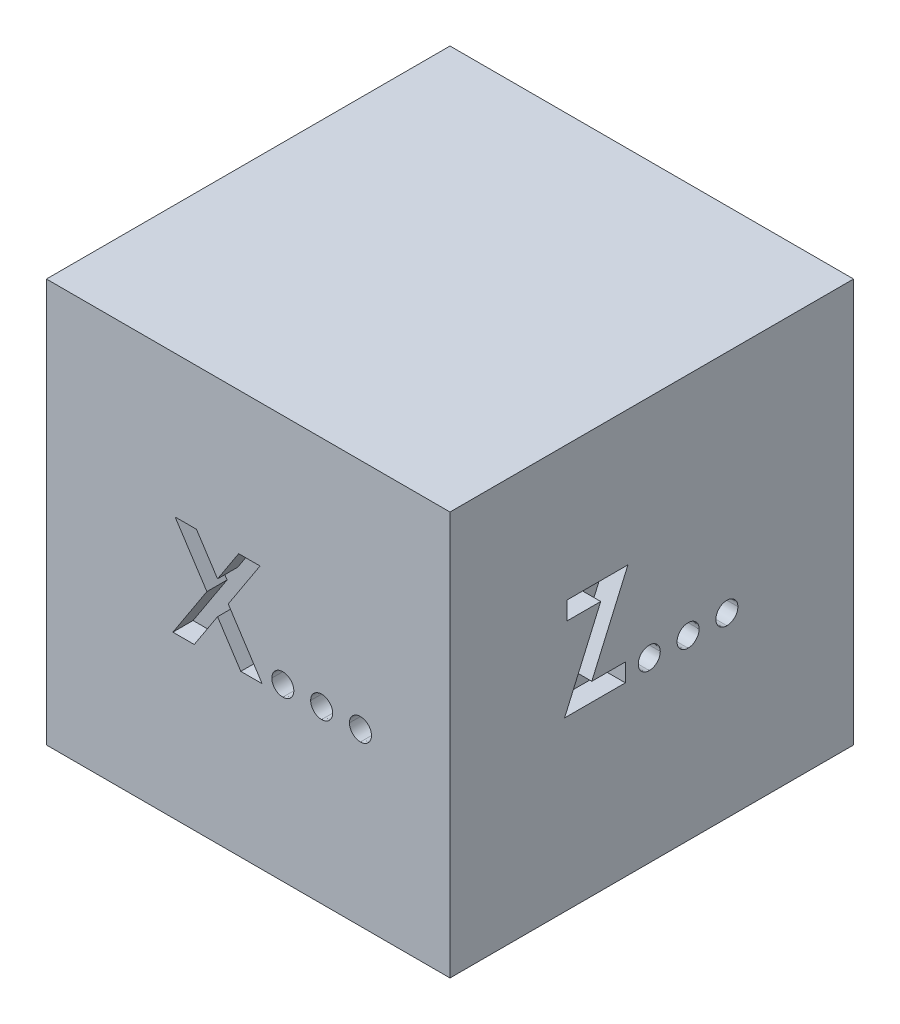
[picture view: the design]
ISO-10303-21;
HEADER;
FILE_DESCRIPTION(('STEP AP214'),'2;1');
FILE_NAME('part.step','',(''),(''),'','','');
FILE_SCHEMA(('AUTOMOTIVE_DESIGN { 1 0 10303 214 1 1 1 1 }'));
ENDSEC;
DATA;
#1=APPLICATION_CONTEXT('core data for automotive mechanical design processes');
#2=APPLICATION_PROTOCOL_DEFINITION('international standard','automotive_design',2000,#1);
#3=PRODUCT_CONTEXT('',#1,'mechanical');
#4=PRODUCT('Part','Part','',(#3));
#5=PRODUCT_RELATED_PRODUCT_CATEGORY('part','',(#4));
#6=PRODUCT_DEFINITION_FORMATION('','',#4);
#7=PRODUCT_DEFINITION_CONTEXT('part definition',#1,'design');
#8=PRODUCT_DEFINITION('design','',#6,#7);
#9=PRODUCT_DEFINITION_SHAPE('','',#8);
#10=(LENGTH_UNIT() NAMED_UNIT(*) SI_UNIT(.MILLI.,.METRE.));
#11=(NAMED_UNIT(*) PLANE_ANGLE_UNIT() SI_UNIT($,.RADIAN.));
#12=(NAMED_UNIT(*) SI_UNIT($,.STERADIAN.) SOLID_ANGLE_UNIT());
#13=UNCERTAINTY_MEASURE_WITH_UNIT(LENGTH_MEASURE(1.E-05),#10,'distance_accuracy_value','');
#14=(GEOMETRIC_REPRESENTATION_CONTEXT(3) GLOBAL_UNCERTAINTY_ASSIGNED_CONTEXT((#13)) GLOBAL_UNIT_ASSIGNED_CONTEXT((#10,
#11,#12)) REPRESENTATION_CONTEXT('',''));
#15=CARTESIAN_POINT('',(0.,0.,0.));
#16=DIRECTION('',(0.,0.,1.));
#17=DIRECTION('',(1.,0.,0.));
#18=AXIS2_PLACEMENT_3D('',#15,#16,#17);
#19=CARTESIAN_POINT('',(0.,0.,1.));
#20=DIRECTION('',(1.,0.,0.));
#21=DIRECTION('',(0.,0.,-1.));
#22=AXIS2_PLACEMENT_3D('',#19,#20,#21);
#23=PLANE('',#22);
#24=CARTESIAN_POINT('',(0.,0.525952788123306,0.604405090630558));
#25=CARTESIAN_POINT('',(0.,0.527363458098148,0.604480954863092));
#26=CARTESIAN_POINT('',(0.,0.530117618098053,0.604629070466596));
#27=CARTESIAN_POINT('',(0.,0.534060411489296,0.605827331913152));
#28=CARTESIAN_POINT('',(0.,0.537643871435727,0.607782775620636));
#29=CARTESIAN_POINT('',(0.,0.540815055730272,0.610426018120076));
#30=CARTESIAN_POINT('',(0.,0.543471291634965,0.613606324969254));
#31=CARTESIAN_POINT('',(0.,0.545404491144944,0.617198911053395));
#32=CARTESIAN_POINT('',(0.,0.546550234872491,0.621130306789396));
#33=CARTESIAN_POINT('',(0.,0.546706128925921,0.623845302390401));
#34=CARTESIAN_POINT('',(0.,0.54678612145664,0.625238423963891));
#35=B_SPLINE_CURVE_WITH_KNOTS('',3,(#24,#25,#26,#27,#28,#29,#30,#31,#32,#33,#34),.UNSPECIFIED.,
.F.,.F.,(4,1,1,1,1,1,1,1,4),(0.,0.129096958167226,0.252045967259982,0.373904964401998,
0.501037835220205,0.628170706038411,0.751376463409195,0.872426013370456,1.),.UNSPECIFIED.);
#36=CARTESIAN_POINT('',(0.,0.525952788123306,0.604405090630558));
#37=VERTEX_POINT('',#36);
#38=CARTESIAN_POINT('',(0.,0.54678612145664,0.625238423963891));
#39=VERTEX_POINT('',#38);
#40=EDGE_CURVE('E55',#37,#39,#35,.T.);
#41=ORIENTED_EDGE('',*,*,#40,.T.);
#42=CARTESIAN_POINT('',(0.,0.54678612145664,0.625238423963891));
#43=CARTESIAN_POINT('',(0.,0.54670339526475,0.626630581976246));
#44=CARTESIAN_POINT('',(0.,0.546541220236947,0.629359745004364));
#45=CARTESIAN_POINT('',(0.,0.545428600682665,0.633305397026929));
#46=CARTESIAN_POINT('',(0.,0.543452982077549,0.636876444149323));
#47=CARTESIAN_POINT('',(0.,0.540819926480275,0.640057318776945));
#48=CARTESIAN_POINT('',(0.,0.537627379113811,0.642679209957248));
#49=CARTESIAN_POINT('',(0.,0.534084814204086,0.644725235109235));
#50=CARTESIAN_POINT('',(0.,0.530106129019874,0.645828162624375));
#51=CARTESIAN_POINT('',(0.,0.527361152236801,0.645989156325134));
#52=CARTESIAN_POINT('',(0.,0.525952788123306,0.646071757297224));
#53=B_SPLINE_CURVE_WITH_KNOTS('',3,(#42,#43,#44,#45,#46,#47,#48,#49,#50,#51,#52),.UNSPECIFIED.,
.F.,.F.,(4,1,1,1,1,1,1,1,4),(0.,0.127518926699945,0.249985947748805,0.371792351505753,
0.498870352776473,0.625948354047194,0.748491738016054,0.870958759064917,1.),.UNSPECIFIED.);
#54=CARTESIAN_POINT('',(0.,0.525952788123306,0.646071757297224));
#55=VERTEX_POINT('',#54);
#56=EDGE_CURVE('E487',#39,#55,#53,.T.);
#57=ORIENTED_EDGE('',*,*,#56,.T.);
#58=CARTESIAN_POINT('',(0.,0.525952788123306,0.646071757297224));
#59=CARTESIAN_POINT('',(0.,0.524578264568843,0.645986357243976));
#60=CARTESIAN_POINT('',(0.,0.521867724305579,0.645817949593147));
#61=CARTESIAN_POINT('',(0.,0.517919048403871,0.644727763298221));
#62=CARTESIAN_POINT('',(0.,0.514374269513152,0.642663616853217));
#63=CARTESIAN_POINT('',(0.,0.511138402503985,0.640075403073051));
#64=CARTESIAN_POINT('',(0.,0.508499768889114,0.636875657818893));
#65=CARTESIAN_POINT('',(0.,0.506540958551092,0.633296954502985));
#66=CARTESIAN_POINT('',(0.,0.505348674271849,0.629369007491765));
#67=CARTESIAN_POINT('',(0.,0.505196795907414,0.626632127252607));
#68=CARTESIAN_POINT('',(0.,0.505119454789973,0.625238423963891));
#69=B_SPLINE_CURVE_WITH_KNOTS('',3,(#58,#59,#60,#61,#62,#63,#64,#65,#66,#67,#68),.UNSPECIFIED.,
.F.,.F.,(4,1,1,1,1,1,1,1,4),(0.,0.126177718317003,0.248820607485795,0.371539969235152,
0.499983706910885,0.627244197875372,0.749225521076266,0.87229795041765,1.),.UNSPECIFIED.);
#70=CARTESIAN_POINT('',(0.,0.505119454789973,0.625238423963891));
#71=VERTEX_POINT('',#70);
#72=EDGE_CURVE('E2022',#55,#71,#69,.T.);
#73=ORIENTED_EDGE('',*,*,#72,.T.);
#74=CARTESIAN_POINT('',(0.,0.505119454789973,0.625238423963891));
#75=CARTESIAN_POINT('',(0.,0.505193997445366,0.623843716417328));
#76=CARTESIAN_POINT('',(0.,0.505339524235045,0.621120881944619));
#77=CARTESIAN_POINT('',(0.,0.506565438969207,0.617207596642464));
#78=CARTESIAN_POINT('',(0.,0.508481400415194,0.61360709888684));
#79=CARTESIAN_POINT('',(0.,0.511143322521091,0.610407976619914));
#80=CARTESIAN_POINT('',(0.,0.514357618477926,0.607798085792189));
#81=CARTESIAN_POINT('',(0.,0.517943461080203,0.605824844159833));
#82=CARTESIAN_POINT('',(0.,0.521856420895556,0.604639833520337));
#83=CARTESIAN_POINT('',(0.,0.524576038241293,0.604483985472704));
#84=CARTESIAN_POINT('',(0.,0.525952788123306,0.604405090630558));
#85=B_SPLINE_CURVE_WITH_KNOTS('',3,(#74,#75,#76,#77,#78,#79,#80,#81,#82,#83,#84),.UNSPECIFIED.,
.F.,.F.,(4,1,1,1,1,1,1,1,4),(0.,0.127756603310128,0.249414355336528,0.372796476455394,
0.500111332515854,0.628609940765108,0.750643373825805,0.873768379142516,1.),.UNSPECIFIED.);
#86=EDGE_CURVE('E500',#71,#37,#85,.T.);
#87=ORIENTED_EDGE('',*,*,#86,.T.);
#88=EDGE_LOOP('',(#41,#57,#73,#87));
#89=FACE_BOUND('',#88,.T.);
#90=DIRECTION('',(0.,-0.521331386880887,-0.853354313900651));
#91=VECTOR('',#90,1.);
#92=CARTESIAN_POINT('',(0.,0.381052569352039,0.524927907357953));
#93=LINE('',#92,#91);
#94=CARTESIAN_POINT('',(0.,0.381052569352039,0.524927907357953));
#95=VERTEX_POINT('',#94);
#96=CARTESIAN_POINT('',(0.,0.300924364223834,0.393768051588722));
#97=VERTEX_POINT('',#96);
#98=EDGE_CURVE('E584',#95,#97,#93,.T.);
#99=ORIENTED_EDGE('',*,*,#98,.T.);
#100=DIRECTION('',(0.,1.,0.));
#101=VECTOR('',#100,1.);
#102=CARTESIAN_POINT('',(0.,0.300924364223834,0.393768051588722));
#103=LINE('',#102,#101);
#104=CARTESIAN_POINT('',(0.,0.326615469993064,0.393768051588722));
#105=VERTEX_POINT('',#104);
#106=EDGE_CURVE('E608',#97,#105,#103,.T.);
#107=ORIENTED_EDGE('',*,*,#106,.T.);
#108=DIRECTION('',(0.,0.521787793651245,0.853075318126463));
#109=VECTOR('',#108,1.);
#110=CARTESIAN_POINT('',(0.,0.326615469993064,0.393768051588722));
#111=LINE('',#110,#109);
#112=CARTESIAN_POINT('',(0.,0.392320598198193,0.501189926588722));
#113=VERTEX_POINT('',#112);
#114=EDGE_CURVE('E611',#105,#113,#111,.T.);
#115=ORIENTED_EDGE('',*,*,#114,.T.);
#116=DIRECTION('',(0.,0.521208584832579,-0.853429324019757));
#117=VECTOR('',#116,1.);
#118=CARTESIAN_POINT('',(0.,0.392320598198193,0.501189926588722));
#119=LINE('',#118,#117);
#120=CARTESIAN_POINT('',(0.,0.45792556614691,0.393768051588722));
#121=VERTEX_POINT('',#120);
#122=EDGE_CURVE('E614',#113,#121,#119,.T.);
#123=ORIENTED_EDGE('',*,*,#122,.T.);
#124=DIRECTION('',(0.,1.,0.));
#125=VECTOR('',#124,1.);
#126=CARTESIAN_POINT('',(0.,0.45792556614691,0.393768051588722));
#127=LINE('',#126,#125);
#128=CARTESIAN_POINT('',(0.,0.483616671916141,0.393768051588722));
#129=VERTEX_POINT('',#128);
#130=EDGE_CURVE('E617',#121,#129,#127,.T.);
#131=ORIENTED_EDGE('',*,*,#130,.T.);
#132=DIRECTION('',(0.,-0.521331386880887,0.853354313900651));
#133=VECTOR('',#132,1.);
#134=CARTESIAN_POINT('',(0.,0.483616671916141,0.393768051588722));
#135=LINE('',#134,#133);
#136=CARTESIAN_POINT('',(0.,0.403488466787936,0.524927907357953));
#137=VERTEX_POINT('',#136);
#138=EDGE_CURVE('E620',#129,#137,#135,.T.);
#139=ORIENTED_EDGE('',*,*,#138,.T.);
#140=DIRECTION('',(0.,0.,1.));
#141=VECTOR('',#140,1.);
#142=CARTESIAN_POINT('',(0.,0.403488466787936,0.524927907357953));
#143=LINE('',#142,#141);
#144=CARTESIAN_POINT('',(0.,0.403488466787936,0.643768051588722));
#145=VERTEX_POINT('',#144);
#146=EDGE_CURVE('E623',#137,#145,#143,.T.);
#147=ORIENTED_EDGE('',*,*,#146,.T.);
#148=DIRECTION('',(0.,-1.,0.));
#149=VECTOR('',#148,1.);
#150=CARTESIAN_POINT('',(0.,0.403488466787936,0.643768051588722));
#151=LINE('',#150,#149);
#152=CARTESIAN_POINT('',(0.,0.381052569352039,0.643768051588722));
#153=VERTEX_POINT('',#152);
#154=EDGE_CURVE('E626',#145,#153,#151,.T.);
#155=ORIENTED_EDGE('',*,*,#154,.T.);
#156=DIRECTION('',(0.,0.,-1.));
#157=VECTOR('',#156,1.);
#158=CARTESIAN_POINT('',(0.,0.381052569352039,0.643768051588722));
#159=LINE('',#158,#157);
#160=EDGE_CURVE('E589',#153,#95,#159,.T.);
#161=ORIENTED_EDGE('',*,*,#160,.T.);
#162=EDGE_LOOP('',(#99,#107,#115,#123,#131,#139,#147,#155,#161));
#163=FACE_BOUND('',#162,.T.);
#164=DIRECTION('',(0.,-1.,0.));
#165=VECTOR('',#164,1.);
#166=CARTESIAN_POINT('',(0.,0.,0.));
#167=LINE('',#166,#165);
#168=CARTESIAN_POINT('',(0.,1.,0.));
#169=VERTEX_POINT('',#168);
#170=CARTESIAN_POINT('',(0.,0.,0.));
#171=VERTEX_POINT('',#170);
#172=EDGE_CURVE('E1040',#169,#171,#167,.T.);
#173=ORIENTED_EDGE('',*,*,#172,.T.);
#174=DIRECTION('',(0.,0.,-1.));
#175=VECTOR('',#174,1.);
#176=CARTESIAN_POINT('',(0.,0.,1.));
#177=LINE('',#176,#175);
#178=CARTESIAN_POINT('',(0.,0.,1.));
#179=VERTEX_POINT('',#178);
#180=EDGE_CURVE('E11',#179,#171,#177,.T.);
#181=ORIENTED_EDGE('',*,*,#180,.F.);
#182=DIRECTION('',(0.,-1.,0.));
#183=VECTOR('',#182,1.);
#184=CARTESIAN_POINT('',(0.,0.,1.));
#185=LINE('',#184,#183);
#186=CARTESIAN_POINT('',(0.,1.,1.));
#187=VERTEX_POINT('',#186);
#188=EDGE_CURVE('E1041',#187,#179,#185,.T.);
#189=ORIENTED_EDGE('',*,*,#188,.F.);
#190=DIRECTION('',(0.,0.,-1.));
#191=VECTOR('',#190,1.);
#192=CARTESIAN_POINT('',(0.,1.,1.));
#193=LINE('',#192,#191);
#194=EDGE_CURVE('E1051',#187,#169,#193,.T.);
#195=ORIENTED_EDGE('',*,*,#194,.T.);
#196=EDGE_LOOP('',(#173,#181,#189,#195));
#197=FACE_BOUND('',#196,.T.);
#198=CARTESIAN_POINT('',(0.,0.462146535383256,0.605767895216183));
#199=CARTESIAN_POINT('',(0.,0.463557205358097,0.605843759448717));
#200=CARTESIAN_POINT('',(0.,0.466311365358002,0.605991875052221));
#201=CARTESIAN_POINT('',(0.,0.470254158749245,0.607190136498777));
#202=CARTESIAN_POINT('',(0.,0.473837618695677,0.609145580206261));
#203=CARTESIAN_POINT('',(0.,0.477008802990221,0.611788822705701));
#204=CARTESIAN_POINT('',(0.,0.479665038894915,0.614969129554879));
#205=CARTESIAN_POINT('',(0.,0.481598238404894,0.618561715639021));
#206=CARTESIAN_POINT('',(0.,0.48274398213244,0.622493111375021));
#207=CARTESIAN_POINT('',(0.,0.482899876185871,0.625208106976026));
#208=CARTESIAN_POINT('',(0.,0.482979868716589,0.626601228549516));
#209=B_SPLINE_CURVE_WITH_KNOTS('',3,(#198,#199,#200,#201,#202,#203,#204,#205,#206,#207,#208),
.UNSPECIFIED.,.F.,.F.,(4,1,1,1,1,1,1,1,4),(0.,0.129096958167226,0.25204596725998,
0.373904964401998,0.501037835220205,0.628170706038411,0.751376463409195,0.872426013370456,1.),.UNSPECIFIED.);
#210=CARTESIAN_POINT('',(0.,0.462146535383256,0.605767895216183));
#211=VERTEX_POINT('',#210);
#212=CARTESIAN_POINT('',(0.,0.482979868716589,0.626601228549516));
#213=VERTEX_POINT('',#212);
#214=EDGE_CURVE('E538',#211,#213,#209,.T.);
#215=ORIENTED_EDGE('',*,*,#214,.T.);
#216=CARTESIAN_POINT('',(0.,0.482979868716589,0.626601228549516));
#217=CARTESIAN_POINT('',(0.,0.4828971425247,0.627993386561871));
#218=CARTESIAN_POINT('',(0.,0.482734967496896,0.630722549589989));
#219=CARTESIAN_POINT('',(0.,0.481622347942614,0.634668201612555));
#220=CARTESIAN_POINT('',(0.,0.479646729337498,0.638239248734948));
#221=CARTESIAN_POINT('',(0.,0.477013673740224,0.64142012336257));
#222=CARTESIAN_POINT('',(0.,0.47382112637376,0.644042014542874));
#223=CARTESIAN_POINT('',(0.,0.470278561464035,0.64608803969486));
#224=CARTESIAN_POINT('',(0.,0.466299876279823,0.647190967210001));
#225=CARTESIAN_POINT('',(0.,0.46355489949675,0.647351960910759));
#226=CARTESIAN_POINT('',(0.,0.462146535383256,0.64743456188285));
#227=B_SPLINE_CURVE_WITH_KNOTS('',3,(#216,#217,#218,#219,#220,#221,#222,#223,#224,#225,#226),
.UNSPECIFIED.,.F.,.F.,(4,1,1,1,1,1,1,1,4),(0.,0.127518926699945,0.249985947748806,
0.371792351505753,0.498870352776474,0.625948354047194,0.748491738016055,0.870958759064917,1.),.UNSPECIFIED.);
#228=CARTESIAN_POINT('',(0.,0.462146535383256,0.64743456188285));
#229=VERTEX_POINT('',#228);
#230=EDGE_CURVE('E546',#213,#229,#227,.T.);
#231=ORIENTED_EDGE('',*,*,#230,.T.);
#232=CARTESIAN_POINT('',(0.,0.462146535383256,0.64743456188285));
#233=CARTESIAN_POINT('',(0.,0.460772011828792,0.647349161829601));
#234=CARTESIAN_POINT('',(0.,0.458061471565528,0.647180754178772));
#235=CARTESIAN_POINT('',(0.,0.45411279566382,0.646090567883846));
#236=CARTESIAN_POINT('',(0.,0.450568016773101,0.644026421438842));
#237=CARTESIAN_POINT('',(0.,0.447332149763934,0.641438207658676));
#238=CARTESIAN_POINT('',(0.,0.444693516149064,0.638238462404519));
#239=CARTESIAN_POINT('',(0.,0.442734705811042,0.63465975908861));
#240=CARTESIAN_POINT('',(0.,0.441542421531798,0.63073181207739));
#241=CARTESIAN_POINT('',(0.,0.441390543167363,0.627994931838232));
#242=CARTESIAN_POINT('',(0.,0.441313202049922,0.626601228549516));
#243=B_SPLINE_CURVE_WITH_KNOTS('',3,(#232,#233,#234,#235,#236,#237,#238,#239,#240,#241,#242),
.UNSPECIFIED.,.F.,.F.,(4,1,1,1,1,1,1,1,4),(0.,0.126177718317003,0.248820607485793,
0.371539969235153,0.499983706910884,0.627244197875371,0.749225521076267,0.87229795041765,1.),.UNSPECIFIED.);
#244=CARTESIAN_POINT('',(0.,0.441313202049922,0.626601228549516));
#245=VERTEX_POINT('',#244);
#246=EDGE_CURVE('E555',#229,#245,#243,.T.);
#247=ORIENTED_EDGE('',*,*,#246,.T.);
#248=CARTESIAN_POINT('',(0.,0.441313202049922,0.626601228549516));
#249=CARTESIAN_POINT('',(0.,0.441387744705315,0.625206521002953));
#250=CARTESIAN_POINT('',(0.,0.441533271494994,0.622483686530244));
#251=CARTESIAN_POINT('',(0.,0.442759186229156,0.618570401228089));
#252=CARTESIAN_POINT('',(0.,0.444675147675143,0.614969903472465));
#253=CARTESIAN_POINT('',(0.,0.44733706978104,0.611770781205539));
#254=CARTESIAN_POINT('',(0.,0.450551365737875,0.609160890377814));
#255=CARTESIAN_POINT('',(0.,0.454137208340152,0.607187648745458));
#256=CARTESIAN_POINT('',(0.,0.458050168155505,0.606002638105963));
#257=CARTESIAN_POINT('',(0.,0.460769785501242,0.605846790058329));
#258=CARTESIAN_POINT('',(0.,0.462146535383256,0.605767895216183));
#259=B_SPLINE_CURVE_WITH_KNOTS('',3,(#248,#249,#250,#251,#252,#253,#254,#255,#256,#257,#258),
.UNSPECIFIED.,.F.,.F.,(4,1,1,1,1,1,1,1,4),(0.,0.127756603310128,0.249414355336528,
0.372796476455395,0.500111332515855,0.628609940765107,0.750643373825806,0.873768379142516,1.),.UNSPECIFIED.);
#260=EDGE_CURVE('E563',#245,#211,#259,.T.);
#261=ORIENTED_EDGE('',*,*,#260,.T.);
#262=EDGE_LOOP('',(#215,#231,#247,#261));
#263=FACE_BOUND('',#262,.T.);
#264=CARTESIAN_POINT('',(0.,0.589940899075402,0.604056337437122));
#265=CARTESIAN_POINT('',(0.,0.591351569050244,0.604132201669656));
#266=CARTESIAN_POINT('',(0.,0.594105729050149,0.60428031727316));
#267=CARTESIAN_POINT('',(0.,0.598048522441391,0.605478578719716));
#268=CARTESIAN_POINT('',(0.,0.601631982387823,0.6074340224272));
#269=CARTESIAN_POINT('',(0.,0.604803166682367,0.610077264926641));
#270=CARTESIAN_POINT('',(0.,0.607459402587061,0.613257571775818));
#271=CARTESIAN_POINT('',(0.,0.60939260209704,0.61685015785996));
#272=CARTESIAN_POINT('',(0.,0.610538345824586,0.62078155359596));
#273=CARTESIAN_POINT('',(0.,0.610694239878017,0.623496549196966));
#274=CARTESIAN_POINT('',(0.,0.610774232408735,0.624889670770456));
#275=B_SPLINE_CURVE_WITH_KNOTS('',3,(#264,#265,#266,#267,#268,#269,#270,#271,#272,#273,#274),
.UNSPECIFIED.,.F.,.F.,(4,1,1,1,1,1,1,1,4),(0.,0.129096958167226,0.252045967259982,
0.373904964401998,0.501037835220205,0.628170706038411,0.751376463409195,0.872426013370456,1.),.UNSPECIFIED.);
#276=CARTESIAN_POINT('',(0.,0.589940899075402,0.604056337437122));
#277=VERTEX_POINT('',#276);
#278=CARTESIAN_POINT('',(0.,0.610774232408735,0.624889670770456));
#279=VERTEX_POINT('',#278);
#280=EDGE_CURVE('E47',#277,#279,#275,.T.);
#281=ORIENTED_EDGE('',*,*,#280,.T.);
#282=CARTESIAN_POINT('',(0.,0.610774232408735,0.624889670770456));
#283=CARTESIAN_POINT('',(0.,0.610691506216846,0.626281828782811));
#284=CARTESIAN_POINT('',(0.,0.610529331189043,0.629010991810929));
#285=CARTESIAN_POINT('',(0.,0.60941671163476,0.632956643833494));
#286=CARTESIAN_POINT('',(0.,0.607441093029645,0.636527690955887));
#287=CARTESIAN_POINT('',(0.,0.60480803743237,0.63970856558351));
#288=CARTESIAN_POINT('',(0.,0.601615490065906,0.642330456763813));
#289=CARTESIAN_POINT('',(0.,0.598072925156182,0.644376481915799));
#290=CARTESIAN_POINT('',(0.,0.594094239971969,0.64547940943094));
#291=CARTESIAN_POINT('',(0.,0.591349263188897,0.645640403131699));
#292=CARTESIAN_POINT('',(0.,0.589940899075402,0.645723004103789));
#293=B_SPLINE_CURVE_WITH_KNOTS('',3,(#282,#283,#284,#285,#286,#287,#288,#289,#290,#291,#292),
.UNSPECIFIED.,.F.,.F.,(4,1,1,1,1,1,1,1,4),(0.,0.127518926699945,0.249985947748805,
0.371792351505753,0.498870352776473,0.625948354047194,0.748491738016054,0.870958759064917,1.),.UNSPECIFIED.);
#294=CARTESIAN_POINT('',(0.,0.589940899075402,0.645723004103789));
#295=VERTEX_POINT('',#294);
#296=EDGE_CURVE('E484',#279,#295,#293,.T.);
#297=ORIENTED_EDGE('',*,*,#296,.T.);
#298=CARTESIAN_POINT('',(0.,0.589940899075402,0.645723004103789));
#299=CARTESIAN_POINT('',(0.,0.588566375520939,0.64563760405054));
#300=CARTESIAN_POINT('',(0.,0.585855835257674,0.645469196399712));
#301=CARTESIAN_POINT('',(0.,0.581907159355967,0.644379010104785));
#302=CARTESIAN_POINT('',(0.,0.578362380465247,0.642314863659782));
#303=CARTESIAN_POINT('',(0.,0.57512651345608,0.639726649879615));
#304=CARTESIAN_POINT('',(0.,0.57248787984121,0.636526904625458));
#305=CARTESIAN_POINT('',(0.,0.570529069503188,0.63294820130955));
#306=CARTESIAN_POINT('',(0.,0.569336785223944,0.62902025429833));
#307=CARTESIAN_POINT('',(0.,0.569184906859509,0.626283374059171));
#308=CARTESIAN_POINT('',(0.,0.569107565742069,0.624889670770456));
#309=B_SPLINE_CURVE_WITH_KNOTS('',3,(#298,#299,#300,#301,#302,#303,#304,#305,#306,#307,#308),
.UNSPECIFIED.,.F.,.F.,(4,1,1,1,1,1,1,1,4),(0.,0.126177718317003,0.248820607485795,
0.371539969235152,0.499983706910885,0.627244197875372,0.749225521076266,0.87229795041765,1.),.UNSPECIFIED.);
#310=CARTESIAN_POINT('',(0.,0.569107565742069,0.624889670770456));
#311=VERTEX_POINT('',#310);
#312=EDGE_CURVE('E1966',#295,#311,#309,.T.);
#313=ORIENTED_EDGE('',*,*,#312,.T.);
#314=CARTESIAN_POINT('',(0.,0.569107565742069,0.624889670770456));
#315=CARTESIAN_POINT('',(0.,0.569182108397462,0.623494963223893));
#316=CARTESIAN_POINT('',(0.,0.56932763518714,0.620772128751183));
#317=CARTESIAN_POINT('',(0.,0.570553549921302,0.616858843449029));
#318=CARTESIAN_POINT('',(0.,0.572469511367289,0.613258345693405));
#319=CARTESIAN_POINT('',(0.,0.575131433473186,0.610059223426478));
#320=CARTESIAN_POINT('',(0.,0.578345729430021,0.607449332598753));
#321=CARTESIAN_POINT('',(0.,0.581931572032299,0.605476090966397));
#322=CARTESIAN_POINT('',(0.,0.585844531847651,0.604291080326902));
#323=CARTESIAN_POINT('',(0.,0.588564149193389,0.604135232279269));
#324=CARTESIAN_POINT('',(0.,0.589940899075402,0.604056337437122));
#325=B_SPLINE_CURVE_WITH_KNOTS('',3,(#314,#315,#316,#317,#318,#319,#320,#321,#322,#323,#324),
.UNSPECIFIED.,.F.,.F.,(4,1,1,1,1,1,1,1,4),(0.,0.127756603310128,0.249414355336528,
0.372796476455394,0.500111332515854,0.628609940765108,0.750643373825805,0.873768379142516,1.),.UNSPECIFIED.);
#326=EDGE_CURVE('E480',#311,#277,#325,.T.);
#327=ORIENTED_EDGE('',*,*,#326,.T.);
#328=EDGE_LOOP('',(#281,#297,#313,#327));
#329=FACE_BOUND('',#328,.T.);
#330=ADVANCED_FACE('F33',(#89,#163,#197,#263,#329),#23,.F.);
#331=CARTESIAN_POINT('',(0.,0.,1.));
#332=DIRECTION('',(0.,0.,-1.));
#333=DIRECTION('',(-1.,0.,0.));
#334=AXIS2_PLACEMENT_3D('',#331,#332,#333);
#335=PLANE('',#334);
#336=CARTESIAN_POINT('',(0.654692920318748,0.422946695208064,1.));
#337=CARTESIAN_POINT('',(0.654781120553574,0.424778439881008,1.));
#338=CARTESIAN_POINT('',(0.654953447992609,0.428357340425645,1.));
#339=CARTESIAN_POINT('',(0.656550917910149,0.433473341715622,1.));
#340=CARTESIAN_POINT('',(0.659020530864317,0.438195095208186,1.));
#341=CARTESIAN_POINT('',(0.662552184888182,0.442290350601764,1.));
#342=CARTESIAN_POINT('',(0.666711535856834,0.445731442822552,1.));
#343=CARTESIAN_POINT('',(0.671396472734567,0.448323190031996,1.));
#344=CARTESIAN_POINT('',(0.676557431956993,0.449797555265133,1.));
#345=CARTESIAN_POINT('',(0.680124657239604,0.449991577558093,1.));
#346=CARTESIAN_POINT('',(0.681936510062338,0.450090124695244,1.));
#347=B_SPLINE_CURVE_WITH_KNOTS('',3,(#336,#337,#338,#339,#340,#341,#342,#343,#344,#345,#346),
.UNSPECIFIED.,.F.,.F.,(4,1,1,1,1,1,1,1,4),(0.,0.128226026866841,0.250530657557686,
0.372638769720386,0.499833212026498,0.627178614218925,0.749841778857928,0.872940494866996,1.),.UNSPECIFIED.);
#348=CARTESIAN_POINT('',(0.654692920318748,0.422946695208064,1.));
#349=VERTEX_POINT('',#348);
#350=CARTESIAN_POINT('',(0.681936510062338,0.450090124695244,1.));
#351=VERTEX_POINT('',#350);
#352=EDGE_CURVE('E697',#349,#351,#347,.T.);
#353=ORIENTED_EDGE('',*,*,#352,.T.);
#354=CARTESIAN_POINT('',(0.681936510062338,0.450090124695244,1.));
#355=CARTESIAN_POINT('',(0.683747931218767,0.449990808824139,1.));
#356=CARTESIAN_POINT('',(0.687314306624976,0.449795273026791,1.));
#357=CARTESIAN_POINT('',(0.692467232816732,0.448336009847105,1.));
#358=CARTESIAN_POINT('',(0.697117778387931,0.445714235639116,1.));
#359=CARTESIAN_POINT('',(0.70127598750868,0.442294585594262,1.));
#360=CARTESIAN_POINT('',(0.704792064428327,0.438180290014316,1.));
#361=CARTESIAN_POINT('',(0.707333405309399,0.433488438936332,1.));
#362=CARTESIAN_POINT('',(0.708915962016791,0.428355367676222,1.));
#363=CARTESIAN_POINT('',(0.709090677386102,0.424777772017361,1.));
#364=CARTESIAN_POINT('',(0.709180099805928,0.422946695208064,1.));
#365=B_SPLINE_CURVE_WITH_KNOTS('',3,(#354,#355,#356,#357,#358,#359,#360,#361,#362,#363,#364),
.UNSPECIFIED.,.F.,.F.,(4,1,1,1,1,1,1,1,4),(0.,0.127119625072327,0.250276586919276,
0.371969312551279,0.499374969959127,0.626629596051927,0.749350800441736,0.871713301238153,1.),.UNSPECIFIED.);
#366=CARTESIAN_POINT('',(0.709180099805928,0.422946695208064,1.));
#367=VERTEX_POINT('',#366);
#368=EDGE_CURVE('E705',#351,#367,#365,.T.);
#369=ORIENTED_EDGE('',*,*,#368,.T.);
#370=CARTESIAN_POINT('',(0.709180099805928,0.422946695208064,1.));
#371=CARTESIAN_POINT('',(0.70909126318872,0.421115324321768,1.));
#372=CARTESIAN_POINT('',(0.708917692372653,0.417537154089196,1.));
#373=CARTESIAN_POINT('',(0.707322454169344,0.412394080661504,1.));
#374=CARTESIAN_POINT('',(0.704795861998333,0.4076636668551,1.));
#375=CARTESIAN_POINT('',(0.701275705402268,0.403505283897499,1.));
#376=CARTESIAN_POINT('',(0.697134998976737,0.400021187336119,1.));
#377=CARTESIAN_POINT('',(0.692456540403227,0.397423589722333,1.));
#378=CARTESIAN_POINT('',(0.687324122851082,0.39588154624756,1.));
#379=CARTESIAN_POINT('',(0.68374965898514,0.395696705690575,1.));
#380=CARTESIAN_POINT('',(0.681936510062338,0.395602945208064,1.));
#381=B_SPLINE_CURVE_WITH_KNOTS('',3,(#370,#371,#372,#373,#374,#375,#376,#377,#378,#379,#380),
.UNSPECIFIED.,.F.,.F.,(4,1,1,1,1,1,1,1,4),(0.,0.127902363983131,0.249898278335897,
0.373279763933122,0.501048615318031,0.628817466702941,0.750145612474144,0.873261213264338,1.),.UNSPECIFIED.);
#382=CARTESIAN_POINT('',(0.681936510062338,0.395602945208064,1.));
#383=VERTEX_POINT('',#382);
#384=EDGE_CURVE('E714',#367,#383,#381,.T.);
#385=ORIENTED_EDGE('',*,*,#384,.T.);
#386=CARTESIAN_POINT('',(0.681936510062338,0.395602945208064,1.));
#387=CARTESIAN_POINT('',(0.680122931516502,0.395695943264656,1.));
#388=CARTESIAN_POINT('',(0.676547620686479,0.395879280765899,1.));
#389=CARTESIAN_POINT('',(0.671407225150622,0.397436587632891,1.));
#390=CARTESIAN_POINT('',(0.666694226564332,0.400003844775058,1.));
#391=CARTESIAN_POINT('',(0.662552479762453,0.403509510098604,1.));
#392=CARTESIAN_POINT('',(0.659016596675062,0.407648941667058,1.));
#393=CARTESIAN_POINT('',(0.656561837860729,0.412409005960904,1.));
#394=CARTESIAN_POINT('',(0.654951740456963,0.417535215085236,1.));
#395=CARTESIAN_POINT('',(0.654780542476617,0.421114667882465,1.));
#396=CARTESIAN_POINT('',(0.654692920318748,0.422946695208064,1.));
#397=B_SPLINE_CURVE_WITH_KNOTS('',3,(#386,#387,#388,#389,#390,#391,#392,#393,#394,#395,#396),
.UNSPECIFIED.,.F.,.F.,(4,1,1,1,1,1,1,1,4),(0.,0.126678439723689,0.249735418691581,
0.372030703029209,0.499738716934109,0.627446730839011,0.750220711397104,0.872158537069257,1.),.UNSPECIFIED.);
#398=EDGE_CURVE('E722',#383,#349,#397,.T.);
#399=ORIENTED_EDGE('',*,*,#398,.T.);
#400=EDGE_LOOP('',(#353,#369,#385,#399));
#401=FACE_BOUND('',#400,.T.);
#402=DIRECTION('',(-0.54561077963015,0.838038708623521,0.));
#403=VECTOR('',#402,1.);
#404=CARTESIAN_POINT('',(0.39758154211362,0.527964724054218,1.));
#405=LINE('',#404,#403);
#406=CARTESIAN_POINT('',(0.39758154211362,0.527964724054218,1.));
#407=VERTEX_POINT('',#406);
#408=CARTESIAN_POINT('',(0.318905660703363,0.648808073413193,1.));
#409=VERTEX_POINT('',#408);
#410=EDGE_CURVE('E1310',#407,#409,#405,.T.);
#411=ORIENTED_EDGE('',*,*,#410,.T.);
#412=DIRECTION('',(1.,0.,0.));
#413=VECTOR('',#412,1.);
#414=CARTESIAN_POINT('',(0.318905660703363,0.648808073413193,1.));
#415=LINE('',#414,#413);
#416=CARTESIAN_POINT('',(0.371790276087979,0.648808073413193,1.));
#417=VERTEX_POINT('',#416);
#418=EDGE_CURVE('E1340',#409,#417,#415,.T.);
#419=ORIENTED_EDGE('',*,*,#418,.T.);
#420=DIRECTION('',(0.545374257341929,-0.838192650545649,0.));
#421=VECTOR('',#420,1.);
#422=CARTESIAN_POINT('',(0.371790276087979,0.648808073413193,1.));
#423=LINE('',#422,#421);
#424=CARTESIAN_POINT('',(0.424023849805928,0.568529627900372,1.));
#425=VERTEX_POINT('',#424);
#426=EDGE_CURVE('E1343',#417,#425,#423,.T.);
#427=ORIENTED_EDGE('',*,*,#426,.T.);
#428=DIRECTION('',(0.546108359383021,0.837714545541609,0.));
#429=VECTOR('',#428,1.);
#430=CARTESIAN_POINT('',(0.424023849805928,0.568529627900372,1.));
#431=LINE('',#430,#429);
#432=CARTESIAN_POINT('',(0.476357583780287,0.648808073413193,1.));
#433=VERTEX_POINT('',#432);
#434=EDGE_CURVE('E1346',#425,#433,#431,.T.);
#435=ORIENTED_EDGE('',*,*,#434,.T.);
#436=DIRECTION('',(1.,0.,0.));
#437=VECTOR('',#436,1.);
#438=CARTESIAN_POINT('',(0.476357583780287,0.648808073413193,1.));
#439=LINE('',#438,#437);
#440=CARTESIAN_POINT('',(0.529292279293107,0.648808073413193,1.));
#441=VERTEX_POINT('',#440);
#442=EDGE_CURVE('E1349',#433,#441,#439,.T.);
#443=ORIENTED_EDGE('',*,*,#442,.T.);
#444=DIRECTION('',(-0.546183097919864,-0.837665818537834,0.));
#445=VECTOR('',#444,1.);
#446=CARTESIAN_POINT('',(0.529292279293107,0.648808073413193,1.));
#447=LINE('',#446,#445);
#448=CARTESIAN_POINT('',(0.450466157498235,0.527914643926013,1.));
#449=VERTEX_POINT('',#448);
#450=EDGE_CURVE('E1352',#441,#449,#447,.T.);
#451=ORIENTED_EDGE('',*,*,#450,.T.);
#452=DIRECTION('',(0.545513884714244,-0.838101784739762,0.));
#453=VECTOR('',#452,1.);
#454=CARTESIAN_POINT('',(0.450466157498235,0.527914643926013,1.));
#455=LINE('',#454,#453);
#456=CARTESIAN_POINT('',(0.53450061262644,0.398808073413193,1.));
#457=VERTEX_POINT('',#456);
#458=EDGE_CURVE('E1355',#449,#457,#455,.T.);
#459=ORIENTED_EDGE('',*,*,#458,.T.);
#460=DIRECTION('',(-1.,0.,0.));
#461=VECTOR('',#460,1.);
#462=CARTESIAN_POINT('',(0.53450061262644,0.398808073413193,1.));
#463=LINE('',#462,#461);
#464=CARTESIAN_POINT('',(0.481615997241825,0.398808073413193,1.));
#465=VERTEX_POINT('',#464);
#466=EDGE_CURVE('E1358',#457,#465,#463,.T.);
#467=ORIENTED_EDGE('',*,*,#466,.T.);
#468=DIRECTION('',(-0.545254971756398,0.838270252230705,0.));
#469=VECTOR('',#468,1.);
#470=CARTESIAN_POINT('',(0.481615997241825,0.398808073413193,1.));
#471=LINE('',#470,#469);
#472=CARTESIAN_POINT('',(0.424023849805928,0.487349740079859,1.));
#473=VERTEX_POINT('',#472);
#474=EDGE_CURVE('E1361',#465,#473,#471,.T.);
#475=ORIENTED_EDGE('',*,*,#474,.T.);
#476=DIRECTION('',(-0.54625332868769,-0.837620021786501,0.));
#477=VECTOR('',#476,1.);
#478=CARTESIAN_POINT('',(0.424023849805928,0.487349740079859,1.));
#479=LINE('',#478,#477);
#480=CARTESIAN_POINT('',(0.366281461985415,0.398808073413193,1.));
#481=VERTEX_POINT('',#480);
#482=EDGE_CURVE('E1364',#473,#481,#479,.T.);
#483=ORIENTED_EDGE('',*,*,#482,.T.);
#484=DIRECTION('',(-1.,0.,0.));
#485=VECTOR('',#484,1.);
#486=CARTESIAN_POINT('',(0.366281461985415,0.398808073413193,1.));
#487=LINE('',#486,#485);
#488=CARTESIAN_POINT('',(0.313346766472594,0.398808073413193,1.));
#489=VERTEX_POINT('',#488);
#490=EDGE_CURVE('E1367',#481,#489,#487,.T.);
#491=ORIENTED_EDGE('',*,*,#490,.T.);
#492=DIRECTION('',(0.546277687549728,0.837604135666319,0.));
#493=VECTOR('',#492,1.);
#494=CARTESIAN_POINT('',(0.313346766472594,0.398808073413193,1.));
#495=LINE('',#494,#493);
#496=EDGE_CURVE('E1315',#489,#407,#495,.T.);
#497=ORIENTED_EDGE('',*,*,#496,.T.);
#498=EDGE_LOOP('',(#411,#419,#427,#435,#443,#451,#459,#467,#475,#483,#491,#497));
#499=FACE_BOUND('',#498,.T.);
#500=ORIENTED_EDGE('',*,*,#188,.T.);
#501=DIRECTION('',(1.,0.,0.));
#502=VECTOR('',#501,1.);
#503=CARTESIAN_POINT('',(0.,0.,1.));
#504=LINE('',#503,#502);
#505=CARTESIAN_POINT('',(1.,0.,1.));
#506=VERTEX_POINT('',#505);
#507=EDGE_CURVE('E1044',#179,#506,#504,.T.);
#508=ORIENTED_EDGE('',*,*,#507,.T.);
#509=DIRECTION('',(0.,1.,0.));
#510=VECTOR('',#509,1.);
#511=CARTESIAN_POINT('',(1.,0.,1.));
#512=LINE('',#511,#510);
#513=CARTESIAN_POINT('',(1.,1.,1.));
#514=VERTEX_POINT('',#513);
#515=EDGE_CURVE('E1047',#506,#514,#512,.T.);
#516=ORIENTED_EDGE('',*,*,#515,.T.);
#517=DIRECTION('',(-1.,0.,0.));
#518=VECTOR('',#517,1.);
#519=CARTESIAN_POINT('',(0.,1.,1.));
#520=LINE('',#519,#518);
#521=EDGE_CURVE('E1049',#514,#187,#520,.T.);
#522=ORIENTED_EDGE('',*,*,#521,.T.);
#523=EDGE_LOOP('',(#500,#508,#516,#522));
#524=FACE_BOUND('',#523,.T.);
#525=CARTESIAN_POINT('',(0.558539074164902,0.422946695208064,1.));
#526=CARTESIAN_POINT('',(0.558627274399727,0.424778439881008,1.));
#527=CARTESIAN_POINT('',(0.558799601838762,0.428357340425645,1.));
#528=CARTESIAN_POINT('',(0.560397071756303,0.433473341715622,1.));
#529=CARTESIAN_POINT('',(0.56286668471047,0.438195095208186,1.));
#530=CARTESIAN_POINT('',(0.566398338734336,0.442290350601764,1.));
#531=CARTESIAN_POINT('',(0.570557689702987,0.445731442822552,1.));
#532=CARTESIAN_POINT('',(0.575242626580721,0.448323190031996,1.));
#533=CARTESIAN_POINT('',(0.580403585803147,0.449797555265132,1.));
#534=CARTESIAN_POINT('',(0.583970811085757,0.449991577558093,1.));
#535=CARTESIAN_POINT('',(0.585782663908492,0.450090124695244,1.));
#536=B_SPLINE_CURVE_WITH_KNOTS('',3,(#525,#526,#527,#528,#529,#530,#531,#532,#533,#534,#535),
.UNSPECIFIED.,.F.,.F.,(4,1,1,1,1,1,1,1,4),(0.,0.128226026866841,0.250530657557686,
0.372638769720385,0.499833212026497,0.627178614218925,0.749841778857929,0.872940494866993,1.),.UNSPECIFIED.);
#537=CARTESIAN_POINT('',(0.558539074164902,0.422946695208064,1.));
#538=VERTEX_POINT('',#537);
#539=CARTESIAN_POINT('',(0.585782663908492,0.450090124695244,1.));
#540=VERTEX_POINT('',#539);
#541=EDGE_CURVE('E743',#538,#540,#536,.T.);
#542=ORIENTED_EDGE('',*,*,#541,.T.);
#543=CARTESIAN_POINT('',(0.585782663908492,0.450090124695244,1.));
#544=CARTESIAN_POINT('',(0.587594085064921,0.449990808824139,1.));
#545=CARTESIAN_POINT('',(0.59116046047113,0.449795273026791,1.));
#546=CARTESIAN_POINT('',(0.596313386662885,0.448336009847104,1.));
#547=CARTESIAN_POINT('',(0.600963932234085,0.445714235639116,1.));
#548=CARTESIAN_POINT('',(0.605122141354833,0.442294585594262,1.));
#549=CARTESIAN_POINT('',(0.608638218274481,0.438180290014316,1.));
#550=CARTESIAN_POINT('',(0.611179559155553,0.433488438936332,1.));
#551=CARTESIAN_POINT('',(0.612762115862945,0.428355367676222,1.));
#552=CARTESIAN_POINT('',(0.612936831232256,0.424777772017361,1.));
#553=CARTESIAN_POINT('',(0.613026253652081,0.422946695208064,1.));
#554=B_SPLINE_CURVE_WITH_KNOTS('',3,(#543,#544,#545,#546,#547,#548,#549,#550,#551,#552,#553),
.UNSPECIFIED.,.F.,.F.,(4,1,1,1,1,1,1,1,4),(0.,0.127119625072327,0.250276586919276,
0.371969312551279,0.499374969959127,0.626629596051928,0.749350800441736,0.871713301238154,1.),.UNSPECIFIED.);
#555=CARTESIAN_POINT('',(0.613026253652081,0.422946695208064,1.));
#556=VERTEX_POINT('',#555);
#557=EDGE_CURVE('E1275',#540,#556,#554,.T.);
#558=ORIENTED_EDGE('',*,*,#557,.T.);
#559=CARTESIAN_POINT('',(0.613026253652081,0.422946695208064,1.));
#560=CARTESIAN_POINT('',(0.612937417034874,0.421115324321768,1.));
#561=CARTESIAN_POINT('',(0.612763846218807,0.417537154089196,1.));
#562=CARTESIAN_POINT('',(0.611168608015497,0.412394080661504,1.));
#563=CARTESIAN_POINT('',(0.608642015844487,0.4076636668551,1.));
#564=CARTESIAN_POINT('',(0.605121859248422,0.403505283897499,1.));
#565=CARTESIAN_POINT('',(0.600981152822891,0.400021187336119,1.));
#566=CARTESIAN_POINT('',(0.59630269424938,0.397423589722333,1.));
#567=CARTESIAN_POINT('',(0.591170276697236,0.39588154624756,1.));
#568=CARTESIAN_POINT('',(0.587595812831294,0.395696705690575,1.));
#569=CARTESIAN_POINT('',(0.585782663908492,0.395602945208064,1.));
#570=B_SPLINE_CURVE_WITH_KNOTS('',3,(#559,#560,#561,#562,#563,#564,#565,#566,#567,#568,#569),
.UNSPECIFIED.,.F.,.F.,(4,1,1,1,1,1,1,1,4),(0.,0.12790236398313,0.249898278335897,
0.373279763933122,0.501048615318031,0.628817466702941,0.750145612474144,0.873261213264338,1.),.UNSPECIFIED.);
#571=CARTESIAN_POINT('',(0.585782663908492,0.395602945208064,1.));
#572=VERTEX_POINT('',#571);
#573=EDGE_CURVE('E1283',#556,#572,#570,.T.);
#574=ORIENTED_EDGE('',*,*,#573,.T.);
#575=CARTESIAN_POINT('',(0.585782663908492,0.395602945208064,1.));
#576=CARTESIAN_POINT('',(0.583969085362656,0.395695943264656,1.));
#577=CARTESIAN_POINT('',(0.580393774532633,0.395879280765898,1.));
#578=CARTESIAN_POINT('',(0.575253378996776,0.397436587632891,1.));
#579=CARTESIAN_POINT('',(0.570540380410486,0.400003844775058,1.));
#580=CARTESIAN_POINT('',(0.566398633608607,0.403509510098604,1.));
#581=CARTESIAN_POINT('',(0.562862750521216,0.407648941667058,1.));
#582=CARTESIAN_POINT('',(0.560407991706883,0.412409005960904,1.));
#583=CARTESIAN_POINT('',(0.558797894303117,0.417535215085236,1.));
#584=CARTESIAN_POINT('',(0.558626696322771,0.421114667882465,1.));
#585=CARTESIAN_POINT('',(0.558539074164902,0.422946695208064,1.));
#586=B_SPLINE_CURVE_WITH_KNOTS('',3,(#575,#576,#577,#578,#579,#580,#581,#582,#583,#584,#585),
.UNSPECIFIED.,.F.,.F.,(4,1,1,1,1,1,1,1,4),(0.,0.126678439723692,0.249735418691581,
0.372030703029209,0.49973871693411,0.627446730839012,0.750220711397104,0.872158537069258,1.),.UNSPECIFIED.);
#587=EDGE_CURVE('E751',#572,#538,#586,.T.);
#588=ORIENTED_EDGE('',*,*,#587,.T.);
#589=EDGE_LOOP('',(#542,#558,#574,#588));
#590=FACE_BOUND('',#589,.T.);
#591=CARTESIAN_POINT('',(0.750846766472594,0.422946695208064,1.));
#592=CARTESIAN_POINT('',(0.75093496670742,0.424778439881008,1.));
#593=CARTESIAN_POINT('',(0.751107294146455,0.428357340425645,1.));
#594=CARTESIAN_POINT('',(0.752704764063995,0.433473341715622,1.));
#595=CARTESIAN_POINT('',(0.755174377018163,0.438195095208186,1.));
#596=CARTESIAN_POINT('',(0.758706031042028,0.442290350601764,1.));
#597=CARTESIAN_POINT('',(0.76286538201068,0.445731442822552,1.));
#598=CARTESIAN_POINT('',(0.767550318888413,0.448323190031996,1.));
#599=CARTESIAN_POINT('',(0.772711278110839,0.449797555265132,1.));
#600=CARTESIAN_POINT('',(0.77627850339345,0.449991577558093,1.));
#601=CARTESIAN_POINT('',(0.778090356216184,0.450090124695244,1.));
#602=B_SPLINE_CURVE_WITH_KNOTS('',3,(#591,#592,#593,#594,#595,#596,#597,#598,#599,#600,#601),
.UNSPECIFIED.,.F.,.F.,(4,1,1,1,1,1,1,1,4),(0.,0.128226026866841,0.250530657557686,
0.372638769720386,0.499833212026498,0.627178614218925,0.749841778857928,0.872940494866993,1.),.UNSPECIFIED.);
#603=CARTESIAN_POINT('',(0.750846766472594,0.422946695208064,1.));
#604=VERTEX_POINT('',#603);
#605=CARTESIAN_POINT('',(0.778090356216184,0.450090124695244,1.));
#606=VERTEX_POINT('',#605);
#607=EDGE_CURVE('E650',#604,#606,#602,.T.);
#608=ORIENTED_EDGE('',*,*,#607,.T.);
#609=CARTESIAN_POINT('',(0.778090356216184,0.450090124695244,1.));
#610=CARTESIAN_POINT('',(0.779901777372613,0.449990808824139,1.));
#611=CARTESIAN_POINT('',(0.783468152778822,0.449795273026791,1.));
#612=CARTESIAN_POINT('',(0.788621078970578,0.448336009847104,1.));
#613=CARTESIAN_POINT('',(0.793271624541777,0.445714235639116,1.));
#614=CARTESIAN_POINT('',(0.797429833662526,0.442294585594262,1.));
#615=CARTESIAN_POINT('',(0.800945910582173,0.438180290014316,1.));
#616=CARTESIAN_POINT('',(0.803487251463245,0.433488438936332,1.));
#617=CARTESIAN_POINT('',(0.805069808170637,0.428355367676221,1.));
#618=CARTESIAN_POINT('',(0.805244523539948,0.424777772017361,1.));
#619=CARTESIAN_POINT('',(0.805333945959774,0.422946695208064,1.));
#620=B_SPLINE_CURVE_WITH_KNOTS('',3,(#609,#610,#611,#612,#613,#614,#615,#616,#617,#618,#619),
.UNSPECIFIED.,.F.,.F.,(4,1,1,1,1,1,1,1,4),(0.,0.12711962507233,0.250276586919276,
0.371969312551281,0.499374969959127,0.626629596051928,0.749350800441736,0.871713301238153,1.),.UNSPECIFIED.);
#621=CARTESIAN_POINT('',(0.805333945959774,0.422946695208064,1.));
#622=VERTEX_POINT('',#621);
#623=EDGE_CURVE('E1198',#606,#622,#620,.T.);
#624=ORIENTED_EDGE('',*,*,#623,.T.);
#625=CARTESIAN_POINT('',(0.805333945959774,0.422946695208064,1.));
#626=CARTESIAN_POINT('',(0.805245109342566,0.421115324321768,1.));
#627=CARTESIAN_POINT('',(0.805071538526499,0.417537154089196,1.));
#628=CARTESIAN_POINT('',(0.80347630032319,0.412394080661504,1.));
#629=CARTESIAN_POINT('',(0.800949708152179,0.4076636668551,1.));
#630=CARTESIAN_POINT('',(0.797429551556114,0.403505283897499,1.));
#631=CARTESIAN_POINT('',(0.793288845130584,0.400021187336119,1.));
#632=CARTESIAN_POINT('',(0.788610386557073,0.397423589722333,1.));
#633=CARTESIAN_POINT('',(0.783477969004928,0.39588154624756,1.));
#634=CARTESIAN_POINT('',(0.779903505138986,0.395696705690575,1.));
#635=CARTESIAN_POINT('',(0.778090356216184,0.395602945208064,1.));
#636=B_SPLINE_CURVE_WITH_KNOTS('',3,(#625,#626,#627,#628,#629,#630,#631,#632,#633,#634,#635),
.UNSPECIFIED.,.F.,.F.,(4,1,1,1,1,1,1,1,4),(0.,0.127902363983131,0.249898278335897,
0.373279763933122,0.501048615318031,0.628817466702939,0.750145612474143,0.873261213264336,1.),.UNSPECIFIED.);
#637=CARTESIAN_POINT('',(0.778090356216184,0.395602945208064,1.));
#638=VERTEX_POINT('',#637);
#639=EDGE_CURVE('E1206',#622,#638,#636,.T.);
#640=ORIENTED_EDGE('',*,*,#639,.T.);
#641=CARTESIAN_POINT('',(0.778090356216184,0.395602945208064,1.));
#642=CARTESIAN_POINT('',(0.776276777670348,0.395695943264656,1.));
#643=CARTESIAN_POINT('',(0.772701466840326,0.395879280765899,1.));
#644=CARTESIAN_POINT('',(0.767561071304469,0.397436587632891,1.));
#645=CARTESIAN_POINT('',(0.762848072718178,0.400003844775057,1.));
#646=CARTESIAN_POINT('',(0.7587063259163,0.403509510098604,1.));
#647=CARTESIAN_POINT('',(0.755170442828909,0.407648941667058,1.));
#648=CARTESIAN_POINT('',(0.752715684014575,0.412409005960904,1.));
#649=CARTESIAN_POINT('',(0.75110558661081,0.417535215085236,1.));
#650=CARTESIAN_POINT('',(0.750934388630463,0.421114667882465,1.));
#651=CARTESIAN_POINT('',(0.750846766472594,0.422946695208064,1.));
#652=B_SPLINE_CURVE_WITH_KNOTS('',3,(#641,#642,#643,#644,#645,#646,#647,#648,#649,#650,#651),
.UNSPECIFIED.,.F.,.F.,(4,1,1,1,1,1,1,1,4),(0.,0.126678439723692,0.249735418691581,
0.372030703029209,0.499738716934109,0.62744673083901,0.750220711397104,0.872158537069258,1.),.UNSPECIFIED.);
#653=EDGE_CURVE('E658',#638,#604,#652,.T.);
#654=ORIENTED_EDGE('',*,*,#653,.T.);
#655=EDGE_LOOP('',(#608,#624,#640,#654));
#656=FACE_BOUND('',#655,.T.);
#657=ADVANCED_FACE('F1085',(#401,#499,#524,#590,#656),#335,.F.);
#658=CARTESIAN_POINT('',(1.,0.,1.));
#659=DIRECTION('',(-1.,0.,0.));
#660=DIRECTION('',(0.,0.,1.));
#661=AXIS2_PLACEMENT_3D('',#658,#659,#660);
#662=PLANE('',#661);
#663=CARTESIAN_POINT('',(1.,0.440272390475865,0.437300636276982));
#664=CARTESIAN_POINT('',(1.,0.442104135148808,0.437212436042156));
#665=CARTESIAN_POINT('',(1.,0.445683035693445,0.437040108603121));
#666=CARTESIAN_POINT('',(1.,0.450799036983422,0.435442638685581));
#667=CARTESIAN_POINT('',(1.,0.455520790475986,0.432973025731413));
#668=CARTESIAN_POINT('',(1.,0.459616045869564,0.429441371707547));
#669=CARTESIAN_POINT('',(1.,0.463057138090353,0.425282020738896));
#670=CARTESIAN_POINT('',(1.,0.465648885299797,0.420597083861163));
#671=CARTESIAN_POINT('',(1.,0.467123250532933,0.415436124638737));
#672=CARTESIAN_POINT('',(1.,0.467317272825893,0.411868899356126));
#673=CARTESIAN_POINT('',(1.,0.467415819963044,0.410057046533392));
#674=B_SPLINE_CURVE_WITH_KNOTS('',3,(#663,#664,#665,#666,#667,#668,#669,#670,#671,#672,#673),
.UNSPECIFIED.,.F.,.F.,(4,1,1,1,1,1,1,1,4),(0.,0.128226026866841,0.250530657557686,
0.372638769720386,0.499833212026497,0.627178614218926,0.749841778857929,0.872940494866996,1.),.UNSPECIFIED.);
#675=CARTESIAN_POINT('',(1.,0.440272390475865,0.437300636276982));
#676=VERTEX_POINT('',#675);
#677=CARTESIAN_POINT('',(1.,0.467415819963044,0.410057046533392));
#678=VERTEX_POINT('',#677);
#679=EDGE_CURVE('E888',#676,#678,#674,.T.);
#680=ORIENTED_EDGE('',*,*,#679,.T.);
#681=CARTESIAN_POINT('',(1.,0.467415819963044,0.410057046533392));
#682=CARTESIAN_POINT('',(1.,0.467316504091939,0.408245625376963));
#683=CARTESIAN_POINT('',(1.,0.467120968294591,0.404679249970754));
#684=CARTESIAN_POINT('',(1.,0.465661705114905,0.399526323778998));
#685=CARTESIAN_POINT('',(1.,0.463039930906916,0.394875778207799));
#686=CARTESIAN_POINT('',(1.,0.459620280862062,0.39071756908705));
#687=CARTESIAN_POINT('',(1.,0.455505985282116,0.387201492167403));
#688=CARTESIAN_POINT('',(1.,0.450814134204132,0.384660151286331));
#689=CARTESIAN_POINT('',(1.,0.445681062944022,0.383077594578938));
#690=CARTESIAN_POINT('',(1.,0.442103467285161,0.382902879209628));
#691=CARTESIAN_POINT('',(1.,0.440272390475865,0.382813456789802));
#692=B_SPLINE_CURVE_WITH_KNOTS('',3,(#681,#682,#683,#684,#685,#686,#687,#688,#689,#690,#691),
.UNSPECIFIED.,.F.,.F.,(4,1,1,1,1,1,1,1,4),(0.,0.127119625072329,0.250276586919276,
0.37196931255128,0.499374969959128,0.626629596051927,0.749350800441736,0.871713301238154,1.),.UNSPECIFIED.);
#693=CARTESIAN_POINT('',(1.,0.440272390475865,0.382813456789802));
#694=VERTEX_POINT('',#693);
#695=EDGE_CURVE('E1439',#678,#694,#692,.T.);
#696=ORIENTED_EDGE('',*,*,#695,.T.);
#697=CARTESIAN_POINT('',(1.,0.440272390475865,0.382813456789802));
#698=CARTESIAN_POINT('',(1.,0.438441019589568,0.38290229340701));
#699=CARTESIAN_POINT('',(1.,0.434862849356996,0.383075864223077));
#700=CARTESIAN_POINT('',(1.,0.429719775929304,0.384671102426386));
#701=CARTESIAN_POINT('',(1.,0.4249893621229,0.387197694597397));
#702=CARTESIAN_POINT('',(1.,0.420830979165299,0.390717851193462));
#703=CARTESIAN_POINT('',(1.,0.417346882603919,0.394858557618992));
#704=CARTESIAN_POINT('',(1.,0.414749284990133,0.399537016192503));
#705=CARTESIAN_POINT('',(1.,0.41320724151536,0.404669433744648));
#706=CARTESIAN_POINT('',(1.,0.413022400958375,0.40824389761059));
#707=CARTESIAN_POINT('',(1.,0.412928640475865,0.410057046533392));
#708=B_SPLINE_CURVE_WITH_KNOTS('',3,(#697,#698,#699,#700,#701,#702,#703,#704,#705,#706,#707),
.UNSPECIFIED.,.F.,.F.,(4,1,1,1,1,1,1,1,4),(0.,0.127902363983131,0.249898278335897,
0.373279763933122,0.501048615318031,0.62881746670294,0.750145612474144,0.873261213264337,1.),.UNSPECIFIED.);
#709=CARTESIAN_POINT('',(1.,0.412928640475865,0.410057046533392));
#710=VERTEX_POINT('',#709);
#711=EDGE_CURVE('E1447',#694,#710,#708,.T.);
#712=ORIENTED_EDGE('',*,*,#711,.T.);
#713=CARTESIAN_POINT('',(1.,0.412928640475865,0.410057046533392));
#714=CARTESIAN_POINT('',(1.,0.413021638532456,0.411870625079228));
#715=CARTESIAN_POINT('',(1.,0.413204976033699,0.41544593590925));
#716=CARTESIAN_POINT('',(1.,0.414762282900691,0.420586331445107));
#717=CARTESIAN_POINT('',(1.,0.417329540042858,0.425299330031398));
#718=CARTESIAN_POINT('',(1.,0.420835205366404,0.429441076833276));
#719=CARTESIAN_POINT('',(1.,0.424974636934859,0.432976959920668));
#720=CARTESIAN_POINT('',(1.,0.429734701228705,0.435431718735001));
#721=CARTESIAN_POINT('',(1.,0.434860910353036,0.437041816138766));
#722=CARTESIAN_POINT('',(1.,0.438440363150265,0.437213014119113));
#723=CARTESIAN_POINT('',(1.,0.440272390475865,0.437300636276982));
#724=B_SPLINE_CURVE_WITH_KNOTS('',3,(#713,#714,#715,#716,#717,#718,#719,#720,#721,#722,#723),
.UNSPECIFIED.,.F.,.F.,(4,1,1,1,1,1,1,1,4),(0.,0.126678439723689,0.24973541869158,
0.372030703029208,0.49973871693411,0.627446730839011,0.750220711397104,0.872158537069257,1.),.UNSPECIFIED.);
#725=EDGE_CURVE('E896',#710,#676,#724,.T.);
#726=ORIENTED_EDGE('',*,*,#725,.T.);
#727=EDGE_LOOP('',(#680,#696,#712,#726));
#728=FACE_BOUND('',#727,.T.);
#729=DIRECTION('',(0.,1.,0.));
#730=VECTOR('',#729,1.);
#731=CARTESIAN_POINT('',(1.,0.621261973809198,0.709736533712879));
#732=LINE('',#731,#730);
#733=CARTESIAN_POINT('',(1.,0.621261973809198,0.709736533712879));
#734=VERTEX_POINT('',#733);
#735=CARTESIAN_POINT('',(1.,0.666133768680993,0.709736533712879));
#736=VERTEX_POINT('',#735);
#737=EDGE_CURVE('E981',#734,#736,#732,.T.);
#738=ORIENTED_EDGE('',*,*,#737,.T.);
#739=DIRECTION('',(0.,0.,-1.));
#740=VECTOR('',#739,1.);
#741=CARTESIAN_POINT('',(1.,0.666133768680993,0.709736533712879));
#742=LINE('',#741,#740);
#743=CARTESIAN_POINT('',(1.,0.666133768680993,0.559095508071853));
#744=VERTEX_POINT('',#743);
#745=EDGE_CURVE('E1003',#736,#744,#742,.T.);
#746=ORIENTED_EDGE('',*,*,#745,.T.);
#747=DIRECTION('',(0.,-0.91648568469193,0.400067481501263));
#748=VECTOR('',#747,1.);
#749=CARTESIAN_POINT('',(1.,0.666133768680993,0.559095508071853));
#750=LINE('',#749,#748);
#751=CARTESIAN_POINT('',(1.,0.461005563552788,0.648638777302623));
#752=VERTEX_POINT('',#751);
#753=EDGE_CURVE('E1006',#744,#752,#750,.T.);
#754=ORIENTED_EDGE('',*,*,#753,.T.);
#755=DIRECTION('',(0.,0.,-1.));
#756=VECTOR('',#755,1.);
#757=CARTESIAN_POINT('',(1.,0.461005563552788,0.648638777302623));
#758=LINE('',#757,#756);
#759=CARTESIAN_POINT('',(1.,0.461005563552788,0.56550576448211));
#760=VERTEX_POINT('',#759);
#761=EDGE_CURVE('E1009',#752,#760,#758,.T.);
#762=ORIENTED_EDGE('',*,*,#761,.T.);
#763=DIRECTION('',(0.,-1.,0.));
#764=VECTOR('',#763,1.);
#765=CARTESIAN_POINT('',(1.,0.461005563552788,0.56550576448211));
#766=LINE('',#765,#764);
#767=CARTESIAN_POINT('',(1.,0.416133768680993,0.56550576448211));
#768=VERTEX_POINT('',#767);
#769=EDGE_CURVE('E1012',#760,#768,#766,.T.);
#770=ORIENTED_EDGE('',*,*,#769,.T.);
#771=DIRECTION('',(0.,0.,1.));
#772=VECTOR('',#771,1.);
#773=CARTESIAN_POINT('',(1.,0.416133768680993,0.56550576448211));
#774=LINE('',#773,#772);
#775=CARTESIAN_POINT('',(1.,0.416133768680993,0.716146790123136));
#776=VERTEX_POINT('',#775);
#777=EDGE_CURVE('E1015',#768,#776,#774,.T.);
#778=ORIENTED_EDGE('',*,*,#777,.T.);
#779=DIRECTION('',(0.,0.916403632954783,-0.400255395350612));
#780=VECTOR('',#779,1.);
#781=CARTESIAN_POINT('',(1.,0.416133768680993,0.716146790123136));
#782=LINE('',#781,#780);
#783=CARTESIAN_POINT('',(1.,0.621261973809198,0.626553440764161));
#784=VERTEX_POINT('',#783);
#785=EDGE_CURVE('E1018',#776,#784,#782,.T.);
#786=ORIENTED_EDGE('',*,*,#785,.T.);
#787=DIRECTION('',(0.,0.,1.));
#788=VECTOR('',#787,1.);
#789=CARTESIAN_POINT('',(1.,0.621261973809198,0.626553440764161));
#790=LINE('',#789,#788);
#791=EDGE_CURVE('E986',#784,#734,#790,.T.);
#792=ORIENTED_EDGE('',*,*,#791,.T.);
#793=EDGE_LOOP('',(#738,#746,#754,#762,#770,#778,#786,#792));
#794=FACE_BOUND('',#793,.T.);
#795=DIRECTION('',(0.,1.,0.));
#796=VECTOR('',#795,1.);
#797=CARTESIAN_POINT('',(1.,0.,0.));
#798=LINE('',#797,#796);
#799=CARTESIAN_POINT('',(1.,0.,0.));
#800=VERTEX_POINT('',#799);
#801=CARTESIAN_POINT('',(1.,1.,0.));
#802=VERTEX_POINT('',#801);
#803=EDGE_CURVE('E1056',#800,#802,#798,.T.);
#804=ORIENTED_EDGE('',*,*,#803,.T.);
#805=DIRECTION('',(0.,0.,-1.));
#806=VECTOR('',#805,1.);
#807=CARTESIAN_POINT('',(1.,1.,1.));
#808=LINE('',#807,#806);
#809=EDGE_CURVE('E1061',#514,#802,#808,.T.);
#810=ORIENTED_EDGE('',*,*,#809,.F.);
#811=ORIENTED_EDGE('',*,*,#515,.F.);
#812=DIRECTION('',(0.,0.,-1.));
#813=VECTOR('',#812,1.);
#814=CARTESIAN_POINT('',(1.,0.,1.));
#815=LINE('',#814,#813);
#816=EDGE_CURVE('E40',#506,#800,#815,.T.);
#817=ORIENTED_EDGE('',*,*,#816,.T.);
#818=EDGE_LOOP('',(#804,#810,#811,#817));
#819=FACE_BOUND('',#818,.T.);
#820=CARTESIAN_POINT('',(1.,0.440272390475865,0.533454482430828));
#821=CARTESIAN_POINT('',(1.,0.442104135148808,0.533366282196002));
#822=CARTESIAN_POINT('',(1.,0.445683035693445,0.533193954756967));
#823=CARTESIAN_POINT('',(1.,0.450799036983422,0.531596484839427));
#824=CARTESIAN_POINT('',(1.,0.455520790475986,0.529126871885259));
#825=CARTESIAN_POINT('',(1.,0.459616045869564,0.525595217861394));
#826=CARTESIAN_POINT('',(1.,0.463057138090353,0.521435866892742));
#827=CARTESIAN_POINT('',(1.,0.465648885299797,0.516750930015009));
#828=CARTESIAN_POINT('',(1.,0.467123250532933,0.511589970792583));
#829=CARTESIAN_POINT('',(1.,0.467317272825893,0.508022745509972));
#830=CARTESIAN_POINT('',(1.,0.467415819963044,0.506210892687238));
#831=B_SPLINE_CURVE_WITH_KNOTS('',3,(#820,#821,#822,#823,#824,#825,#826,#827,#828,#829,#830),
.UNSPECIFIED.,.F.,.F.,(4,1,1,1,1,1,1,1,4),(0.,0.128226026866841,0.250530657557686,
0.372638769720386,0.499833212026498,0.627178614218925,0.749841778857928,0.872940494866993,1.),.UNSPECIFIED.);
#832=CARTESIAN_POINT('',(1.,0.440272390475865,0.533454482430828));
#833=VERTEX_POINT('',#832);
#834=CARTESIAN_POINT('',(1.,0.467415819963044,0.506210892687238));
#835=VERTEX_POINT('',#834);
#836=EDGE_CURVE('E935',#833,#835,#831,.T.);
#837=ORIENTED_EDGE('',*,*,#836,.T.);
#838=CARTESIAN_POINT('',(1.,0.467415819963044,0.506210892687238));
#839=CARTESIAN_POINT('',(1.,0.467316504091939,0.504399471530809));
#840=CARTESIAN_POINT('',(1.,0.467120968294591,0.5008330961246));
#841=CARTESIAN_POINT('',(1.,0.465661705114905,0.495680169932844));
#842=CARTESIAN_POINT('',(1.,0.463039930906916,0.491029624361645));
#843=CARTESIAN_POINT('',(1.,0.459620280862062,0.486871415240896));
#844=CARTESIAN_POINT('',(1.,0.455505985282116,0.483355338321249));
#845=CARTESIAN_POINT('',(1.,0.450814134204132,0.480813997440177));
#846=CARTESIAN_POINT('',(1.,0.445681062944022,0.479231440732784));
#847=CARTESIAN_POINT('',(1.,0.442103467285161,0.479056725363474));
#848=CARTESIAN_POINT('',(1.,0.440272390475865,0.478967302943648));
#849=B_SPLINE_CURVE_WITH_KNOTS('',3,(#838,#839,#840,#841,#842,#843,#844,#845,#846,#847,#848),
.UNSPECIFIED.,.F.,.F.,(4,1,1,1,1,1,1,1,4),(0.,0.127119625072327,0.250276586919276,
0.371969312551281,0.499374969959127,0.626629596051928,0.749350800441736,0.871713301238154,1.),.UNSPECIFIED.);
#850=CARTESIAN_POINT('',(1.,0.440272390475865,0.478967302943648));
#851=VERTEX_POINT('',#850);
#852=EDGE_CURVE('E943',#835,#851,#849,.T.);
#853=ORIENTED_EDGE('',*,*,#852,.T.);
#854=CARTESIAN_POINT('',(1.,0.440272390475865,0.478967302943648));
#855=CARTESIAN_POINT('',(1.,0.438441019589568,0.479056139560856));
#856=CARTESIAN_POINT('',(1.,0.434862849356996,0.479229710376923));
#857=CARTESIAN_POINT('',(1.,0.429719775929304,0.480824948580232));
#858=CARTESIAN_POINT('',(1.,0.4249893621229,0.483351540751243));
#859=CARTESIAN_POINT('',(1.,0.420830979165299,0.486871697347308));
#860=CARTESIAN_POINT('',(1.,0.417346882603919,0.491012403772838));
#861=CARTESIAN_POINT('',(1.,0.414749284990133,0.495690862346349));
#862=CARTESIAN_POINT('',(1.,0.41320724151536,0.500823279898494));
#863=CARTESIAN_POINT('',(1.,0.413022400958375,0.504397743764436));
#864=CARTESIAN_POINT('',(1.,0.412928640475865,0.506210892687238));
#865=B_SPLINE_CURVE_WITH_KNOTS('',3,(#854,#855,#856,#857,#858,#859,#860,#861,#862,#863,#864),
.UNSPECIFIED.,.F.,.F.,(4,1,1,1,1,1,1,1,4),(0.,0.12790236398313,0.249898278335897,
0.373279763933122,0.501048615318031,0.628817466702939,0.750145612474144,0.873261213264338,1.),.UNSPECIFIED.);
#866=CARTESIAN_POINT('',(1.,0.412928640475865,0.506210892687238));
#867=VERTEX_POINT('',#866);
#868=EDGE_CURVE('E952',#851,#867,#865,.T.);
#869=ORIENTED_EDGE('',*,*,#868,.T.);
#870=CARTESIAN_POINT('',(1.,0.412928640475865,0.506210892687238));
#871=CARTESIAN_POINT('',(1.,0.413021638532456,0.508024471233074));
#872=CARTESIAN_POINT('',(1.,0.413204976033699,0.511599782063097));
#873=CARTESIAN_POINT('',(1.,0.414762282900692,0.516740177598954));
#874=CARTESIAN_POINT('',(1.,0.417329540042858,0.521453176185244));
#875=CARTESIAN_POINT('',(1.,0.420835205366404,0.525594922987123));
#876=CARTESIAN_POINT('',(1.,0.424974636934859,0.529130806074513));
#877=CARTESIAN_POINT('',(1.,0.429734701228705,0.531585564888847));
#878=CARTESIAN_POINT('',(1.,0.434860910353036,0.533195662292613));
#879=CARTESIAN_POINT('',(1.,0.438440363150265,0.533366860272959));
#880=CARTESIAN_POINT('',(1.,0.440272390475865,0.533454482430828));
#881=B_SPLINE_CURVE_WITH_KNOTS('',3,(#870,#871,#872,#873,#874,#875,#876,#877,#878,#879,#880),
.UNSPECIFIED.,.F.,.F.,(4,1,1,1,1,1,1,1,4),(0.,0.126678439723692,0.249735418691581,
0.372030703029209,0.499738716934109,0.62744673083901,0.750220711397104,0.872158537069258,1.),.UNSPECIFIED.);
#882=EDGE_CURVE('E960',#867,#833,#881,.T.);
#883=ORIENTED_EDGE('',*,*,#882,.T.);
#884=EDGE_LOOP('',(#837,#853,#869,#883));
#885=FACE_BOUND('',#884,.T.);
#886=CARTESIAN_POINT('',(1.,0.440272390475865,0.341146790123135));
#887=CARTESIAN_POINT('',(1.,0.442104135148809,0.34105858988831));
#888=CARTESIAN_POINT('',(1.,0.445683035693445,0.340886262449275));
#889=CARTESIAN_POINT('',(1.,0.450799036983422,0.339288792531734));
#890=CARTESIAN_POINT('',(1.,0.455520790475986,0.336819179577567));
#891=CARTESIAN_POINT('',(1.,0.459616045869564,0.333287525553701));
#892=CARTESIAN_POINT('',(1.,0.463057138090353,0.32912817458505));
#893=CARTESIAN_POINT('',(1.,0.465648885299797,0.324443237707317));
#894=CARTESIAN_POINT('',(1.,0.467123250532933,0.31928227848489));
#895=CARTESIAN_POINT('',(1.,0.467317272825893,0.31571505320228));
#896=CARTESIAN_POINT('',(1.,0.467415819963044,0.313903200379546));
#897=B_SPLINE_CURVE_WITH_KNOTS('',3,(#886,#887,#888,#889,#890,#891,#892,#893,#894,#895,#896),
.UNSPECIFIED.,.F.,.F.,(4,1,1,1,1,1,1,1,4),(0.,0.128226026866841,0.250530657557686,
0.372638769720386,0.499833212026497,0.627178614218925,0.749841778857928,0.872940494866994,1.),.UNSPECIFIED.);
#898=CARTESIAN_POINT('',(1.,0.440272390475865,0.341146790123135));
#899=VERTEX_POINT('',#898);
#900=CARTESIAN_POINT('',(1.,0.467415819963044,0.313903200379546));
#901=VERTEX_POINT('',#900);
#902=EDGE_CURVE('E842',#899,#901,#897,.T.);
#903=ORIENTED_EDGE('',*,*,#902,.T.);
#904=CARTESIAN_POINT('',(1.,0.467415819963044,0.313903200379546));
#905=CARTESIAN_POINT('',(1.,0.467316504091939,0.312091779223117));
#906=CARTESIAN_POINT('',(1.,0.467120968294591,0.308525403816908));
#907=CARTESIAN_POINT('',(1.,0.465661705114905,0.303372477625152));
#908=CARTESIAN_POINT('',(1.,0.463039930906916,0.298721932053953));
#909=CARTESIAN_POINT('',(1.,0.459620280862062,0.294563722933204));
#910=CARTESIAN_POINT('',(1.,0.455505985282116,0.291047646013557));
#911=CARTESIAN_POINT('',(1.,0.450814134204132,0.288506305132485));
#912=CARTESIAN_POINT('',(1.,0.445681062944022,0.286923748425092));
#913=CARTESIAN_POINT('',(1.,0.442103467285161,0.286749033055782));
#914=CARTESIAN_POINT('',(1.,0.440272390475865,0.286659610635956));
#915=B_SPLINE_CURVE_WITH_KNOTS('',3,(#904,#905,#906,#907,#908,#909,#910,#911,#912,#913,#914),
.UNSPECIFIED.,.F.,.F.,(4,1,1,1,1,1,1,1,4),(0.,0.127119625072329,0.250276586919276,
0.37196931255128,0.499374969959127,0.626629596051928,0.749350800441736,0.871713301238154,1.),.UNSPECIFIED.);
#916=CARTESIAN_POINT('',(1.,0.440272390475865,0.286659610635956));
#917=VERTEX_POINT('',#916);
#918=EDGE_CURVE('E850',#901,#917,#915,.T.);
#919=ORIENTED_EDGE('',*,*,#918,.T.);
#920=CARTESIAN_POINT('',(1.,0.440272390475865,0.286659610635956));
#921=CARTESIAN_POINT('',(1.,0.438441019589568,0.286748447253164));
#922=CARTESIAN_POINT('',(1.,0.434862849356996,0.28692201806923));
#923=CARTESIAN_POINT('',(1.,0.429719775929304,0.28851725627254));
#924=CARTESIAN_POINT('',(1.,0.4249893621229,0.291043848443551));
#925=CARTESIAN_POINT('',(1.,0.420830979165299,0.294564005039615));
#926=CARTESIAN_POINT('',(1.,0.417346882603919,0.298704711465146));
#927=CARTESIAN_POINT('',(1.,0.414749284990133,0.303383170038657));
#928=CARTESIAN_POINT('',(1.,0.41320724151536,0.308515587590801));
#929=CARTESIAN_POINT('',(1.,0.413022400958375,0.312090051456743));
#930=CARTESIAN_POINT('',(1.,0.412928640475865,0.313903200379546));
#931=B_SPLINE_CURVE_WITH_KNOTS('',3,(#920,#921,#922,#923,#924,#925,#926,#927,#928,#929,#930),
.UNSPECIFIED.,.F.,.F.,(4,1,1,1,1,1,1,1,4),(0.,0.12790236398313,0.249898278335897,
0.373279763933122,0.501048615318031,0.62881746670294,0.750145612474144,0.873261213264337,1.),.UNSPECIFIED.);
#932=CARTESIAN_POINT('',(1.,0.412928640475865,0.313903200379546));
#933=VERTEX_POINT('',#932);
#934=EDGE_CURVE('E859',#917,#933,#931,.T.);
#935=ORIENTED_EDGE('',*,*,#934,.T.);
#936=CARTESIAN_POINT('',(1.,0.412928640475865,0.313903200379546));
#937=CARTESIAN_POINT('',(1.,0.413021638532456,0.315716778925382));
#938=CARTESIAN_POINT('',(1.,0.413204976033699,0.319292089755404));
#939=CARTESIAN_POINT('',(1.,0.414762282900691,0.324432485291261));
#940=CARTESIAN_POINT('',(1.,0.417329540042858,0.329145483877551));
#941=CARTESIAN_POINT('',(1.,0.420835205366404,0.33328723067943));
#942=CARTESIAN_POINT('',(1.,0.424974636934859,0.336823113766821));
#943=CARTESIAN_POINT('',(1.,0.429734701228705,0.339277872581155));
#944=CARTESIAN_POINT('',(1.,0.434860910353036,0.34088796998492));
#945=CARTESIAN_POINT('',(1.,0.438440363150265,0.341059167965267));
#946=CARTESIAN_POINT('',(1.,0.440272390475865,0.341146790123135));
#947=B_SPLINE_CURVE_WITH_KNOTS('',3,(#936,#937,#938,#939,#940,#941,#942,#943,#944,#945,#946),
.UNSPECIFIED.,.F.,.F.,(4,1,1,1,1,1,1,1,4),(0.,0.126678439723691,0.249735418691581,
0.372030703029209,0.49973871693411,0.627446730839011,0.750220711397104,0.872158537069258,1.),.UNSPECIFIED.);
#948=EDGE_CURVE('E867',#933,#899,#947,.T.);
#949=ORIENTED_EDGE('',*,*,#948,.T.);
#950=EDGE_LOOP('',(#903,#919,#935,#949));
#951=FACE_BOUND('',#950,.T.);
#952=ADVANCED_FACE('F1068',(#728,#794,#819,#885,#951),#662,.F.);
#953=CARTESIAN_POINT('',(0.,0.,1.));
#954=DIRECTION('',(0.,1.,0.));
#955=DIRECTION('',(0.,0.,1.));
#956=AXIS2_PLACEMENT_3D('',#953,#954,#955);
#957=PLANE('',#956);
#958=DIRECTION('',(1.,0.,0.));
#959=VECTOR('',#958,1.);
#960=CARTESIAN_POINT('',(0.,0.,0.));
#961=LINE('',#960,#959);
#962=EDGE_CURVE('E1054',#171,#800,#961,.T.);
#963=ORIENTED_EDGE('',*,*,#962,.T.);
#964=ORIENTED_EDGE('',*,*,#816,.F.);
#965=ORIENTED_EDGE('',*,*,#507,.F.);
#966=ORIENTED_EDGE('',*,*,#180,.T.);
#967=EDGE_LOOP('',(#963,#964,#965,#966));
#968=FACE_BOUND('',#967,.T.);
#969=ADVANCED_FACE('F1087',(#968),#957,.F.);
#970=CARTESIAN_POINT('',(0.,1.,1.));
#971=DIRECTION('',(0.,-1.,0.));
#972=DIRECTION('',(0.,0.,-1.));
#973=AXIS2_PLACEMENT_3D('',#970,#971,#972);
#974=PLANE('',#973);
#975=DIRECTION('',(-1.,0.,0.));
#976=VECTOR('',#975,1.);
#977=CARTESIAN_POINT('',(0.,1.,0.));
#978=LINE('',#977,#976);
#979=EDGE_CURVE('E1045',#802,#169,#978,.T.);
#980=ORIENTED_EDGE('',*,*,#979,.T.);
#981=ORIENTED_EDGE('',*,*,#194,.F.);
#982=ORIENTED_EDGE('',*,*,#521,.F.);
#983=ORIENTED_EDGE('',*,*,#809,.T.);
#984=EDGE_LOOP('',(#980,#981,#982,#983));
#985=FACE_BOUND('',#984,.T.);
#986=ADVANCED_FACE('F1078',(#985),#974,.F.);
#987=CARTESIAN_POINT('',(0.,0.,0.));
#988=DIRECTION('',(0.,0.,-1.));
#989=DIRECTION('',(-1.,0.,0.));
#990=AXIS2_PLACEMENT_3D('',#987,#988,#989);
#991=PLANE('',#990);
#992=ORIENTED_EDGE('',*,*,#172,.F.);
#993=ORIENTED_EDGE('',*,*,#979,.F.);
#994=ORIENTED_EDGE('',*,*,#803,.F.);
#995=ORIENTED_EDGE('',*,*,#962,.F.);
#996=EDGE_LOOP('',(#992,#993,#994,#995));
#997=FACE_BOUND('',#996,.T.);
#998=ADVANCED_FACE('F1075',(#997),#991,.T.);
#999=CARTESIAN_POINT('',(0.95,0.621261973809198,0.709736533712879));
#1000=DIRECTION('',(0.,0.,-1.));
#1001=DIRECTION('',(-1.,0.,0.));
#1002=AXIS2_PLACEMENT_3D('',#999,#1000,#1001);
#1003=PLANE('',#1002);
#1004=ORIENTED_EDGE('',*,*,#737,.F.);
#1005=DIRECTION('',(1.,0.,0.));
#1006=VECTOR('',#1005,1.);
#1007=CARTESIAN_POINT('',(0.95,0.621261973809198,0.709736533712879));
#1008=LINE('',#1007,#1006);
#1009=CARTESIAN_POINT('',(0.95,0.621261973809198,0.709736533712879));
#1010=VERTEX_POINT('',#1009);
#1011=EDGE_CURVE('E1000',#1010,#734,#1008,.T.);
#1012=ORIENTED_EDGE('',*,*,#1011,.F.);
#1013=DIRECTION('',(0.,1.,0.));
#1014=VECTOR('',#1013,1.);
#1015=CARTESIAN_POINT('',(0.95,0.621261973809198,0.709736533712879));
#1016=LINE('',#1015,#1014);
#1017=CARTESIAN_POINT('',(0.95,0.666133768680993,0.709736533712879));
#1018=VERTEX_POINT('',#1017);
#1019=EDGE_CURVE('E982',#1010,#1018,#1016,.T.);
#1020=ORIENTED_EDGE('',*,*,#1019,.T.);
#1021=DIRECTION('',(1.,0.,0.));
#1022=VECTOR('',#1021,1.);
#1023=CARTESIAN_POINT('',(0.95,0.666133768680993,0.709736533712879));
#1024=LINE('',#1023,#1022);
#1025=EDGE_CURVE('E1037',#1018,#736,#1024,.T.);
#1026=ORIENTED_EDGE('',*,*,#1025,.T.);
#1027=EDGE_LOOP('',(#1004,#1012,#1020,#1026));
#1028=FACE_BOUND('',#1027,.T.);
#1029=ADVANCED_FACE('F1521',(#1028),#1003,.T.);
#1030=CARTESIAN_POINT('',(0.95,0.666133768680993,0.709736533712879));
#1031=DIRECTION('',(0.,-1.,0.));
#1032=DIRECTION('',(0.,0.,-1.));
#1033=AXIS2_PLACEMENT_3D('',#1030,#1031,#1032);
#1034=PLANE('',#1033);
#1035=ORIENTED_EDGE('',*,*,#745,.F.);
#1036=ORIENTED_EDGE('',*,*,#1025,.F.);
#1037=DIRECTION('',(0.,0.,-1.));
#1038=VECTOR('',#1037,1.);
#1039=CARTESIAN_POINT('',(0.95,0.666133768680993,0.709736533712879));
#1040=LINE('',#1039,#1038);
#1041=CARTESIAN_POINT('',(0.95,0.666133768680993,0.559095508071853));
#1042=VERTEX_POINT('',#1041);
#1043=EDGE_CURVE('E985',#1018,#1042,#1040,.T.);
#1044=ORIENTED_EDGE('',*,*,#1043,.T.);
#1045=DIRECTION('',(1.,0.,0.));
#1046=VECTOR('',#1045,1.);
#1047=CARTESIAN_POINT('',(0.95,0.666133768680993,0.559095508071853));
#1048=LINE('',#1047,#1046);
#1049=EDGE_CURVE('E1035',#1042,#744,#1048,.T.);
#1050=ORIENTED_EDGE('',*,*,#1049,.T.);
#1051=EDGE_LOOP('',(#1035,#1036,#1044,#1050));
#1052=FACE_BOUND('',#1051,.T.);
#1053=ADVANCED_FACE('F1517',(#1052),#1034,.T.);
#1054=CARTESIAN_POINT('',(0.95,0.666133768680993,0.559095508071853));
#1055=DIRECTION('',(0.,0.400067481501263,0.91648568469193));
#1056=DIRECTION('',(0.,-0.91648568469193,0.400067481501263));
#1057=AXIS2_PLACEMENT_3D('',#1054,#1055,#1056);
#1058=PLANE('',#1057);
#1059=ORIENTED_EDGE('',*,*,#753,.F.);
#1060=ORIENTED_EDGE('',*,*,#1049,.F.);
#1061=DIRECTION('',(0.,-0.91648568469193,0.400067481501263));
#1062=VECTOR('',#1061,1.);
#1063=CARTESIAN_POINT('',(0.95,0.666133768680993,0.559095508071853));
#1064=LINE('',#1063,#1062);
#1065=CARTESIAN_POINT('',(0.95,0.461005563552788,0.648638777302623));
#1066=VERTEX_POINT('',#1065);
#1067=EDGE_CURVE('E988',#1042,#1066,#1064,.T.);
#1068=ORIENTED_EDGE('',*,*,#1067,.T.);
#1069=DIRECTION('',(1.,0.,0.));
#1070=VECTOR('',#1069,1.);
#1071=CARTESIAN_POINT('',(0.95,0.461005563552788,0.648638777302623));
#1072=LINE('',#1071,#1070);
#1073=EDGE_CURVE('E1033',#1066,#752,#1072,.T.);
#1074=ORIENTED_EDGE('',*,*,#1073,.T.);
#1075=EDGE_LOOP('',(#1059,#1060,#1068,#1074));
#1076=FACE_BOUND('',#1075,.T.);
#1077=ADVANCED_FACE('F1513',(#1076),#1058,.T.);
#1078=CARTESIAN_POINT('',(0.95,0.461005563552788,0.648638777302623));
#1079=DIRECTION('',(0.,-1.,0.));
#1080=DIRECTION('',(0.,0.,-1.));
#1081=AXIS2_PLACEMENT_3D('',#1078,#1079,#1080);
#1082=PLANE('',#1081);
#1083=ORIENTED_EDGE('',*,*,#761,.F.);
#1084=ORIENTED_EDGE('',*,*,#1073,.F.);
#1085=DIRECTION('',(0.,0.,-1.));
#1086=VECTOR('',#1085,1.);
#1087=CARTESIAN_POINT('',(0.95,0.461005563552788,0.648638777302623));
#1088=LINE('',#1087,#1086);
#1089=CARTESIAN_POINT('',(0.95,0.461005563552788,0.56550576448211));
#1090=VERTEX_POINT('',#1089);
#1091=EDGE_CURVE('E990',#1066,#1090,#1088,.T.);
#1092=ORIENTED_EDGE('',*,*,#1091,.T.);
#1093=DIRECTION('',(1.,0.,0.));
#1094=VECTOR('',#1093,1.);
#1095=CARTESIAN_POINT('',(0.95,0.461005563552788,0.56550576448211));
#1096=LINE('',#1095,#1094);
#1097=EDGE_CURVE('E1031',#1090,#760,#1096,.T.);
#1098=ORIENTED_EDGE('',*,*,#1097,.T.);
#1099=EDGE_LOOP('',(#1083,#1084,#1092,#1098));
#1100=FACE_BOUND('',#1099,.T.);
#1101=ADVANCED_FACE('F1509',(#1100),#1082,.T.);
#1102=CARTESIAN_POINT('',(0.95,0.461005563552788,0.56550576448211));
#1103=DIRECTION('',(0.,0.,1.));
#1104=DIRECTION('',(1.,0.,0.));
#1105=AXIS2_PLACEMENT_3D('',#1102,#1103,#1104);
#1106=PLANE('',#1105);
#1107=ORIENTED_EDGE('',*,*,#769,.F.);
#1108=ORIENTED_EDGE('',*,*,#1097,.F.);
#1109=DIRECTION('',(0.,-1.,0.));
#1110=VECTOR('',#1109,1.);
#1111=CARTESIAN_POINT('',(0.95,0.461005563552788,0.56550576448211));
#1112=LINE('',#1111,#1110);
#1113=CARTESIAN_POINT('',(0.95,0.416133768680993,0.56550576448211));
#1114=VERTEX_POINT('',#1113);
#1115=EDGE_CURVE('E992',#1090,#1114,#1112,.T.);
#1116=ORIENTED_EDGE('',*,*,#1115,.T.);
#1117=DIRECTION('',(1.,0.,0.));
#1118=VECTOR('',#1117,1.);
#1119=CARTESIAN_POINT('',(0.95,0.416133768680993,0.56550576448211));
#1120=LINE('',#1119,#1118);
#1121=EDGE_CURVE('E1029',#1114,#768,#1120,.T.);
#1122=ORIENTED_EDGE('',*,*,#1121,.T.);
#1123=EDGE_LOOP('',(#1107,#1108,#1116,#1122));
#1124=FACE_BOUND('',#1123,.T.);
#1125=ADVANCED_FACE('F1505',(#1124),#1106,.T.);
#1126=CARTESIAN_POINT('',(0.95,0.416133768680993,0.56550576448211));
#1127=DIRECTION('',(0.,1.,0.));
#1128=DIRECTION('',(0.,0.,1.));
#1129=AXIS2_PLACEMENT_3D('',#1126,#1127,#1128);
#1130=PLANE('',#1129);
#1131=ORIENTED_EDGE('',*,*,#777,.F.);
#1132=ORIENTED_EDGE('',*,*,#1121,.F.);
#1133=DIRECTION('',(0.,0.,1.));
#1134=VECTOR('',#1133,1.);
#1135=CARTESIAN_POINT('',(0.95,0.416133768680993,0.56550576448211));
#1136=LINE('',#1135,#1134);
#1137=CARTESIAN_POINT('',(0.95,0.416133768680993,0.716146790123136));
#1138=VERTEX_POINT('',#1137);
#1139=EDGE_CURVE('E994',#1114,#1138,#1136,.T.);
#1140=ORIENTED_EDGE('',*,*,#1139,.T.);
#1141=DIRECTION('',(1.,0.,0.));
#1142=VECTOR('',#1141,1.);
#1143=CARTESIAN_POINT('',(0.95,0.416133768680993,0.716146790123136));
#1144=LINE('',#1143,#1142);
#1145=EDGE_CURVE('E1027',#1138,#776,#1144,.T.);
#1146=ORIENTED_EDGE('',*,*,#1145,.T.);
#1147=EDGE_LOOP('',(#1131,#1132,#1140,#1146));
#1148=FACE_BOUND('',#1147,.T.);
#1149=ADVANCED_FACE('F1501',(#1148),#1130,.T.);
#1150=CARTESIAN_POINT('',(0.95,0.416133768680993,0.716146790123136));
#1151=DIRECTION('',(0.,-0.400255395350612,-0.916403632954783));
#1152=DIRECTION('',(0.,0.916403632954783,-0.400255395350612));
#1153=AXIS2_PLACEMENT_3D('',#1150,#1151,#1152);
#1154=PLANE('',#1153);
#1155=ORIENTED_EDGE('',*,*,#785,.F.);
#1156=ORIENTED_EDGE('',*,*,#1145,.F.);
#1157=DIRECTION('',(0.,0.916403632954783,-0.400255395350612));
#1158=VECTOR('',#1157,1.);
#1159=CARTESIAN_POINT('',(0.95,0.416133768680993,0.716146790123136));
#1160=LINE('',#1159,#1158);
#1161=CARTESIAN_POINT('',(0.95,0.621261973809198,0.626553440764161));
#1162=VERTEX_POINT('',#1161);
#1163=EDGE_CURVE('E996',#1138,#1162,#1160,.T.);
#1164=ORIENTED_EDGE('',*,*,#1163,.T.);
#1165=DIRECTION('',(1.,0.,0.));
#1166=VECTOR('',#1165,1.);
#1167=CARTESIAN_POINT('',(0.95,0.621261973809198,0.626553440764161));
#1168=LINE('',#1167,#1166);
#1169=EDGE_CURVE('E1025',#1162,#784,#1168,.T.);
#1170=ORIENTED_EDGE('',*,*,#1169,.T.);
#1171=EDGE_LOOP('',(#1155,#1156,#1164,#1170));
#1172=FACE_BOUND('',#1171,.T.);
#1173=ADVANCED_FACE('F1497',(#1172),#1154,.T.);
#1174=CARTESIAN_POINT('',(0.95,0.621261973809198,0.626553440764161));
#1175=DIRECTION('',(0.,1.,0.));
#1176=DIRECTION('',(0.,0.,1.));
#1177=AXIS2_PLACEMENT_3D('',#1174,#1175,#1176);
#1178=PLANE('',#1177);
#1179=ORIENTED_EDGE('',*,*,#791,.F.);
#1180=ORIENTED_EDGE('',*,*,#1169,.F.);
#1181=DIRECTION('',(0.,0.,1.));
#1182=VECTOR('',#1181,1.);
#1183=CARTESIAN_POINT('',(0.95,0.621261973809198,0.626553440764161));
#1184=LINE('',#1183,#1182);
#1185=EDGE_CURVE('E998',#1162,#1010,#1184,.T.);
#1186=ORIENTED_EDGE('',*,*,#1185,.T.);
#1187=ORIENTED_EDGE('',*,*,#1011,.T.);
#1188=EDGE_LOOP('',(#1179,#1180,#1186,#1187));
#1189=FACE_BOUND('',#1188,.T.);
#1190=ADVANCED_FACE('F1493',(#1189),#1178,.T.);
#1191=CARTESIAN_POINT('',(0.95,0.,0.));
#1192=DIRECTION('',(-1.,0.,0.));
#1193=DIRECTION('',(0.,0.,1.));
#1194=AXIS2_PLACEMENT_3D('',#1191,#1192,#1193);
#1195=PLANE('',#1194);
#1196=ORIENTED_EDGE('',*,*,#1019,.F.);
#1197=ORIENTED_EDGE('',*,*,#1185,.F.);
#1198=ORIENTED_EDGE('',*,*,#1163,.F.);
#1199=ORIENTED_EDGE('',*,*,#1139,.F.);
#1200=ORIENTED_EDGE('',*,*,#1115,.F.);
#1201=ORIENTED_EDGE('',*,*,#1091,.F.);
#1202=ORIENTED_EDGE('',*,*,#1067,.F.);
#1203=ORIENTED_EDGE('',*,*,#1043,.F.);
#1204=EDGE_LOOP('',(#1196,#1197,#1198,#1199,#1200,#1201,#1202,#1203));
#1205=FACE_BOUND('',#1204,.T.);
#1206=ADVANCED_FACE('F1489',(#1205),#1195,.F.);
#1207=CARTESIAN_POINT('',(0.95,0.440272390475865,0.533454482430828));
#1208=CARTESIAN_POINT('',(0.95,0.442104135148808,0.533366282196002));
#1209=CARTESIAN_POINT('',(0.95,0.445683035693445,0.533193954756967));
#1210=CARTESIAN_POINT('',(0.95,0.450799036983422,0.531596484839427));
#1211=CARTESIAN_POINT('',(0.95,0.455520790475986,0.529126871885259));
#1212=CARTESIAN_POINT('',(0.95,0.459616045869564,0.525595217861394));
#1213=CARTESIAN_POINT('',(0.95,0.463057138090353,0.521435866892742));
#1214=CARTESIAN_POINT('',(0.95,0.465648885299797,0.516750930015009));
#1215=CARTESIAN_POINT('',(0.95,0.467123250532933,0.511589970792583));
#1216=CARTESIAN_POINT('',(0.95,0.467317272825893,0.508022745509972));
#1217=CARTESIAN_POINT('',(0.95,0.467415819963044,0.506210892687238));
#1218=B_SPLINE_CURVE_WITH_KNOTS('',3,(#1207,#1208,#1209,#1210,#1211,#1212,#1213,#1214,#1215,
#1216,#1217),.UNSPECIFIED.,.F.,.F.,(4,1,1,1,1,1,1,1,4),(0.,0.128226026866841,0.250530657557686,
0.372638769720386,0.499833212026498,0.627178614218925,0.749841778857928,0.872940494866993,1.),.UNSPECIFIED.);
#1219=DIRECTION('',(1.,0.,0.));
#1220=VECTOR('',#1219,1.);
#1221=SURFACE_OF_LINEAR_EXTRUSION('',#1218,#1220);
#1222=ORIENTED_EDGE('',*,*,#836,.F.);
#1223=DIRECTION('',(1.,0.,0.));
#1224=VECTOR('',#1223,1.);
#1225=CARTESIAN_POINT('',(0.95,0.440272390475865,0.533454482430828));
#1226=LINE('',#1225,#1224);
#1227=CARTESIAN_POINT('',(0.95,0.440272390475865,0.533454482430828));
#1228=VERTEX_POINT('',#1227);
#1229=EDGE_CURVE('E929',#1228,#833,#1226,.T.);
#1230=ORIENTED_EDGE('',*,*,#1229,.F.);
#1231=CARTESIAN_POINT('',(0.95,0.467415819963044,0.506210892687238));
#1232=VERTEX_POINT('',#1231);
#1233=EDGE_CURVE('E968',#1228,#1232,#1218,.T.);
#1234=ORIENTED_EDGE('',*,*,#1233,.T.);
#1235=DIRECTION('',(1.,0.,0.));
#1236=VECTOR('',#1235,1.);
#1237=CARTESIAN_POINT('',(0.95,0.467415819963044,0.506210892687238));
#1238=LINE('',#1237,#1236);
#1239=EDGE_CURVE('E978',#1232,#835,#1238,.T.);
#1240=ORIENTED_EDGE('',*,*,#1239,.T.);
#1241=EDGE_LOOP('',(#1222,#1230,#1234,#1240));
#1242=FACE_BOUND('',#1241,.T.);
#1243=ADVANCED_FACE('F1485',(#1242),#1221,.T.);
#1244=CARTESIAN_POINT('',(0.95,0.467415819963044,0.506210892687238));
#1245=CARTESIAN_POINT('',(0.95,0.467316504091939,0.504399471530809));
#1246=CARTESIAN_POINT('',(0.95,0.467120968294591,0.5008330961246));
#1247=CARTESIAN_POINT('',(0.95,0.465661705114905,0.495680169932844));
#1248=CARTESIAN_POINT('',(0.95,0.463039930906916,0.491029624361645));
#1249=CARTESIAN_POINT('',(0.95,0.459620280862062,0.486871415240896));
#1250=CARTESIAN_POINT('',(0.95,0.455505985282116,0.483355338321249));
#1251=CARTESIAN_POINT('',(0.95,0.450814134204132,0.480813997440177));
#1252=CARTESIAN_POINT('',(0.95,0.445681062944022,0.479231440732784));
#1253=CARTESIAN_POINT('',(0.95,0.442103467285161,0.479056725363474));
#1254=CARTESIAN_POINT('',(0.95,0.440272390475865,0.478967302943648));
#1255=B_SPLINE_CURVE_WITH_KNOTS('',3,(#1244,#1245,#1246,#1247,#1248,#1249,#1250,#1251,#1252,
#1253,#1254),.UNSPECIFIED.,.F.,.F.,(4,1,1,1,1,1,1,1,4),(0.,0.127119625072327,0.250276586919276,
0.371969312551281,0.499374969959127,0.626629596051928,0.749350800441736,0.871713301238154,1.),.UNSPECIFIED.);
#1256=DIRECTION('',(1.,0.,0.));
#1257=VECTOR('',#1256,1.);
#1258=SURFACE_OF_LINEAR_EXTRUSION('',#1255,#1257);
#1259=ORIENTED_EDGE('',*,*,#852,.F.);
#1260=ORIENTED_EDGE('',*,*,#1239,.F.);
#1261=CARTESIAN_POINT('',(0.95,0.440272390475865,0.478967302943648));
#1262=VERTEX_POINT('',#1261);
#1263=EDGE_CURVE('E1477',#1232,#1262,#1255,.T.);
#1264=ORIENTED_EDGE('',*,*,#1263,.T.);
#1265=DIRECTION('',(1.,0.,0.));
#1266=VECTOR('',#1265,1.);
#1267=CARTESIAN_POINT('',(0.95,0.440272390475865,0.478967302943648));
#1268=LINE('',#1267,#1266);
#1269=EDGE_CURVE('E976',#1262,#851,#1268,.T.);
#1270=ORIENTED_EDGE('',*,*,#1269,.T.);
#1271=EDGE_LOOP('',(#1259,#1260,#1264,#1270));
#1272=FACE_BOUND('',#1271,.T.);
#1273=ADVANCED_FACE('F1488',(#1272),#1258,.T.);
#1274=CARTESIAN_POINT('',(0.95,0.440272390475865,0.478967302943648));
#1275=CARTESIAN_POINT('',(0.95,0.438441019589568,0.479056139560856));
#1276=CARTESIAN_POINT('',(0.95,0.434862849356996,0.479229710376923));
#1277=CARTESIAN_POINT('',(0.95,0.429719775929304,0.480824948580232));
#1278=CARTESIAN_POINT('',(0.95,0.4249893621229,0.483351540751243));
#1279=CARTESIAN_POINT('',(0.95,0.420830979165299,0.486871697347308));
#1280=CARTESIAN_POINT('',(0.95,0.417346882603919,0.491012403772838));
#1281=CARTESIAN_POINT('',(0.95,0.414749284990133,0.495690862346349));
#1282=CARTESIAN_POINT('',(0.95,0.41320724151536,0.500823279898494));
#1283=CARTESIAN_POINT('',(0.95,0.413022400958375,0.504397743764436));
#1284=CARTESIAN_POINT('',(0.95,0.412928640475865,0.506210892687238));
#1285=B_SPLINE_CURVE_WITH_KNOTS('',3,(#1274,#1275,#1276,#1277,#1278,#1279,#1280,#1281,#1282,
#1283,#1284),.UNSPECIFIED.,.F.,.F.,(4,1,1,1,1,1,1,1,4),(0.,0.12790236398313,0.249898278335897,
0.373279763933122,0.501048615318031,0.628817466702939,0.750145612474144,0.873261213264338,1.),.UNSPECIFIED.);
#1286=DIRECTION('',(1.,0.,0.));
#1287=VECTOR('',#1286,1.);
#1288=SURFACE_OF_LINEAR_EXTRUSION('',#1285,#1287);
#1289=ORIENTED_EDGE('',*,*,#868,.F.);
#1290=ORIENTED_EDGE('',*,*,#1269,.F.);
#1291=CARTESIAN_POINT('',(0.95,0.412928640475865,0.506210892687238));
#1292=VERTEX_POINT('',#1291);
#1293=EDGE_CURVE('E930',#1262,#1292,#1285,.T.);
#1294=ORIENTED_EDGE('',*,*,#1293,.T.);
#1295=DIRECTION('',(1.,0.,0.));
#1296=VECTOR('',#1295,1.);
#1297=CARTESIAN_POINT('',(0.95,0.412928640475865,0.506210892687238));
#1298=LINE('',#1297,#1296);
#1299=EDGE_CURVE('E974',#1292,#867,#1298,.T.);
#1300=ORIENTED_EDGE('',*,*,#1299,.T.);
#1301=EDGE_LOOP('',(#1289,#1290,#1294,#1300));
#1302=FACE_BOUND('',#1301,.T.);
#1303=ADVANCED_FACE('F920',(#1302),#1288,.T.);
#1304=CARTESIAN_POINT('',(0.95,0.412928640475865,0.506210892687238));
#1305=CARTESIAN_POINT('',(0.95,0.413021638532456,0.508024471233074));
#1306=CARTESIAN_POINT('',(0.95,0.413204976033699,0.511599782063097));
#1307=CARTESIAN_POINT('',(0.95,0.414762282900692,0.516740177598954));
#1308=CARTESIAN_POINT('',(0.95,0.417329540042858,0.521453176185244));
#1309=CARTESIAN_POINT('',(0.95,0.420835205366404,0.525594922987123));
#1310=CARTESIAN_POINT('',(0.95,0.424974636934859,0.529130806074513));
#1311=CARTESIAN_POINT('',(0.95,0.429734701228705,0.531585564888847));
#1312=CARTESIAN_POINT('',(0.95,0.434860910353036,0.533195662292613));
#1313=CARTESIAN_POINT('',(0.95,0.438440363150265,0.533366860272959));
#1314=CARTESIAN_POINT('',(0.95,0.440272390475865,0.533454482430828));
#1315=B_SPLINE_CURVE_WITH_KNOTS('',3,(#1304,#1305,#1306,#1307,#1308,#1309,#1310,#1311,#1312,
#1313,#1314),.UNSPECIFIED.,.F.,.F.,(4,1,1,1,1,1,1,1,4),(0.,0.126678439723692,0.249735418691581,
0.372030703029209,0.499738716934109,0.62744673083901,0.750220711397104,0.872158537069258,1.),.UNSPECIFIED.);
#1316=DIRECTION('',(1.,0.,0.));
#1317=VECTOR('',#1316,1.);
#1318=SURFACE_OF_LINEAR_EXTRUSION('',#1315,#1317);
#1319=ORIENTED_EDGE('',*,*,#882,.F.);
#1320=ORIENTED_EDGE('',*,*,#1299,.F.);
#1321=EDGE_CURVE('E924',#1292,#1228,#1315,.T.);
#1322=ORIENTED_EDGE('',*,*,#1321,.T.);
#1323=ORIENTED_EDGE('',*,*,#1229,.T.);
#1324=EDGE_LOOP('',(#1319,#1320,#1322,#1323));
#1325=FACE_BOUND('',#1324,.T.);
#1326=ADVANCED_FACE('F915',(#1325),#1318,.T.);
#1327=CARTESIAN_POINT('',(0.95,0.459508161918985,0.525486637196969));
#1328=DIRECTION('',(1.,0.,0.));
#1329=DIRECTION('',(0.,0.,-1.));
#1330=AXIS2_PLACEMENT_3D('',#1327,#1328,#1329);
#1331=PLANE('',#1330);
#1332=ORIENTED_EDGE('',*,*,#1233,.F.);
#1333=ORIENTED_EDGE('',*,*,#1321,.F.);
#1334=ORIENTED_EDGE('',*,*,#1293,.F.);
#1335=ORIENTED_EDGE('',*,*,#1263,.F.);
#1336=EDGE_LOOP('',(#1332,#1333,#1334,#1335));
#1337=FACE_BOUND('',#1336,.T.);
#1338=ADVANCED_FACE('F910',(#1337),#1331,.T.);
#1339=CARTESIAN_POINT('',(0.95,0.440272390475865,0.437300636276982));
#1340=CARTESIAN_POINT('',(0.95,0.442104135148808,0.437212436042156));
#1341=CARTESIAN_POINT('',(0.95,0.445683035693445,0.437040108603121));
#1342=CARTESIAN_POINT('',(0.95,0.450799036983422,0.435442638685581));
#1343=CARTESIAN_POINT('',(0.95,0.455520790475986,0.432973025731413));
#1344=CARTESIAN_POINT('',(0.95,0.459616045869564,0.429441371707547));
#1345=CARTESIAN_POINT('',(0.95,0.463057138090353,0.425282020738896));
#1346=CARTESIAN_POINT('',(0.95,0.465648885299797,0.420597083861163));
#1347=CARTESIAN_POINT('',(0.95,0.467123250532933,0.415436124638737));
#1348=CARTESIAN_POINT('',(0.95,0.467317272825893,0.411868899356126));
#1349=CARTESIAN_POINT('',(0.95,0.467415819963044,0.410057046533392));
#1350=B_SPLINE_CURVE_WITH_KNOTS('',3,(#1339,#1340,#1341,#1342,#1343,#1344,#1345,#1346,#1347,
#1348,#1349),.UNSPECIFIED.,.F.,.F.,(4,1,1,1,1,1,1,1,4),(0.,0.128226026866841,0.250530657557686,
0.372638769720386,0.499833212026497,0.627178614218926,0.749841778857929,0.872940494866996,1.),.UNSPECIFIED.);
#1351=DIRECTION('',(1.,0.,0.));
#1352=VECTOR('',#1351,1.);
#1353=SURFACE_OF_LINEAR_EXTRUSION('',#1350,#1352);
#1354=ORIENTED_EDGE('',*,*,#679,.F.);
#1355=DIRECTION('',(1.,0.,0.));
#1356=VECTOR('',#1355,1.);
#1357=CARTESIAN_POINT('',(0.95,0.440272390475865,0.437300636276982));
#1358=LINE('',#1357,#1356);
#1359=CARTESIAN_POINT('',(0.95,0.440272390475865,0.437300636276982));
#1360=VERTEX_POINT('',#1359);
#1361=EDGE_CURVE('E1427',#1360,#676,#1358,.T.);
#1362=ORIENTED_EDGE('',*,*,#1361,.F.);
#1363=CARTESIAN_POINT('',(0.95,0.467415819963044,0.410057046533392));
#1364=VERTEX_POINT('',#1363);
#1365=EDGE_CURVE('E889',#1360,#1364,#1350,.T.);
#1366=ORIENTED_EDGE('',*,*,#1365,.T.);
#1367=DIRECTION('',(1.,0.,0.));
#1368=VECTOR('',#1367,1.);
#1369=CARTESIAN_POINT('',(0.95,0.467415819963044,0.410057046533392));
#1370=LINE('',#1369,#1368);
#1371=EDGE_CURVE('E944',#1364,#678,#1370,.T.);
#1372=ORIENTED_EDGE('',*,*,#1371,.T.);
#1373=EDGE_LOOP('',(#1354,#1362,#1366,#1372));
#1374=FACE_BOUND('',#1373,.T.);
#1375=ADVANCED_FACE('F905',(#1374),#1353,.T.);
#1376=CARTESIAN_POINT('',(0.95,0.467415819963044,0.410057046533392));
#1377=CARTESIAN_POINT('',(0.95,0.467316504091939,0.408245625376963));
#1378=CARTESIAN_POINT('',(0.95,0.467120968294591,0.404679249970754));
#1379=CARTESIAN_POINT('',(0.95,0.465661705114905,0.399526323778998));
#1380=CARTESIAN_POINT('',(0.95,0.463039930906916,0.394875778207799));
#1381=CARTESIAN_POINT('',(0.95,0.459620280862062,0.39071756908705));
#1382=CARTESIAN_POINT('',(0.95,0.455505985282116,0.387201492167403));
#1383=CARTESIAN_POINT('',(0.95,0.450814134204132,0.384660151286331));
#1384=CARTESIAN_POINT('',(0.95,0.445681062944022,0.383077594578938));
#1385=CARTESIAN_POINT('',(0.95,0.442103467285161,0.382902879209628));
#1386=CARTESIAN_POINT('',(0.95,0.440272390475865,0.382813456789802));
#1387=B_SPLINE_CURVE_WITH_KNOTS('',3,(#1376,#1377,#1378,#1379,#1380,#1381,#1382,#1383,#1384,
#1385,#1386),.UNSPECIFIED.,.F.,.F.,(4,1,1,1,1,1,1,1,4),(0.,0.127119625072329,0.250276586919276,
0.37196931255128,0.499374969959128,0.626629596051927,0.749350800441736,0.871713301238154,1.),.UNSPECIFIED.);
#1388=DIRECTION('',(1.,0.,0.));
#1389=VECTOR('',#1388,1.);
#1390=SURFACE_OF_LINEAR_EXTRUSION('',#1387,#1389);
#1391=ORIENTED_EDGE('',*,*,#695,.F.);
#1392=ORIENTED_EDGE('',*,*,#1371,.F.);
#1393=CARTESIAN_POINT('',(0.95,0.440272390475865,0.382813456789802));
#1394=VERTEX_POINT('',#1393);
#1395=EDGE_CURVE('E895',#1364,#1394,#1387,.T.);
#1396=ORIENTED_EDGE('',*,*,#1395,.T.);
#1397=DIRECTION('',(1.,0.,0.));
#1398=VECTOR('',#1397,1.);
#1399=CARTESIAN_POINT('',(0.95,0.440272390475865,0.382813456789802));
#1400=LINE('',#1399,#1398);
#1401=EDGE_CURVE('E1469',#1394,#694,#1400,.T.);
#1402=ORIENTED_EDGE('',*,*,#1401,.T.);
#1403=EDGE_LOOP('',(#1391,#1392,#1396,#1402));
#1404=FACE_BOUND('',#1403,.T.);
#1405=ADVANCED_FACE('F909',(#1404),#1390,.T.);
#1406=CARTESIAN_POINT('',(0.95,0.440272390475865,0.382813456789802));
#1407=CARTESIAN_POINT('',(0.95,0.438441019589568,0.38290229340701));
#1408=CARTESIAN_POINT('',(0.95,0.434862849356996,0.383075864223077));
#1409=CARTESIAN_POINT('',(0.95,0.429719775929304,0.384671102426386));
#1410=CARTESIAN_POINT('',(0.95,0.4249893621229,0.387197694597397));
#1411=CARTESIAN_POINT('',(0.95,0.420830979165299,0.390717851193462));
#1412=CARTESIAN_POINT('',(0.95,0.417346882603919,0.394858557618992));
#1413=CARTESIAN_POINT('',(0.95,0.414749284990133,0.399537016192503));
#1414=CARTESIAN_POINT('',(0.95,0.41320724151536,0.404669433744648));
#1415=CARTESIAN_POINT('',(0.95,0.413022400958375,0.40824389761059));
#1416=CARTESIAN_POINT('',(0.95,0.412928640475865,0.410057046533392));
#1417=B_SPLINE_CURVE_WITH_KNOTS('',3,(#1406,#1407,#1408,#1409,#1410,#1411,#1412,#1413,#1414,
#1415,#1416),.UNSPECIFIED.,.F.,.F.,(4,1,1,1,1,1,1,1,4),(0.,0.127902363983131,0.249898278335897,
0.373279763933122,0.501048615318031,0.62881746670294,0.750145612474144,0.873261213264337,1.),.UNSPECIFIED.);
#1418=DIRECTION('',(1.,0.,0.));
#1419=VECTOR('',#1418,1.);
#1420=SURFACE_OF_LINEAR_EXTRUSION('',#1417,#1419);
#1421=ORIENTED_EDGE('',*,*,#711,.F.);
#1422=ORIENTED_EDGE('',*,*,#1401,.F.);
#1423=CARTESIAN_POINT('',(0.95,0.412928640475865,0.410057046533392));
#1424=VERTEX_POINT('',#1423);
#1425=EDGE_CURVE('E1428',#1394,#1424,#1417,.T.);
#1426=ORIENTED_EDGE('',*,*,#1425,.T.);
#1427=DIRECTION('',(1.,0.,0.));
#1428=VECTOR('',#1427,1.);
#1429=CARTESIAN_POINT('',(0.95,0.412928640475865,0.410057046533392));
#1430=LINE('',#1429,#1428);
#1431=EDGE_CURVE('E1467',#1424,#710,#1430,.T.);
#1432=ORIENTED_EDGE('',*,*,#1431,.T.);
#1433=EDGE_LOOP('',(#1421,#1422,#1426,#1432));
#1434=FACE_BOUND('',#1433,.T.);
#1435=ADVANCED_FACE('F1420',(#1434),#1420,.T.);
#1436=CARTESIAN_POINT('',(0.95,0.412928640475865,0.410057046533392));
#1437=CARTESIAN_POINT('',(0.95,0.413021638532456,0.411870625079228));
#1438=CARTESIAN_POINT('',(0.95,0.413204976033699,0.41544593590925));
#1439=CARTESIAN_POINT('',(0.95,0.414762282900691,0.420586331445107));
#1440=CARTESIAN_POINT('',(0.95,0.417329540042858,0.425299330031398));
#1441=CARTESIAN_POINT('',(0.95,0.420835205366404,0.429441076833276));
#1442=CARTESIAN_POINT('',(0.95,0.424974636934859,0.432976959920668));
#1443=CARTESIAN_POINT('',(0.95,0.429734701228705,0.435431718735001));
#1444=CARTESIAN_POINT('',(0.95,0.434860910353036,0.437041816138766));
#1445=CARTESIAN_POINT('',(0.95,0.438440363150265,0.437213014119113));
#1446=CARTESIAN_POINT('',(0.95,0.440272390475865,0.437300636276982));
#1447=B_SPLINE_CURVE_WITH_KNOTS('',3,(#1436,#1437,#1438,#1439,#1440,#1441,#1442,#1443,#1444,
#1445,#1446),.UNSPECIFIED.,.F.,.F.,(4,1,1,1,1,1,1,1,4),(0.,0.126678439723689,0.24973541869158,
0.372030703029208,0.49973871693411,0.627446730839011,0.750220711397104,0.872158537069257,1.),.UNSPECIFIED.);
#1448=DIRECTION('',(1.,0.,0.));
#1449=VECTOR('',#1448,1.);
#1450=SURFACE_OF_LINEAR_EXTRUSION('',#1447,#1449);
#1451=ORIENTED_EDGE('',*,*,#725,.F.);
#1452=ORIENTED_EDGE('',*,*,#1431,.F.);
#1453=EDGE_CURVE('E1422',#1424,#1360,#1447,.T.);
#1454=ORIENTED_EDGE('',*,*,#1453,.T.);
#1455=ORIENTED_EDGE('',*,*,#1361,.T.);
#1456=EDGE_LOOP('',(#1451,#1452,#1454,#1455));
#1457=FACE_BOUND('',#1456,.T.);
#1458=ADVANCED_FACE('F1416',(#1457),#1450,.T.);
#1459=CARTESIAN_POINT('',(0.95,0.459508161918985,0.429332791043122));
#1460=DIRECTION('',(1.,0.,1.60488253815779E-13));
#1461=DIRECTION('',(1.60488253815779E-13,0.,-1.));
#1462=AXIS2_PLACEMENT_3D('',#1459,#1460,#1461);
#1463=PLANE('',#1462);
#1464=ORIENTED_EDGE('',*,*,#1365,.F.);
#1465=ORIENTED_EDGE('',*,*,#1453,.F.);
#1466=ORIENTED_EDGE('',*,*,#1425,.F.);
#1467=ORIENTED_EDGE('',*,*,#1395,.F.);
#1468=EDGE_LOOP('',(#1464,#1465,#1466,#1467));
#1469=FACE_BOUND('',#1468,.T.);
#1470=ADVANCED_FACE('F1412',(#1469),#1463,.T.);
#1471=CARTESIAN_POINT('',(0.95,0.440272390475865,0.341146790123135));
#1472=CARTESIAN_POINT('',(0.95,0.442104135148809,0.34105858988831));
#1473=CARTESIAN_POINT('',(0.95,0.445683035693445,0.340886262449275));
#1474=CARTESIAN_POINT('',(0.95,0.450799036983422,0.339288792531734));
#1475=CARTESIAN_POINT('',(0.95,0.455520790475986,0.336819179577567));
#1476=CARTESIAN_POINT('',(0.95,0.459616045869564,0.333287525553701));
#1477=CARTESIAN_POINT('',(0.95,0.463057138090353,0.32912817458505));
#1478=CARTESIAN_POINT('',(0.95,0.465648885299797,0.324443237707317));
#1479=CARTESIAN_POINT('',(0.95,0.467123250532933,0.31928227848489));
#1480=CARTESIAN_POINT('',(0.95,0.467317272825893,0.31571505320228));
#1481=CARTESIAN_POINT('',(0.95,0.467415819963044,0.313903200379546));
#1482=B_SPLINE_CURVE_WITH_KNOTS('',3,(#1471,#1472,#1473,#1474,#1475,#1476,#1477,#1478,#1479,
#1480,#1481),.UNSPECIFIED.,.F.,.F.,(4,1,1,1,1,1,1,1,4),(0.,0.128226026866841,0.250530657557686,
0.372638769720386,0.499833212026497,0.627178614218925,0.749841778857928,0.872940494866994,1.),.UNSPECIFIED.);
#1483=DIRECTION('',(1.,0.,0.));
#1484=VECTOR('',#1483,1.);
#1485=SURFACE_OF_LINEAR_EXTRUSION('',#1482,#1484);
#1486=ORIENTED_EDGE('',*,*,#902,.F.);
#1487=DIRECTION('',(1.,0.,0.));
#1488=VECTOR('',#1487,1.);
#1489=CARTESIAN_POINT('',(0.95,0.440272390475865,0.341146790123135));
#1490=LINE('',#1489,#1488);
#1491=CARTESIAN_POINT('',(0.95,0.440272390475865,0.341146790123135));
#1492=VERTEX_POINT('',#1491);
#1493=EDGE_CURVE('E836',#1492,#899,#1490,.T.);
#1494=ORIENTED_EDGE('',*,*,#1493,.F.);
#1495=CARTESIAN_POINT('',(0.95,0.467415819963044,0.313903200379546));
#1496=VERTEX_POINT('',#1495);
#1497=EDGE_CURVE('E875',#1492,#1496,#1482,.T.);
#1498=ORIENTED_EDGE('',*,*,#1497,.T.);
#1499=DIRECTION('',(1.,0.,0.));
#1500=VECTOR('',#1499,1.);
#1501=CARTESIAN_POINT('',(0.95,0.467415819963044,0.313903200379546));
#1502=LINE('',#1501,#1500);
#1503=EDGE_CURVE('E885',#1496,#901,#1502,.T.);
#1504=ORIENTED_EDGE('',*,*,#1503,.T.);
#1505=EDGE_LOOP('',(#1486,#1494,#1498,#1504));
#1506=FACE_BOUND('',#1505,.T.);
#1507=ADVANCED_FACE('F1408',(#1506),#1485,.T.);
#1508=CARTESIAN_POINT('',(0.95,0.467415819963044,0.313903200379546));
#1509=CARTESIAN_POINT('',(0.95,0.467316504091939,0.312091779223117));
#1510=CARTESIAN_POINT('',(0.95,0.467120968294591,0.308525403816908));
#1511=CARTESIAN_POINT('',(0.95,0.465661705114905,0.303372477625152));
#1512=CARTESIAN_POINT('',(0.95,0.463039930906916,0.298721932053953));
#1513=CARTESIAN_POINT('',(0.95,0.459620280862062,0.294563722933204));
#1514=CARTESIAN_POINT('',(0.950000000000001,0.455505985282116,0.291047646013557));
#1515=CARTESIAN_POINT('',(0.95,0.450814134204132,0.288506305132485));
#1516=CARTESIAN_POINT('',(0.95,0.445681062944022,0.286923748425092));
#1517=CARTESIAN_POINT('',(0.95,0.442103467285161,0.286749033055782));
#1518=CARTESIAN_POINT('',(0.95,0.440272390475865,0.286659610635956));
#1519=B_SPLINE_CURVE_WITH_KNOTS('',3,(#1508,#1509,#1510,#1511,#1512,#1513,#1514,#1515,#1516,
#1517,#1518),.UNSPECIFIED.,.F.,.F.,(4,1,1,1,1,1,1,1,4),(0.,0.127119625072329,0.250276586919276,
0.37196931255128,0.499374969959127,0.626629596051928,0.749350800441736,0.871713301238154,1.),.UNSPECIFIED.);
#1520=DIRECTION('',(1.,0.,0.));
#1521=VECTOR('',#1520,1.);
#1522=SURFACE_OF_LINEAR_EXTRUSION('',#1519,#1521);
#1523=ORIENTED_EDGE('',*,*,#918,.F.);
#1524=ORIENTED_EDGE('',*,*,#1503,.F.);
#1525=CARTESIAN_POINT('',(0.95,0.440272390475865,0.286659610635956));
#1526=VERTEX_POINT('',#1525);
#1527=EDGE_CURVE('E1400',#1496,#1526,#1519,.T.);
#1528=ORIENTED_EDGE('',*,*,#1527,.T.);
#1529=DIRECTION('',(1.,0.,0.));
#1530=VECTOR('',#1529,1.);
#1531=CARTESIAN_POINT('',(0.95,0.440272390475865,0.286659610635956));
#1532=LINE('',#1531,#1530);
#1533=EDGE_CURVE('E883',#1526,#917,#1532,.T.);
#1534=ORIENTED_EDGE('',*,*,#1533,.T.);
#1535=EDGE_LOOP('',(#1523,#1524,#1528,#1534));
#1536=FACE_BOUND('',#1535,.T.);
#1537=ADVANCED_FACE('F1411',(#1536),#1522,.T.);
#1538=CARTESIAN_POINT('',(0.95,0.440272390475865,0.286659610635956));
#1539=CARTESIAN_POINT('',(0.95,0.438441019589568,0.286748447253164));
#1540=CARTESIAN_POINT('',(0.95,0.434862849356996,0.28692201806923));
#1541=CARTESIAN_POINT('',(0.95,0.429719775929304,0.28851725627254));
#1542=CARTESIAN_POINT('',(0.95,0.4249893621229,0.291043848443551));
#1543=CARTESIAN_POINT('',(0.95,0.420830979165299,0.294564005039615));
#1544=CARTESIAN_POINT('',(0.95,0.417346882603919,0.298704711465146));
#1545=CARTESIAN_POINT('',(0.95,0.414749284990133,0.303383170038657));
#1546=CARTESIAN_POINT('',(0.95,0.41320724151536,0.308515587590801));
#1547=CARTESIAN_POINT('',(0.95,0.413022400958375,0.312090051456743));
#1548=CARTESIAN_POINT('',(0.95,0.412928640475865,0.313903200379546));
#1549=B_SPLINE_CURVE_WITH_KNOTS('',3,(#1538,#1539,#1540,#1541,#1542,#1543,#1544,#1545,#1546,
#1547,#1548),.UNSPECIFIED.,.F.,.F.,(4,1,1,1,1,1,1,1,4),(0.,0.12790236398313,0.249898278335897,
0.373279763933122,0.501048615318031,0.62881746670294,0.750145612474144,0.873261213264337,1.),.UNSPECIFIED.);
#1550=DIRECTION('',(1.,0.,0.));
#1551=VECTOR('',#1550,1.);
#1552=SURFACE_OF_LINEAR_EXTRUSION('',#1549,#1551);
#1553=ORIENTED_EDGE('',*,*,#934,.F.);
#1554=ORIENTED_EDGE('',*,*,#1533,.F.);
#1555=CARTESIAN_POINT('',(0.95,0.412928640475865,0.313903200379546));
#1556=VERTEX_POINT('',#1555);
#1557=EDGE_CURVE('E837',#1526,#1556,#1549,.T.);
#1558=ORIENTED_EDGE('',*,*,#1557,.T.);
#1559=DIRECTION('',(1.,0.,0.));
#1560=VECTOR('',#1559,1.);
#1561=CARTESIAN_POINT('',(0.95,0.412928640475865,0.313903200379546));
#1562=LINE('',#1561,#1560);
#1563=EDGE_CURVE('E881',#1556,#933,#1562,.T.);
#1564=ORIENTED_EDGE('',*,*,#1563,.T.);
#1565=EDGE_LOOP('',(#1553,#1554,#1558,#1564));
#1566=FACE_BOUND('',#1565,.T.);
#1567=ADVANCED_FACE('F827',(#1566),#1552,.T.);
#1568=CARTESIAN_POINT('',(0.95,0.412928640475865,0.313903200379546));
#1569=CARTESIAN_POINT('',(0.95,0.413021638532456,0.315716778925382));
#1570=CARTESIAN_POINT('',(0.95,0.413204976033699,0.319292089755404));
#1571=CARTESIAN_POINT('',(0.95,0.414762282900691,0.324432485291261));
#1572=CARTESIAN_POINT('',(0.95,0.417329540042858,0.329145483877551));
#1573=CARTESIAN_POINT('',(0.95,0.420835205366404,0.33328723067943));
#1574=CARTESIAN_POINT('',(0.95,0.424974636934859,0.336823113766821));
#1575=CARTESIAN_POINT('',(0.95,0.429734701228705,0.339277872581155));
#1576=CARTESIAN_POINT('',(0.95,0.434860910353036,0.34088796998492));
#1577=CARTESIAN_POINT('',(0.95,0.438440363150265,0.341059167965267));
#1578=CARTESIAN_POINT('',(0.95,0.440272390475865,0.341146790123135));
#1579=B_SPLINE_CURVE_WITH_KNOTS('',3,(#1568,#1569,#1570,#1571,#1572,#1573,#1574,#1575,#1576,
#1577,#1578),.UNSPECIFIED.,.F.,.F.,(4,1,1,1,1,1,1,1,4),(0.,0.126678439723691,0.249735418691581,
0.372030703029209,0.49973871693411,0.627446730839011,0.750220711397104,0.872158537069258,1.),.UNSPECIFIED.);
#1580=DIRECTION('',(1.,0.,0.));
#1581=VECTOR('',#1580,1.);
#1582=SURFACE_OF_LINEAR_EXTRUSION('',#1579,#1581);
#1583=ORIENTED_EDGE('',*,*,#948,.F.);
#1584=ORIENTED_EDGE('',*,*,#1563,.F.);
#1585=EDGE_CURVE('E831',#1556,#1492,#1579,.T.);
#1586=ORIENTED_EDGE('',*,*,#1585,.T.);
#1587=ORIENTED_EDGE('',*,*,#1493,.T.);
#1588=EDGE_LOOP('',(#1583,#1584,#1586,#1587));
#1589=FACE_BOUND('',#1588,.T.);
#1590=ADVANCED_FACE('F822',(#1589),#1582,.T.);
#1591=CARTESIAN_POINT('',(0.95,0.459508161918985,0.333178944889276));
#1592=DIRECTION('',(1.,0.,1.6048825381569E-13));
#1593=DIRECTION('',(1.6048825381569E-13,0.,-1.));
#1594=AXIS2_PLACEMENT_3D('',#1591,#1592,#1593);
#1595=PLANE('',#1594);
#1596=ORIENTED_EDGE('',*,*,#1497,.F.);
#1597=ORIENTED_EDGE('',*,*,#1585,.F.);
#1598=ORIENTED_EDGE('',*,*,#1557,.F.);
#1599=ORIENTED_EDGE('',*,*,#1527,.F.);
#1600=EDGE_LOOP('',(#1596,#1597,#1598,#1599));
#1601=FACE_BOUND('',#1600,.T.);
#1602=ADVANCED_FACE('F818',(#1601),#1595,.T.);
#1603=CARTESIAN_POINT('',(0.39758154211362,0.527964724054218,0.95));
#1604=DIRECTION('',(0.838038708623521,0.54561077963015,0.));
#1605=DIRECTION('',(-0.54561077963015,0.838038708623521,0.));
#1606=AXIS2_PLACEMENT_3D('',#1603,#1604,#1605);
#1607=PLANE('',#1606);
#1608=ORIENTED_EDGE('',*,*,#410,.F.);
#1609=DIRECTION('',(0.,0.,1.));
#1610=VECTOR('',#1609,1.);
#1611=CARTESIAN_POINT('',(0.39758154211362,0.527964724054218,0.95));
#1612=LINE('',#1611,#1610);
#1613=CARTESIAN_POINT('',(0.39758154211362,0.527964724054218,0.95));
#1614=VERTEX_POINT('',#1613);
#1615=EDGE_CURVE('E1337',#1614,#407,#1612,.T.);
#1616=ORIENTED_EDGE('',*,*,#1615,.F.);
#1617=DIRECTION('',(-0.54561077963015,0.838038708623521,0.));
#1618=VECTOR('',#1617,1.);
#1619=CARTESIAN_POINT('',(0.39758154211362,0.527964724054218,0.95));
#1620=LINE('',#1619,#1618);
#1621=CARTESIAN_POINT('',(0.318905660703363,0.648808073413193,0.95));
#1622=VERTEX_POINT('',#1621);
#1623=EDGE_CURVE('E1311',#1614,#1622,#1620,.T.);
#1624=ORIENTED_EDGE('',*,*,#1623,.T.);
#1625=DIRECTION('',(0.,0.,1.));
#1626=VECTOR('',#1625,1.);
#1627=CARTESIAN_POINT('',(0.318905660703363,0.648808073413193,0.95));
#1628=LINE('',#1627,#1626);
#1629=EDGE_CURVE('E851',#1622,#409,#1628,.T.);
#1630=ORIENTED_EDGE('',*,*,#1629,.T.);
#1631=EDGE_LOOP('',(#1608,#1616,#1624,#1630));
#1632=FACE_BOUND('',#1631,.T.);
#1633=ADVANCED_FACE('F814',(#1632),#1607,.T.);
#1634=CARTESIAN_POINT('',(0.318905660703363,0.648808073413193,0.95));
#1635=DIRECTION('',(0.,-1.,0.));
#1636=DIRECTION('',(0.,0.,-1.));
#1637=AXIS2_PLACEMENT_3D('',#1634,#1635,#1636);
#1638=PLANE('',#1637);
#1639=ORIENTED_EDGE('',*,*,#418,.F.);
#1640=ORIENTED_EDGE('',*,*,#1629,.F.);
#1641=DIRECTION('',(1.,0.,0.));
#1642=VECTOR('',#1641,1.);
#1643=CARTESIAN_POINT('',(0.318905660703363,0.648808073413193,0.95));
#1644=LINE('',#1643,#1642);
#1645=CARTESIAN_POINT('',(0.371790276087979,0.648808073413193,0.95));
#1646=VERTEX_POINT('',#1645);
#1647=EDGE_CURVE('E1314',#1622,#1646,#1644,.T.);
#1648=ORIENTED_EDGE('',*,*,#1647,.T.);
#1649=DIRECTION('',(0.,0.,1.));
#1650=VECTOR('',#1649,1.);
#1651=CARTESIAN_POINT('',(0.371790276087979,0.648808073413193,0.95));
#1652=LINE('',#1651,#1650);
#1653=EDGE_CURVE('E1392',#1646,#417,#1652,.T.);
#1654=ORIENTED_EDGE('',*,*,#1653,.T.);
#1655=EDGE_LOOP('',(#1639,#1640,#1648,#1654));
#1656=FACE_BOUND('',#1655,.T.);
#1657=ADVANCED_FACE('F810',(#1656),#1638,.T.);
#1658=CARTESIAN_POINT('',(0.371790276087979,0.648808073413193,0.95));
#1659=DIRECTION('',(-0.838192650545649,-0.545374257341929,0.));
#1660=DIRECTION('',(0.545374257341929,-0.838192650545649,0.));
#1661=AXIS2_PLACEMENT_3D('',#1658,#1659,#1660);
#1662=PLANE('',#1661);
#1663=ORIENTED_EDGE('',*,*,#426,.F.);
#1664=ORIENTED_EDGE('',*,*,#1653,.F.);
#1665=DIRECTION('',(0.545374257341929,-0.838192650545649,0.));
#1666=VECTOR('',#1665,1.);
#1667=CARTESIAN_POINT('',(0.371790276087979,0.648808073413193,0.95));
#1668=LINE('',#1667,#1666);
#1669=CARTESIAN_POINT('',(0.424023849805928,0.568529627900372,0.95));
#1670=VERTEX_POINT('',#1669);
#1671=EDGE_CURVE('E1317',#1646,#1670,#1668,.T.);
#1672=ORIENTED_EDGE('',*,*,#1671,.T.);
#1673=DIRECTION('',(0.,0.,1.));
#1674=VECTOR('',#1673,1.);
#1675=CARTESIAN_POINT('',(0.424023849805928,0.568529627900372,0.95));
#1676=LINE('',#1675,#1674);
#1677=EDGE_CURVE('E1390',#1670,#425,#1676,.T.);
#1678=ORIENTED_EDGE('',*,*,#1677,.T.);
#1679=EDGE_LOOP('',(#1663,#1664,#1672,#1678));
#1680=FACE_BOUND('',#1679,.T.);
#1681=ADVANCED_FACE('F806',(#1680),#1662,.T.);
#1682=CARTESIAN_POINT('',(0.424023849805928,0.568529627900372,0.95));
#1683=DIRECTION('',(0.83771454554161,-0.546108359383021,0.));
#1684=DIRECTION('',(0.546108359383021,0.83771454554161,0.));
#1685=AXIS2_PLACEMENT_3D('',#1682,#1683,#1684);
#1686=PLANE('',#1685);
#1687=ORIENTED_EDGE('',*,*,#434,.F.);
#1688=ORIENTED_EDGE('',*,*,#1677,.F.);
#1689=DIRECTION('',(0.546108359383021,0.837714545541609,0.));
#1690=VECTOR('',#1689,1.);
#1691=CARTESIAN_POINT('',(0.424023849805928,0.568529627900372,0.95));
#1692=LINE('',#1691,#1690);
#1693=CARTESIAN_POINT('',(0.476357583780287,0.648808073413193,0.95));
#1694=VERTEX_POINT('',#1693);
#1695=EDGE_CURVE('E1319',#1670,#1694,#1692,.T.);
#1696=ORIENTED_EDGE('',*,*,#1695,.T.);
#1697=DIRECTION('',(0.,0.,1.));
#1698=VECTOR('',#1697,1.);
#1699=CARTESIAN_POINT('',(0.476357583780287,0.648808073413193,0.95));
#1700=LINE('',#1699,#1698);
#1701=EDGE_CURVE('E1388',#1694,#433,#1700,.T.);
#1702=ORIENTED_EDGE('',*,*,#1701,.T.);
#1703=EDGE_LOOP('',(#1687,#1688,#1696,#1702));
#1704=FACE_BOUND('',#1703,.T.);
#1705=ADVANCED_FACE('F802',(#1704),#1686,.T.);
#1706=CARTESIAN_POINT('',(0.476357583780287,0.648808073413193,0.95));
#1707=DIRECTION('',(0.,-1.,0.));
#1708=DIRECTION('',(0.,0.,-1.));
#1709=AXIS2_PLACEMENT_3D('',#1706,#1707,#1708);
#1710=PLANE('',#1709);
#1711=ORIENTED_EDGE('',*,*,#442,.F.);
#1712=ORIENTED_EDGE('',*,*,#1701,.F.);
#1713=DIRECTION('',(1.,0.,0.));
#1714=VECTOR('',#1713,1.);
#1715=CARTESIAN_POINT('',(0.476357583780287,0.648808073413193,0.95));
#1716=LINE('',#1715,#1714);
#1717=CARTESIAN_POINT('',(0.529292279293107,0.648808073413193,0.95));
#1718=VERTEX_POINT('',#1717);
#1719=EDGE_CURVE('E1321',#1694,#1718,#1716,.T.);
#1720=ORIENTED_EDGE('',*,*,#1719,.T.);
#1721=DIRECTION('',(0.,0.,1.));
#1722=VECTOR('',#1721,1.);
#1723=CARTESIAN_POINT('',(0.529292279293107,0.648808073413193,0.95));
#1724=LINE('',#1723,#1722);
#1725=EDGE_CURVE('E1386',#1718,#441,#1724,.T.);
#1726=ORIENTED_EDGE('',*,*,#1725,.T.);
#1727=EDGE_LOOP('',(#1711,#1712,#1720,#1726));
#1728=FACE_BOUND('',#1727,.T.);
#1729=ADVANCED_FACE('F798',(#1728),#1710,.T.);
#1730=CARTESIAN_POINT('',(0.529292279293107,0.648808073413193,0.95));
#1731=DIRECTION('',(-0.837665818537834,0.546183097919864,0.));
#1732=DIRECTION('',(-0.546183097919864,-0.837665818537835,0.));
#1733=AXIS2_PLACEMENT_3D('',#1730,#1731,#1732);
#1734=PLANE('',#1733);
#1735=ORIENTED_EDGE('',*,*,#450,.F.);
#1736=ORIENTED_EDGE('',*,*,#1725,.F.);
#1737=DIRECTION('',(-0.546183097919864,-0.837665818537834,0.));
#1738=VECTOR('',#1737,1.);
#1739=CARTESIAN_POINT('',(0.529292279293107,0.648808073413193,0.95));
#1740=LINE('',#1739,#1738);
#1741=CARTESIAN_POINT('',(0.450466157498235,0.527914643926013,0.95));
#1742=VERTEX_POINT('',#1741);
#1743=EDGE_CURVE('E1323',#1718,#1742,#1740,.T.);
#1744=ORIENTED_EDGE('',*,*,#1743,.T.);
#1745=DIRECTION('',(0.,0.,1.));
#1746=VECTOR('',#1745,1.);
#1747=CARTESIAN_POINT('',(0.450466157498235,0.527914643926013,0.95));
#1748=LINE('',#1747,#1746);
#1749=EDGE_CURVE('E1384',#1742,#449,#1748,.T.);
#1750=ORIENTED_EDGE('',*,*,#1749,.T.);
#1751=EDGE_LOOP('',(#1735,#1736,#1744,#1750));
#1752=FACE_BOUND('',#1751,.T.);
#1753=ADVANCED_FACE('F794',(#1752),#1734,.T.);
#1754=CARTESIAN_POINT('',(0.450466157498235,0.527914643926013,0.95));
#1755=DIRECTION('',(-0.838101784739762,-0.545513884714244,0.));
#1756=DIRECTION('',(0.545513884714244,-0.838101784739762,0.));
#1757=AXIS2_PLACEMENT_3D('',#1754,#1755,#1756);
#1758=PLANE('',#1757);
#1759=ORIENTED_EDGE('',*,*,#458,.F.);
#1760=ORIENTED_EDGE('',*,*,#1749,.F.);
#1761=DIRECTION('',(0.545513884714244,-0.838101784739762,0.));
#1762=VECTOR('',#1761,1.);
#1763=CARTESIAN_POINT('',(0.450466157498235,0.527914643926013,0.95));
#1764=LINE('',#1763,#1762);
#1765=CARTESIAN_POINT('',(0.53450061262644,0.398808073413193,0.95));
#1766=VERTEX_POINT('',#1765);
#1767=EDGE_CURVE('E1325',#1742,#1766,#1764,.T.);
#1768=ORIENTED_EDGE('',*,*,#1767,.T.);
#1769=DIRECTION('',(0.,0.,1.));
#1770=VECTOR('',#1769,1.);
#1771=CARTESIAN_POINT('',(0.53450061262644,0.398808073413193,0.95));
#1772=LINE('',#1771,#1770);
#1773=EDGE_CURVE('E1382',#1766,#457,#1772,.T.);
#1774=ORIENTED_EDGE('',*,*,#1773,.T.);
#1775=EDGE_LOOP('',(#1759,#1760,#1768,#1774));
#1776=FACE_BOUND('',#1775,.T.);
#1777=ADVANCED_FACE('F790',(#1776),#1758,.T.);
#1778=CARTESIAN_POINT('',(0.53450061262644,0.398808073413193,0.95));
#1779=DIRECTION('',(0.,1.,0.));
#1780=DIRECTION('',(0.,0.,1.));
#1781=AXIS2_PLACEMENT_3D('',#1778,#1779,#1780);
#1782=PLANE('',#1781);
#1783=ORIENTED_EDGE('',*,*,#466,.F.);
#1784=ORIENTED_EDGE('',*,*,#1773,.F.);
#1785=DIRECTION('',(-1.,0.,0.));
#1786=VECTOR('',#1785,1.);
#1787=CARTESIAN_POINT('',(0.53450061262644,0.398808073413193,0.95));
#1788=LINE('',#1787,#1786);
#1789=CARTESIAN_POINT('',(0.481615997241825,0.398808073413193,0.95));
#1790=VERTEX_POINT('',#1789);
#1791=EDGE_CURVE('E1327',#1766,#1790,#1788,.T.);
#1792=ORIENTED_EDGE('',*,*,#1791,.T.);
#1793=DIRECTION('',(0.,0.,1.));
#1794=VECTOR('',#1793,1.);
#1795=CARTESIAN_POINT('',(0.481615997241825,0.398808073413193,0.95));
#1796=LINE('',#1795,#1794);
#1797=EDGE_CURVE('E1380',#1790,#465,#1796,.T.);
#1798=ORIENTED_EDGE('',*,*,#1797,.T.);
#1799=EDGE_LOOP('',(#1783,#1784,#1792,#1798));
#1800=FACE_BOUND('',#1799,.T.);
#1801=ADVANCED_FACE('F786',(#1800),#1782,.T.);
#1802=CARTESIAN_POINT('',(0.481615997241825,0.398808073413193,0.95));
#1803=DIRECTION('',(0.838270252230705,0.545254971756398,0.));
#1804=DIRECTION('',(-0.545254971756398,0.838270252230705,0.));
#1805=AXIS2_PLACEMENT_3D('',#1802,#1803,#1804);
#1806=PLANE('',#1805);
#1807=ORIENTED_EDGE('',*,*,#474,.F.);
#1808=ORIENTED_EDGE('',*,*,#1797,.F.);
#1809=DIRECTION('',(-0.545254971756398,0.838270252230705,0.));
#1810=VECTOR('',#1809,1.);
#1811=CARTESIAN_POINT('',(0.481615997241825,0.398808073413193,0.95));
#1812=LINE('',#1811,#1810);
#1813=CARTESIAN_POINT('',(0.424023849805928,0.487349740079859,0.95));
#1814=VERTEX_POINT('',#1813);
#1815=EDGE_CURVE('E1329',#1790,#1814,#1812,.T.);
#1816=ORIENTED_EDGE('',*,*,#1815,.T.);
#1817=DIRECTION('',(0.,0.,1.));
#1818=VECTOR('',#1817,1.);
#1819=CARTESIAN_POINT('',(0.424023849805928,0.487349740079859,0.95));
#1820=LINE('',#1819,#1818);
#1821=EDGE_CURVE('E1378',#1814,#473,#1820,.T.);
#1822=ORIENTED_EDGE('',*,*,#1821,.T.);
#1823=EDGE_LOOP('',(#1807,#1808,#1816,#1822));
#1824=FACE_BOUND('',#1823,.T.);
#1825=ADVANCED_FACE('F782',(#1824),#1806,.T.);
#1826=CARTESIAN_POINT('',(0.424023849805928,0.487349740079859,0.95));
#1827=DIRECTION('',(-0.837620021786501,0.54625332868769,0.));
#1828=DIRECTION('',(-0.54625332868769,-0.837620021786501,0.));
#1829=AXIS2_PLACEMENT_3D('',#1826,#1827,#1828);
#1830=PLANE('',#1829);
#1831=ORIENTED_EDGE('',*,*,#482,.F.);
#1832=ORIENTED_EDGE('',*,*,#1821,.F.);
#1833=DIRECTION('',(-0.54625332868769,-0.837620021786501,0.));
#1834=VECTOR('',#1833,1.);
#1835=CARTESIAN_POINT('',(0.424023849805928,0.487349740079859,0.95));
#1836=LINE('',#1835,#1834);
#1837=CARTESIAN_POINT('',(0.366281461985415,0.398808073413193,0.95));
#1838=VERTEX_POINT('',#1837);
#1839=EDGE_CURVE('E1331',#1814,#1838,#1836,.T.);
#1840=ORIENTED_EDGE('',*,*,#1839,.T.);
#1841=DIRECTION('',(0.,0.,1.));
#1842=VECTOR('',#1841,1.);
#1843=CARTESIAN_POINT('',(0.366281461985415,0.398808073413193,0.95));
#1844=LINE('',#1843,#1842);
#1845=EDGE_CURVE('E1376',#1838,#481,#1844,.T.);
#1846=ORIENTED_EDGE('',*,*,#1845,.T.);
#1847=EDGE_LOOP('',(#1831,#1832,#1840,#1846));
#1848=FACE_BOUND('',#1847,.T.);
#1849=ADVANCED_FACE('F778',(#1848),#1830,.T.);
#1850=CARTESIAN_POINT('',(0.366281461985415,0.398808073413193,0.95));
#1851=DIRECTION('',(0.,1.,0.));
#1852=DIRECTION('',(0.,0.,1.));
#1853=AXIS2_PLACEMENT_3D('',#1850,#1851,#1852);
#1854=PLANE('',#1853);
#1855=ORIENTED_EDGE('',*,*,#490,.F.);
#1856=ORIENTED_EDGE('',*,*,#1845,.F.);
#1857=DIRECTION('',(-1.,0.,0.));
#1858=VECTOR('',#1857,1.);
#1859=CARTESIAN_POINT('',(0.366281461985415,0.398808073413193,0.95));
#1860=LINE('',#1859,#1858);
#1861=CARTESIAN_POINT('',(0.313346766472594,0.398808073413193,0.95));
#1862=VERTEX_POINT('',#1861);
#1863=EDGE_CURVE('E1333',#1838,#1862,#1860,.T.);
#1864=ORIENTED_EDGE('',*,*,#1863,.T.);
#1865=DIRECTION('',(0.,0.,1.));
#1866=VECTOR('',#1865,1.);
#1867=CARTESIAN_POINT('',(0.313346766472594,0.398808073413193,0.95));
#1868=LINE('',#1867,#1866);
#1869=EDGE_CURVE('E1374',#1862,#489,#1868,.T.);
#1870=ORIENTED_EDGE('',*,*,#1869,.T.);
#1871=EDGE_LOOP('',(#1855,#1856,#1864,#1870));
#1872=FACE_BOUND('',#1871,.T.);
#1873=ADVANCED_FACE('F774',(#1872),#1854,.T.);
#1874=CARTESIAN_POINT('',(0.313346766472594,0.398808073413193,0.95));
#1875=DIRECTION('',(0.837604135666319,-0.546277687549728,0.));
#1876=DIRECTION('',(0.546277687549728,0.837604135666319,0.));
#1877=AXIS2_PLACEMENT_3D('',#1874,#1875,#1876);
#1878=PLANE('',#1877);
#1879=ORIENTED_EDGE('',*,*,#496,.F.);
#1880=ORIENTED_EDGE('',*,*,#1869,.F.);
#1881=DIRECTION('',(0.546277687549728,0.837604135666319,0.));
#1882=VECTOR('',#1881,1.);
#1883=CARTESIAN_POINT('',(0.313346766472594,0.398808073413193,0.95));
#1884=LINE('',#1883,#1882);
#1885=EDGE_CURVE('E1335',#1862,#1614,#1884,.T.);
#1886=ORIENTED_EDGE('',*,*,#1885,.T.);
#1887=ORIENTED_EDGE('',*,*,#1615,.T.);
#1888=EDGE_LOOP('',(#1879,#1880,#1886,#1887));
#1889=FACE_BOUND('',#1888,.T.);
#1890=ADVANCED_FACE('F770',(#1889),#1878,.T.);
#1891=CARTESIAN_POINT('',(0.,0.,0.95));
#1892=DIRECTION('',(0.,0.,-1.));
#1893=DIRECTION('',(-1.,0.,0.));
#1894=AXIS2_PLACEMENT_3D('',#1891,#1892,#1893);
#1895=PLANE('',#1894);
#1896=ORIENTED_EDGE('',*,*,#1623,.F.);
#1897=ORIENTED_EDGE('',*,*,#1885,.F.);
#1898=ORIENTED_EDGE('',*,*,#1863,.F.);
#1899=ORIENTED_EDGE('',*,*,#1839,.F.);
#1900=ORIENTED_EDGE('',*,*,#1815,.F.);
#1901=ORIENTED_EDGE('',*,*,#1791,.F.);
#1902=ORIENTED_EDGE('',*,*,#1767,.F.);
#1903=ORIENTED_EDGE('',*,*,#1743,.F.);
#1904=ORIENTED_EDGE('',*,*,#1719,.F.);
#1905=ORIENTED_EDGE('',*,*,#1695,.F.);
#1906=ORIENTED_EDGE('',*,*,#1671,.F.);
#1907=ORIENTED_EDGE('',*,*,#1647,.F.);
#1908=EDGE_LOOP('',(#1896,#1897,#1898,#1899,#1900,#1901,#1902,#1903,#1904,#1905,#1906,#1907));
#1909=FACE_BOUND('',#1908,.T.);
#1910=ADVANCED_FACE('F765',(#1909),#1895,.F.);
#1911=CARTESIAN_POINT('',(0.558539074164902,0.422946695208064,0.95));
#1912=CARTESIAN_POINT('',(0.558627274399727,0.424778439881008,0.95));
#1913=CARTESIAN_POINT('',(0.558799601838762,0.428357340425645,0.95));
#1914=CARTESIAN_POINT('',(0.560397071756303,0.433473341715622,0.95));
#1915=CARTESIAN_POINT('',(0.56286668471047,0.438195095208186,0.95));
#1916=CARTESIAN_POINT('',(0.566398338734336,0.442290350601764,0.95));
#1917=CARTESIAN_POINT('',(0.570557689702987,0.445731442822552,0.95));
#1918=CARTESIAN_POINT('',(0.575242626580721,0.448323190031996,0.95));
#1919=CARTESIAN_POINT('',(0.580403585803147,0.449797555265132,0.95));
#1920=CARTESIAN_POINT('',(0.583970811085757,0.449991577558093,0.95));
#1921=CARTESIAN_POINT('',(0.585782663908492,0.450090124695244,0.95));
#1922=B_SPLINE_CURVE_WITH_KNOTS('',3,(#1911,#1912,#1913,#1914,#1915,#1916,#1917,#1918,#1919,
#1920,#1921),.UNSPECIFIED.,.F.,.F.,(4,1,1,1,1,1,1,1,4),(0.,0.128226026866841,0.250530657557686,
0.372638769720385,0.499833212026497,0.627178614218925,0.749841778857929,0.872940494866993,1.),.UNSPECIFIED.);
#1923=DIRECTION('',(0.,0.,1.));
#1924=VECTOR('',#1923,1.);
#1925=SURFACE_OF_LINEAR_EXTRUSION('',#1922,#1924);
#1926=ORIENTED_EDGE('',*,*,#541,.F.);
#1927=DIRECTION('',(0.,0.,1.));
#1928=VECTOR('',#1927,1.);
#1929=CARTESIAN_POINT('',(0.558539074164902,0.422946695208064,0.95));
#1930=LINE('',#1929,#1928);
#1931=CARTESIAN_POINT('',(0.558539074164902,0.422946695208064,0.95));
#1932=VERTEX_POINT('',#1931);
#1933=EDGE_CURVE('E1263',#1932,#538,#1930,.T.);
#1934=ORIENTED_EDGE('',*,*,#1933,.F.);
#1935=CARTESIAN_POINT('',(0.585782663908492,0.450090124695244,0.95));
#1936=VERTEX_POINT('',#1935);
#1937=EDGE_CURVE('E744',#1932,#1936,#1922,.T.);
#1938=ORIENTED_EDGE('',*,*,#1937,.T.);
#1939=DIRECTION('',(0.,0.,1.));
#1940=VECTOR('',#1939,1.);
#1941=CARTESIAN_POINT('',(0.585782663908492,0.450090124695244,0.95));
#1942=LINE('',#1941,#1940);
#1943=EDGE_CURVE('E1307',#1936,#540,#1942,.T.);
#1944=ORIENTED_EDGE('',*,*,#1943,.T.);
#1945=EDGE_LOOP('',(#1926,#1934,#1938,#1944));
#1946=FACE_BOUND('',#1945,.T.);
#1947=ADVANCED_FACE('F760',(#1946),#1925,.T.);
#1948=CARTESIAN_POINT('',(0.585782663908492,0.450090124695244,0.95));
#1949=CARTESIAN_POINT('',(0.587594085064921,0.449990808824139,0.95));
#1950=CARTESIAN_POINT('',(0.59116046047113,0.449795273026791,0.95));
#1951=CARTESIAN_POINT('',(0.596313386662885,0.448336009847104,0.95));
#1952=CARTESIAN_POINT('',(0.600963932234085,0.445714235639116,0.95));
#1953=CARTESIAN_POINT('',(0.605122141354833,0.442294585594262,0.95));
#1954=CARTESIAN_POINT('',(0.608638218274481,0.438180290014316,0.95));
#1955=CARTESIAN_POINT('',(0.611179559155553,0.433488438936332,0.95));
#1956=CARTESIAN_POINT('',(0.612762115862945,0.428355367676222,0.95));
#1957=CARTESIAN_POINT('',(0.612936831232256,0.424777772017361,0.95));
#1958=CARTESIAN_POINT('',(0.613026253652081,0.422946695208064,0.95));
#1959=B_SPLINE_CURVE_WITH_KNOTS('',3,(#1948,#1949,#1950,#1951,#1952,#1953,#1954,#1955,#1956,
#1957,#1958),.UNSPECIFIED.,.F.,.F.,(4,1,1,1,1,1,1,1,4),(0.,0.127119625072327,0.250276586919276,
0.371969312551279,0.499374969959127,0.626629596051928,0.749350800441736,0.871713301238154,1.),.UNSPECIFIED.);
#1960=DIRECTION('',(0.,0.,1.));
#1961=VECTOR('',#1960,1.);
#1962=SURFACE_OF_LINEAR_EXTRUSION('',#1959,#1961);
#1963=ORIENTED_EDGE('',*,*,#557,.F.);
#1964=ORIENTED_EDGE('',*,*,#1943,.F.);
#1965=CARTESIAN_POINT('',(0.613026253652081,0.422946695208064,0.95));
#1966=VERTEX_POINT('',#1965);
#1967=EDGE_CURVE('E750',#1936,#1966,#1959,.T.);
#1968=ORIENTED_EDGE('',*,*,#1967,.T.);
#1969=DIRECTION('',(0.,0.,1.));
#1970=VECTOR('',#1969,1.);
#1971=CARTESIAN_POINT('',(0.613026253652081,0.422946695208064,0.95));
#1972=LINE('',#1971,#1970);
#1973=EDGE_CURVE('E1305',#1966,#556,#1972,.T.);
#1974=ORIENTED_EDGE('',*,*,#1973,.T.);
#1975=EDGE_LOOP('',(#1963,#1964,#1968,#1974));
#1976=FACE_BOUND('',#1975,.T.);
#1977=ADVANCED_FACE('F764',(#1976),#1962,.T.);
#1978=CARTESIAN_POINT('',(0.613026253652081,0.422946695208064,0.95));
#1979=CARTESIAN_POINT('',(0.612937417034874,0.421115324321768,0.95));
#1980=CARTESIAN_POINT('',(0.612763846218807,0.417537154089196,0.95));
#1981=CARTESIAN_POINT('',(0.611168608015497,0.412394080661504,0.95));
#1982=CARTESIAN_POINT('',(0.608642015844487,0.4076636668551,0.95));
#1983=CARTESIAN_POINT('',(0.605121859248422,0.403505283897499,0.95));
#1984=CARTESIAN_POINT('',(0.600981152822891,0.400021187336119,0.95));
#1985=CARTESIAN_POINT('',(0.59630269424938,0.397423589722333,0.95));
#1986=CARTESIAN_POINT('',(0.591170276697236,0.39588154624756,0.95));
#1987=CARTESIAN_POINT('',(0.587595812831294,0.395696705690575,0.95));
#1988=CARTESIAN_POINT('',(0.585782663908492,0.395602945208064,0.95));
#1989=B_SPLINE_CURVE_WITH_KNOTS('',3,(#1978,#1979,#1980,#1981,#1982,#1983,#1984,#1985,#1986,
#1987,#1988),.UNSPECIFIED.,.F.,.F.,(4,1,1,1,1,1,1,1,4),(0.,0.12790236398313,0.249898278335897,
0.373279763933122,0.501048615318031,0.628817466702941,0.750145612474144,0.873261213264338,1.),.UNSPECIFIED.);
#1990=DIRECTION('',(0.,0.,1.));
#1991=VECTOR('',#1990,1.);
#1992=SURFACE_OF_LINEAR_EXTRUSION('',#1989,#1991);
#1993=ORIENTED_EDGE('',*,*,#573,.F.);
#1994=ORIENTED_EDGE('',*,*,#1973,.F.);
#1995=CARTESIAN_POINT('',(0.585782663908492,0.395602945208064,0.95));
#1996=VERTEX_POINT('',#1995);
#1997=EDGE_CURVE('E1264',#1966,#1996,#1989,.T.);
#1998=ORIENTED_EDGE('',*,*,#1997,.T.);
#1999=DIRECTION('',(0.,0.,1.));
#2000=VECTOR('',#1999,1.);
#2001=CARTESIAN_POINT('',(0.585782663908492,0.395602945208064,0.95));
#2002=LINE('',#2001,#2000);
#2003=EDGE_CURVE('E1303',#1996,#572,#2002,.T.);
#2004=ORIENTED_EDGE('',*,*,#2003,.T.);
#2005=EDGE_LOOP('',(#1993,#1994,#1998,#2004));
#2006=FACE_BOUND('',#2005,.T.);
#2007=ADVANCED_FACE('F1256',(#2006),#1992,.T.);
#2008=CARTESIAN_POINT('',(0.585782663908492,0.395602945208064,0.95));
#2009=CARTESIAN_POINT('',(0.583969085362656,0.395695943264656,0.95));
#2010=CARTESIAN_POINT('',(0.580393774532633,0.395879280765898,0.95));
#2011=CARTESIAN_POINT('',(0.575253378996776,0.397436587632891,0.95));
#2012=CARTESIAN_POINT('',(0.570540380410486,0.400003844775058,0.95));
#2013=CARTESIAN_POINT('',(0.566398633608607,0.403509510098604,0.95));
#2014=CARTESIAN_POINT('',(0.562862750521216,0.407648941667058,0.95));
#2015=CARTESIAN_POINT('',(0.560407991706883,0.412409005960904,0.95));
#2016=CARTESIAN_POINT('',(0.558797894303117,0.417535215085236,0.95));
#2017=CARTESIAN_POINT('',(0.558626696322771,0.421114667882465,0.95));
#2018=CARTESIAN_POINT('',(0.558539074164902,0.422946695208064,0.95));
#2019=B_SPLINE_CURVE_WITH_KNOTS('',3,(#2008,#2009,#2010,#2011,#2012,#2013,#2014,#2015,#2016,
#2017,#2018),.UNSPECIFIED.,.F.,.F.,(4,1,1,1,1,1,1,1,4),(0.,0.126678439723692,0.249735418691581,
0.372030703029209,0.49973871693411,0.627446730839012,0.750220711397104,0.872158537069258,1.),.UNSPECIFIED.);
#2020=DIRECTION('',(0.,0.,1.));
#2021=VECTOR('',#2020,1.);
#2022=SURFACE_OF_LINEAR_EXTRUSION('',#2019,#2021);
#2023=ORIENTED_EDGE('',*,*,#587,.F.);
#2024=ORIENTED_EDGE('',*,*,#2003,.F.);
#2025=EDGE_CURVE('E1258',#1996,#1932,#2019,.T.);
#2026=ORIENTED_EDGE('',*,*,#2025,.T.);
#2027=ORIENTED_EDGE('',*,*,#1933,.T.);
#2028=EDGE_LOOP('',(#2023,#2024,#2026,#2027));
#2029=FACE_BOUND('',#2028,.T.);
#2030=ADVANCED_FACE('F1252',(#2029),#2022,.T.);
#2031=CARTESIAN_POINT('',(0.566506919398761,0.442182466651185,0.95));
#2032=DIRECTION('',(0.,0.,1.));
#2033=DIRECTION('',(1.,0.,0.));
#2034=AXIS2_PLACEMENT_3D('',#2031,#2032,#2033);
#2035=PLANE('',#2034);
#2036=ORIENTED_EDGE('',*,*,#1937,.F.);
#2037=ORIENTED_EDGE('',*,*,#2025,.F.);
#2038=ORIENTED_EDGE('',*,*,#1997,.F.);
#2039=ORIENTED_EDGE('',*,*,#1967,.F.);
#2040=EDGE_LOOP('',(#2036,#2037,#2038,#2039));
#2041=FACE_BOUND('',#2040,.T.);
#2042=ADVANCED_FACE('F1248',(#2041),#2035,.T.);
#2043=CARTESIAN_POINT('',(0.654692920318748,0.422946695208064,0.95));
#2044=CARTESIAN_POINT('',(0.654781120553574,0.424778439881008,0.95));
#2045=CARTESIAN_POINT('',(0.654953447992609,0.428357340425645,0.95));
#2046=CARTESIAN_POINT('',(0.656550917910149,0.433473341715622,0.95));
#2047=CARTESIAN_POINT('',(0.659020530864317,0.438195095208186,0.95));
#2048=CARTESIAN_POINT('',(0.662552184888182,0.442290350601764,0.95));
#2049=CARTESIAN_POINT('',(0.666711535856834,0.445731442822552,0.95));
#2050=CARTESIAN_POINT('',(0.671396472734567,0.448323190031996,0.95));
#2051=CARTESIAN_POINT('',(0.676557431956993,0.449797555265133,0.95));
#2052=CARTESIAN_POINT('',(0.680124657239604,0.449991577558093,0.95));
#2053=CARTESIAN_POINT('',(0.681936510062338,0.450090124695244,0.95));
#2054=B_SPLINE_CURVE_WITH_KNOTS('',3,(#2043,#2044,#2045,#2046,#2047,#2048,#2049,#2050,#2051,
#2052,#2053),.UNSPECIFIED.,.F.,.F.,(4,1,1,1,1,1,1,1,4),(0.,0.128226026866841,0.250530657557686,
0.372638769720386,0.499833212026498,0.627178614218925,0.749841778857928,0.872940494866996,1.),.UNSPECIFIED.);
#2055=DIRECTION('',(0.,0.,1.));
#2056=VECTOR('',#2055,1.);
#2057=SURFACE_OF_LINEAR_EXTRUSION('',#2054,#2056);
#2058=ORIENTED_EDGE('',*,*,#352,.F.);
#2059=DIRECTION('',(0.,0.,1.));
#2060=VECTOR('',#2059,1.);
#2061=CARTESIAN_POINT('',(0.654692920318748,0.422946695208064,0.95));
#2062=LINE('',#2061,#2060);
#2063=CARTESIAN_POINT('',(0.654692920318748,0.422946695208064,0.95));
#2064=VERTEX_POINT('',#2063);
#2065=EDGE_CURVE('E691',#2064,#349,#2062,.T.);
#2066=ORIENTED_EDGE('',*,*,#2065,.F.);
#2067=CARTESIAN_POINT('',(0.681936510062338,0.450090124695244,0.95));
#2068=VERTEX_POINT('',#2067);
#2069=EDGE_CURVE('E730',#2064,#2068,#2054,.T.);
#2070=ORIENTED_EDGE('',*,*,#2069,.T.);
#2071=DIRECTION('',(0.,0.,1.));
#2072=VECTOR('',#2071,1.);
#2073=CARTESIAN_POINT('',(0.681936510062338,0.450090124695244,0.95));
#2074=LINE('',#2073,#2072);
#2075=EDGE_CURVE('E740',#2068,#351,#2074,.T.);
#2076=ORIENTED_EDGE('',*,*,#2075,.T.);
#2077=EDGE_LOOP('',(#2058,#2066,#2070,#2076));
#2078=FACE_BOUND('',#2077,.T.);
#2079=ADVANCED_FACE('F1244',(#2078),#2057,.T.);
#2080=CARTESIAN_POINT('',(0.681936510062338,0.450090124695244,0.95));
#2081=CARTESIAN_POINT('',(0.683747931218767,0.449990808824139,0.95));
#2082=CARTESIAN_POINT('',(0.687314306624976,0.449795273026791,0.95));
#2083=CARTESIAN_POINT('',(0.692467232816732,0.448336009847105,0.95));
#2084=CARTESIAN_POINT('',(0.697117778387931,0.445714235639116,0.95));
#2085=CARTESIAN_POINT('',(0.70127598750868,0.442294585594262,0.95));
#2086=CARTESIAN_POINT('',(0.704792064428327,0.438180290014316,0.95));
#2087=CARTESIAN_POINT('',(0.707333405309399,0.433488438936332,0.95));
#2088=CARTESIAN_POINT('',(0.708915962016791,0.428355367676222,0.95));
#2089=CARTESIAN_POINT('',(0.709090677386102,0.424777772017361,0.95));
#2090=CARTESIAN_POINT('',(0.709180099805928,0.422946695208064,0.95));
#2091=B_SPLINE_CURVE_WITH_KNOTS('',3,(#2080,#2081,#2082,#2083,#2084,#2085,#2086,#2087,#2088,
#2089,#2090),.UNSPECIFIED.,.F.,.F.,(4,1,1,1,1,1,1,1,4),(0.,0.127119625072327,0.250276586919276,
0.371969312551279,0.499374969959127,0.626629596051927,0.749350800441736,0.871713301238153,1.),.UNSPECIFIED.);
#2092=DIRECTION('',(0.,0.,1.));
#2093=VECTOR('',#2092,1.);
#2094=SURFACE_OF_LINEAR_EXTRUSION('',#2091,#2093);
#2095=ORIENTED_EDGE('',*,*,#368,.F.);
#2096=ORIENTED_EDGE('',*,*,#2075,.F.);
#2097=CARTESIAN_POINT('',(0.709180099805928,0.422946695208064,0.95));
#2098=VERTEX_POINT('',#2097);
#2099=EDGE_CURVE('E1236',#2068,#2098,#2091,.T.);
#2100=ORIENTED_EDGE('',*,*,#2099,.T.);
#2101=DIRECTION('',(0.,0.,1.));
#2102=VECTOR('',#2101,1.);
#2103=CARTESIAN_POINT('',(0.709180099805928,0.422946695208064,0.95));
#2104=LINE('',#2103,#2102);
#2105=EDGE_CURVE('E738',#2098,#367,#2104,.T.);
#2106=ORIENTED_EDGE('',*,*,#2105,.T.);
#2107=EDGE_LOOP('',(#2095,#2096,#2100,#2106));
#2108=FACE_BOUND('',#2107,.T.);
#2109=ADVANCED_FACE('F1247',(#2108),#2094,.T.);
#2110=CARTESIAN_POINT('',(0.709180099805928,0.422946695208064,0.95));
#2111=CARTESIAN_POINT('',(0.70909126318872,0.421115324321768,0.95));
#2112=CARTESIAN_POINT('',(0.708917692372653,0.417537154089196,0.95));
#2113=CARTESIAN_POINT('',(0.707322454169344,0.412394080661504,0.95));
#2114=CARTESIAN_POINT('',(0.704795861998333,0.4076636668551,0.95));
#2115=CARTESIAN_POINT('',(0.701275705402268,0.403505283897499,0.95));
#2116=CARTESIAN_POINT('',(0.697134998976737,0.400021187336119,0.95));
#2117=CARTESIAN_POINT('',(0.692456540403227,0.397423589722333,0.95));
#2118=CARTESIAN_POINT('',(0.687324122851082,0.39588154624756,0.95));
#2119=CARTESIAN_POINT('',(0.68374965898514,0.395696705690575,0.95));
#2120=CARTESIAN_POINT('',(0.681936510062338,0.395602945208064,0.95));
#2121=B_SPLINE_CURVE_WITH_KNOTS('',3,(#2110,#2111,#2112,#2113,#2114,#2115,#2116,#2117,#2118,
#2119,#2120),.UNSPECIFIED.,.F.,.F.,(4,1,1,1,1,1,1,1,4),(0.,0.127902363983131,0.249898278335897,
0.373279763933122,0.501048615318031,0.628817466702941,0.750145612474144,0.873261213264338,1.),.UNSPECIFIED.);
#2122=DIRECTION('',(0.,0.,1.));
#2123=VECTOR('',#2122,1.);
#2124=SURFACE_OF_LINEAR_EXTRUSION('',#2121,#2123);
#2125=ORIENTED_EDGE('',*,*,#384,.F.);
#2126=ORIENTED_EDGE('',*,*,#2105,.F.);
#2127=CARTESIAN_POINT('',(0.681936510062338,0.395602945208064,0.95));
#2128=VERTEX_POINT('',#2127);
#2129=EDGE_CURVE('E692',#2098,#2128,#2121,.T.);
#2130=ORIENTED_EDGE('',*,*,#2129,.T.);
#2131=DIRECTION('',(0.,0.,1.));
#2132=VECTOR('',#2131,1.);
#2133=CARTESIAN_POINT('',(0.681936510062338,0.395602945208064,0.95));
#2134=LINE('',#2133,#2132);
#2135=EDGE_CURVE('E736',#2128,#383,#2134,.T.);
#2136=ORIENTED_EDGE('',*,*,#2135,.T.);
#2137=EDGE_LOOP('',(#2125,#2126,#2130,#2136));
#2138=FACE_BOUND('',#2137,.T.);
#2139=ADVANCED_FACE('F682',(#2138),#2124,.T.);
#2140=CARTESIAN_POINT('',(0.681936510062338,0.395602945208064,0.95));
#2141=CARTESIAN_POINT('',(0.680122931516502,0.395695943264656,0.95));
#2142=CARTESIAN_POINT('',(0.676547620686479,0.395879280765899,0.95));
#2143=CARTESIAN_POINT('',(0.671407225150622,0.397436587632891,0.95));
#2144=CARTESIAN_POINT('',(0.666694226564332,0.400003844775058,0.95));
#2145=CARTESIAN_POINT('',(0.662552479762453,0.403509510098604,0.95));
#2146=CARTESIAN_POINT('',(0.659016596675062,0.407648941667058,0.95));
#2147=CARTESIAN_POINT('',(0.656561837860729,0.412409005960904,0.95));
#2148=CARTESIAN_POINT('',(0.654951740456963,0.417535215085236,0.95));
#2149=CARTESIAN_POINT('',(0.654780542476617,0.421114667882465,0.95));
#2150=CARTESIAN_POINT('',(0.654692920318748,0.422946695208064,0.95));
#2151=B_SPLINE_CURVE_WITH_KNOTS('',3,(#2140,#2141,#2142,#2143,#2144,#2145,#2146,#2147,#2148,
#2149,#2150),.UNSPECIFIED.,.F.,.F.,(4,1,1,1,1,1,1,1,4),(0.,0.126678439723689,0.249735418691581,
0.372030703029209,0.499738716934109,0.627446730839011,0.750220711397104,0.872158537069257,1.),.UNSPECIFIED.);
#2152=DIRECTION('',(0.,0.,1.));
#2153=VECTOR('',#2152,1.);
#2154=SURFACE_OF_LINEAR_EXTRUSION('',#2151,#2153);
#2155=ORIENTED_EDGE('',*,*,#398,.F.);
#2156=ORIENTED_EDGE('',*,*,#2135,.F.);
#2157=EDGE_CURVE('E686',#2128,#2064,#2151,.T.);
#2158=ORIENTED_EDGE('',*,*,#2157,.T.);
#2159=ORIENTED_EDGE('',*,*,#2065,.T.);
#2160=EDGE_LOOP('',(#2155,#2156,#2158,#2159));
#2161=FACE_BOUND('',#2160,.T.);
#2162=ADVANCED_FACE('F677',(#2161),#2154,.T.);
#2163=CARTESIAN_POINT('',(0.662660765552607,0.442182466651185,0.95));
#2164=DIRECTION('',(9.22291813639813E-13,-1.62788402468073E-13,1.));
#2165=DIRECTION('',(1.,0.,-9.22291813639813E-13));
#2166=AXIS2_PLACEMENT_3D('',#2163,#2164,#2165);
#2167=PLANE('',#2166);
#2168=ORIENTED_EDGE('',*,*,#2069,.F.);
#2169=ORIENTED_EDGE('',*,*,#2157,.F.);
#2170=ORIENTED_EDGE('',*,*,#2129,.F.);
#2171=ORIENTED_EDGE('',*,*,#2099,.F.);
#2172=EDGE_LOOP('',(#2168,#2169,#2170,#2171));
#2173=FACE_BOUND('',#2172,.T.);
#2174=ADVANCED_FACE('F672',(#2173),#2167,.T.);
#2175=CARTESIAN_POINT('',(0.750846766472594,0.422946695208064,0.95));
#2176=CARTESIAN_POINT('',(0.75093496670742,0.424778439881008,0.95));
#2177=CARTESIAN_POINT('',(0.751107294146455,0.428357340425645,0.95));
#2178=CARTESIAN_POINT('',(0.752704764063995,0.433473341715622,0.95));
#2179=CARTESIAN_POINT('',(0.755174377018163,0.438195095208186,0.95));
#2180=CARTESIAN_POINT('',(0.758706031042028,0.442290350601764,0.95));
#2181=CARTESIAN_POINT('',(0.76286538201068,0.445731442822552,0.95));
#2182=CARTESIAN_POINT('',(0.767550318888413,0.448323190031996,0.95));
#2183=CARTESIAN_POINT('',(0.772711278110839,0.449797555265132,0.95));
#2184=CARTESIAN_POINT('',(0.77627850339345,0.449991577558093,0.95));
#2185=CARTESIAN_POINT('',(0.778090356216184,0.450090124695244,0.95));
#2186=B_SPLINE_CURVE_WITH_KNOTS('',3,(#2175,#2176,#2177,#2178,#2179,#2180,#2181,#2182,#2183,
#2184,#2185),.UNSPECIFIED.,.F.,.F.,(4,1,1,1,1,1,1,1,4),(0.,0.128226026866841,0.250530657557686,
0.372638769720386,0.499833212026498,0.627178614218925,0.749841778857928,0.872940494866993,1.),.UNSPECIFIED.);
#2187=DIRECTION('',(0.,0.,1.));
#2188=VECTOR('',#2187,1.);
#2189=SURFACE_OF_LINEAR_EXTRUSION('',#2186,#2188);
#2190=ORIENTED_EDGE('',*,*,#607,.F.);
#2191=DIRECTION('',(0.,0.,1.));
#2192=VECTOR('',#2191,1.);
#2193=CARTESIAN_POINT('',(0.750846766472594,0.422946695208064,0.95));
#2194=LINE('',#2193,#2192);
#2195=CARTESIAN_POINT('',(0.750846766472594,0.422946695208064,0.95));
#2196=VERTEX_POINT('',#2195);
#2197=EDGE_CURVE('E1186',#2196,#604,#2194,.T.);
#2198=ORIENTED_EDGE('',*,*,#2197,.F.);
#2199=CARTESIAN_POINT('',(0.778090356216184,0.450090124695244,0.95));
#2200=VERTEX_POINT('',#2199);
#2201=EDGE_CURVE('E651',#2196,#2200,#2186,.T.);
#2202=ORIENTED_EDGE('',*,*,#2201,.T.);
#2203=DIRECTION('',(0.,0.,1.));
#2204=VECTOR('',#2203,1.);
#2205=CARTESIAN_POINT('',(0.778090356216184,0.450090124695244,0.95));
#2206=LINE('',#2205,#2204);
#2207=EDGE_CURVE('E706',#2200,#606,#2206,.T.);
#2208=ORIENTED_EDGE('',*,*,#2207,.T.);
#2209=EDGE_LOOP('',(#2190,#2198,#2202,#2208));
#2210=FACE_BOUND('',#2209,.T.);
#2211=ADVANCED_FACE('F667',(#2210),#2189,.T.);
#2212=CARTESIAN_POINT('',(0.778090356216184,0.450090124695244,0.95));
#2213=CARTESIAN_POINT('',(0.779901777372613,0.449990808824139,0.95));
#2214=CARTESIAN_POINT('',(0.783468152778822,0.449795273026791,0.95));
#2215=CARTESIAN_POINT('',(0.788621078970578,0.448336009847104,0.95));
#2216=CARTESIAN_POINT('',(0.793271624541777,0.445714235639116,0.95));
#2217=CARTESIAN_POINT('',(0.797429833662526,0.442294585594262,0.95));
#2218=CARTESIAN_POINT('',(0.800945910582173,0.438180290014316,0.95));
#2219=CARTESIAN_POINT('',(0.803487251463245,0.433488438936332,0.95));
#2220=CARTESIAN_POINT('',(0.805069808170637,0.428355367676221,0.95));
#2221=CARTESIAN_POINT('',(0.805244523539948,0.424777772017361,0.95));
#2222=CARTESIAN_POINT('',(0.805333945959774,0.422946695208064,0.95));
#2223=B_SPLINE_CURVE_WITH_KNOTS('',3,(#2212,#2213,#2214,#2215,#2216,#2217,#2218,#2219,#2220,
#2221,#2222),.UNSPECIFIED.,.F.,.F.,(4,1,1,1,1,1,1,1,4),(0.,0.12711962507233,0.250276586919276,
0.371969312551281,0.499374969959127,0.626629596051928,0.749350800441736,0.871713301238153,1.),.UNSPECIFIED.);
#2224=DIRECTION('',(0.,0.,1.));
#2225=VECTOR('',#2224,1.);
#2226=SURFACE_OF_LINEAR_EXTRUSION('',#2223,#2225);
#2227=ORIENTED_EDGE('',*,*,#623,.F.);
#2228=ORIENTED_EDGE('',*,*,#2207,.F.);
#2229=CARTESIAN_POINT('',(0.805333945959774,0.422946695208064,0.95));
#2230=VERTEX_POINT('',#2229);
#2231=EDGE_CURVE('E657',#2200,#2230,#2223,.T.);
#2232=ORIENTED_EDGE('',*,*,#2231,.T.);
#2233=DIRECTION('',(0.,0.,1.));
#2234=VECTOR('',#2233,1.);
#2235=CARTESIAN_POINT('',(0.805333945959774,0.422946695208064,0.95));
#2236=LINE('',#2235,#2234);
#2237=EDGE_CURVE('E1228',#2230,#622,#2236,.T.);
#2238=ORIENTED_EDGE('',*,*,#2237,.T.);
#2239=EDGE_LOOP('',(#2227,#2228,#2232,#2238));
#2240=FACE_BOUND('',#2239,.T.);
#2241=ADVANCED_FACE('F671',(#2240),#2226,.T.);
#2242=CARTESIAN_POINT('',(0.805333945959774,0.422946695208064,0.95));
#2243=CARTESIAN_POINT('',(0.805245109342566,0.421115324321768,0.95));
#2244=CARTESIAN_POINT('',(0.805071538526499,0.417537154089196,0.95));
#2245=CARTESIAN_POINT('',(0.80347630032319,0.412394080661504,0.95));
#2246=CARTESIAN_POINT('',(0.800949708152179,0.4076636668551,0.95));
#2247=CARTESIAN_POINT('',(0.797429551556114,0.403505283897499,0.95));
#2248=CARTESIAN_POINT('',(0.793288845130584,0.400021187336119,0.95));
#2249=CARTESIAN_POINT('',(0.788610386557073,0.397423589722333,0.95));
#2250=CARTESIAN_POINT('',(0.783477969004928,0.39588154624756,0.95));
#2251=CARTESIAN_POINT('',(0.779903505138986,0.395696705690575,0.95));
#2252=CARTESIAN_POINT('',(0.778090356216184,0.395602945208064,0.95));
#2253=B_SPLINE_CURVE_WITH_KNOTS('',3,(#2242,#2243,#2244,#2245,#2246,#2247,#2248,#2249,#2250,
#2251,#2252),.UNSPECIFIED.,.F.,.F.,(4,1,1,1,1,1,1,1,4),(0.,0.127902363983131,0.249898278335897,
0.373279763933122,0.501048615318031,0.628817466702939,0.750145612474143,0.873261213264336,1.),.UNSPECIFIED.);
#2254=DIRECTION('',(0.,0.,1.));
#2255=VECTOR('',#2254,1.);
#2256=SURFACE_OF_LINEAR_EXTRUSION('',#2253,#2255);
#2257=ORIENTED_EDGE('',*,*,#639,.F.);
#2258=ORIENTED_EDGE('',*,*,#2237,.F.);
#2259=CARTESIAN_POINT('',(0.778090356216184,0.395602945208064,0.95));
#2260=VERTEX_POINT('',#2259);
#2261=EDGE_CURVE('E1187',#2230,#2260,#2253,.T.);
#2262=ORIENTED_EDGE('',*,*,#2261,.T.);
#2263=DIRECTION('',(0.,0.,1.));
#2264=VECTOR('',#2263,1.);
#2265=CARTESIAN_POINT('',(0.778090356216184,0.395602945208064,0.95));
#2266=LINE('',#2265,#2264);
#2267=EDGE_CURVE('E1226',#2260,#638,#2266,.T.);
#2268=ORIENTED_EDGE('',*,*,#2267,.T.);
#2269=EDGE_LOOP('',(#2257,#2258,#2262,#2268));
#2270=FACE_BOUND('',#2269,.T.);
#2271=ADVANCED_FACE('F1179',(#2270),#2256,.T.);
#2272=CARTESIAN_POINT('',(0.778090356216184,0.395602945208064,0.95));
#2273=CARTESIAN_POINT('',(0.776276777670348,0.395695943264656,0.95));
#2274=CARTESIAN_POINT('',(0.772701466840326,0.395879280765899,0.95));
#2275=CARTESIAN_POINT('',(0.767561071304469,0.397436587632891,0.95));
#2276=CARTESIAN_POINT('',(0.762848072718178,0.400003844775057,0.95));
#2277=CARTESIAN_POINT('',(0.7587063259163,0.403509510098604,0.95));
#2278=CARTESIAN_POINT('',(0.755170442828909,0.407648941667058,0.95));
#2279=CARTESIAN_POINT('',(0.752715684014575,0.412409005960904,0.95));
#2280=CARTESIAN_POINT('',(0.75110558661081,0.417535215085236,0.95));
#2281=CARTESIAN_POINT('',(0.750934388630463,0.421114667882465,0.95));
#2282=CARTESIAN_POINT('',(0.750846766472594,0.422946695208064,0.95));
#2283=B_SPLINE_CURVE_WITH_KNOTS('',3,(#2272,#2273,#2274,#2275,#2276,#2277,#2278,#2279,#2280,
#2281,#2282),.UNSPECIFIED.,.F.,.F.,(4,1,1,1,1,1,1,1,4),(0.,0.126678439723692,0.249735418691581,
0.372030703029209,0.499738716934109,0.62744673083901,0.750220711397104,0.872158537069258,1.),.UNSPECIFIED.);
#2284=DIRECTION('',(0.,0.,1.));
#2285=VECTOR('',#2284,1.);
#2286=SURFACE_OF_LINEAR_EXTRUSION('',#2283,#2285);
#2287=ORIENTED_EDGE('',*,*,#653,.F.);
#2288=ORIENTED_EDGE('',*,*,#2267,.F.);
#2289=EDGE_CURVE('E1181',#2260,#2196,#2283,.T.);
#2290=ORIENTED_EDGE('',*,*,#2289,.T.);
#2291=ORIENTED_EDGE('',*,*,#2197,.T.);
#2292=EDGE_LOOP('',(#2287,#2288,#2290,#2291));
#2293=FACE_BOUND('',#2292,.T.);
#2294=ADVANCED_FACE('F1175',(#2293),#2286,.T.);
#2295=CARTESIAN_POINT('',(0.758814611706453,0.442182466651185,0.95));
#2296=DIRECTION('',(0.,0.,1.));
#2297=DIRECTION('',(1.,0.,0.));
#2298=AXIS2_PLACEMENT_3D('',#2295,#2296,#2297);
#2299=PLANE('',#2298);
#2300=ORIENTED_EDGE('',*,*,#2201,.F.);
#2301=ORIENTED_EDGE('',*,*,#2289,.F.);
#2302=ORIENTED_EDGE('',*,*,#2261,.F.);
#2303=ORIENTED_EDGE('',*,*,#2231,.F.);
#2304=EDGE_LOOP('',(#2300,#2301,#2302,#2303));
#2305=FACE_BOUND('',#2304,.T.);
#2306=ADVANCED_FACE('F1172',(#2305),#2299,.T.);
#2307=CARTESIAN_POINT('',(0.05,0.381052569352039,0.524927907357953));
#2308=DIRECTION('',(0.,0.853354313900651,-0.521331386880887));
#2309=DIRECTION('',(0.,0.521331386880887,0.853354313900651));
#2310=AXIS2_PLACEMENT_3D('',#2307,#2308,#2309);
#2311=PLANE('',#2310);
#2312=ORIENTED_EDGE('',*,*,#98,.F.);
#2313=DIRECTION('',(-1.,0.,0.));
#2314=VECTOR('',#2313,1.);
#2315=CARTESIAN_POINT('',(0.05,0.381052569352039,0.524927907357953));
#2316=LINE('',#2315,#2314);
#2317=CARTESIAN_POINT('',(0.05,0.381052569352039,0.524927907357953));
#2318=VERTEX_POINT('',#2317);
#2319=EDGE_CURVE('E605',#2318,#95,#2316,.T.);
#2320=ORIENTED_EDGE('',*,*,#2319,.F.);
#2321=DIRECTION('',(0.,-0.521331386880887,-0.853354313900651));
#2322=VECTOR('',#2321,1.);
#2323=CARTESIAN_POINT('',(0.05,0.381052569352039,0.524927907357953));
#2324=LINE('',#2323,#2322);
#2325=CARTESIAN_POINT('',(0.05,0.300924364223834,0.393768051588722));
#2326=VERTEX_POINT('',#2325);
#2327=EDGE_CURVE('E585',#2318,#2326,#2324,.T.);
#2328=ORIENTED_EDGE('',*,*,#2327,.T.);
#2329=DIRECTION('',(-1.,0.,0.));
#2330=VECTOR('',#2329,1.);
#2331=CARTESIAN_POINT('',(0.05,0.300924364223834,0.393768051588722));
#2332=LINE('',#2331,#2330);
#2333=EDGE_CURVE('E647',#2326,#97,#2332,.T.);
#2334=ORIENTED_EDGE('',*,*,#2333,.T.);
#2335=EDGE_LOOP('',(#2312,#2320,#2328,#2334));
#2336=FACE_BOUND('',#2335,.T.);
#2337=ADVANCED_FACE('F1109',(#2336),#2311,.T.);
#2338=CARTESIAN_POINT('',(0.05,0.300924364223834,0.393768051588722));
#2339=DIRECTION('',(0.,0.,1.));
#2340=DIRECTION('',(1.,0.,0.));
#2341=AXIS2_PLACEMENT_3D('',#2338,#2339,#2340);
#2342=PLANE('',#2341);
#2343=ORIENTED_EDGE('',*,*,#106,.F.);
#2344=ORIENTED_EDGE('',*,*,#2333,.F.);
#2345=DIRECTION('',(0.,1.,0.));
#2346=VECTOR('',#2345,1.);
#2347=CARTESIAN_POINT('',(0.05,0.300924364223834,0.393768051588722));
#2348=LINE('',#2347,#2346);
#2349=CARTESIAN_POINT('',(0.05,0.326615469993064,0.393768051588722));
#2350=VERTEX_POINT('',#2349);
#2351=EDGE_CURVE('E588',#2326,#2350,#2348,.T.);
#2352=ORIENTED_EDGE('',*,*,#2351,.T.);
#2353=DIRECTION('',(-1.,0.,0.));
#2354=VECTOR('',#2353,1.);
#2355=CARTESIAN_POINT('',(0.05,0.326615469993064,0.393768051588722));
#2356=LINE('',#2355,#2354);
#2357=EDGE_CURVE('E645',#2350,#105,#2356,.T.);
#2358=ORIENTED_EDGE('',*,*,#2357,.T.);
#2359=EDGE_LOOP('',(#2343,#2344,#2352,#2358));
#2360=FACE_BOUND('',#2359,.T.);
#2361=ADVANCED_FACE('F1122',(#2360),#2342,.T.);
#2362=CARTESIAN_POINT('',(0.05,0.326615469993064,0.393768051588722));
#2363=DIRECTION('',(0.,-0.853075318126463,0.521787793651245));
#2364=DIRECTION('',(0.,-0.521787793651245,-0.853075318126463));
#2365=AXIS2_PLACEMENT_3D('',#2362,#2363,#2364);
#2366=PLANE('',#2365);
#2367=ORIENTED_EDGE('',*,*,#114,.F.);
#2368=ORIENTED_EDGE('',*,*,#2357,.F.);
#2369=DIRECTION('',(0.,0.521787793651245,0.853075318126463));
#2370=VECTOR('',#2369,1.);
#2371=CARTESIAN_POINT('',(0.05,0.326615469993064,0.393768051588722));
#2372=LINE('',#2371,#2370);
#2373=CARTESIAN_POINT('',(0.05,0.392320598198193,0.501189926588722));
#2374=VERTEX_POINT('',#2373);
#2375=EDGE_CURVE('E591',#2350,#2374,#2372,.T.);
#2376=ORIENTED_EDGE('',*,*,#2375,.T.);
#2377=DIRECTION('',(-1.,0.,0.));
#2378=VECTOR('',#2377,1.);
#2379=CARTESIAN_POINT('',(0.05,0.392320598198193,0.501189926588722));
#2380=LINE('',#2379,#2378);
#2381=EDGE_CURVE('E643',#2374,#113,#2380,.T.);
#2382=ORIENTED_EDGE('',*,*,#2381,.T.);
#2383=EDGE_LOOP('',(#2367,#2368,#2376,#2382));
#2384=FACE_BOUND('',#2383,.T.);
#2385=ADVANCED_FACE('F1126',(#2384),#2366,.T.);
#2386=CARTESIAN_POINT('',(0.05,0.392320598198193,0.501189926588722));
#2387=DIRECTION('',(0.,0.853429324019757,0.521208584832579));
#2388=DIRECTION('',(0.,-0.521208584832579,0.853429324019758));
#2389=AXIS2_PLACEMENT_3D('',#2386,#2387,#2388);
#2390=PLANE('',#2389);
#2391=ORIENTED_EDGE('',*,*,#122,.F.);
#2392=ORIENTED_EDGE('',*,*,#2381,.F.);
#2393=DIRECTION('',(0.,0.521208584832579,-0.853429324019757));
#2394=VECTOR('',#2393,1.);
#2395=CARTESIAN_POINT('',(0.05,0.392320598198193,0.501189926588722));
#2396=LINE('',#2395,#2394);
#2397=CARTESIAN_POINT('',(0.05,0.45792556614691,0.393768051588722));
#2398=VERTEX_POINT('',#2397);
#2399=EDGE_CURVE('E593',#2374,#2398,#2396,.T.);
#2400=ORIENTED_EDGE('',*,*,#2399,.T.);
#2401=DIRECTION('',(-1.,0.,0.));
#2402=VECTOR('',#2401,1.);
#2403=CARTESIAN_POINT('',(0.05,0.45792556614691,0.393768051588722));
#2404=LINE('',#2403,#2402);
#2405=EDGE_CURVE('E641',#2398,#121,#2404,.T.);
#2406=ORIENTED_EDGE('',*,*,#2405,.T.);
#2407=EDGE_LOOP('',(#2391,#2392,#2400,#2406));
#2408=FACE_BOUND('',#2407,.T.);
#2409=ADVANCED_FACE('F1131',(#2408),#2390,.T.);
#2410=CARTESIAN_POINT('',(0.05,0.45792556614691,0.393768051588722));
#2411=DIRECTION('',(0.,0.,1.));
#2412=DIRECTION('',(1.,0.,0.));
#2413=AXIS2_PLACEMENT_3D('',#2410,#2411,#2412);
#2414=PLANE('',#2413);
#2415=ORIENTED_EDGE('',*,*,#130,.F.);
#2416=ORIENTED_EDGE('',*,*,#2405,.F.);
#2417=DIRECTION('',(0.,1.,0.));
#2418=VECTOR('',#2417,1.);
#2419=CARTESIAN_POINT('',(0.05,0.45792556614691,0.393768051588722));
#2420=LINE('',#2419,#2418);
#2421=CARTESIAN_POINT('',(0.05,0.483616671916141,0.393768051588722));
#2422=VERTEX_POINT('',#2421);
#2423=EDGE_CURVE('E595',#2398,#2422,#2420,.T.);
#2424=ORIENTED_EDGE('',*,*,#2423,.T.);
#2425=DIRECTION('',(-1.,0.,0.));
#2426=VECTOR('',#2425,1.);
#2427=CARTESIAN_POINT('',(0.05,0.483616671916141,0.393768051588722));
#2428=LINE('',#2427,#2426);
#2429=EDGE_CURVE('E639',#2422,#129,#2428,.T.);
#2430=ORIENTED_EDGE('',*,*,#2429,.T.);
#2431=EDGE_LOOP('',(#2415,#2416,#2424,#2430));
#2432=FACE_BOUND('',#2431,.T.);
#2433=ADVANCED_FACE('F1136',(#2432),#2414,.T.);
#2434=CARTESIAN_POINT('',(0.05,0.483616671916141,0.393768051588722));
#2435=DIRECTION('',(0.,-0.853354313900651,-0.521331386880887));
#2436=DIRECTION('',(0.,0.521331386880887,-0.853354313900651));
#2437=AXIS2_PLACEMENT_3D('',#2434,#2435,#2436);
#2438=PLANE('',#2437);
#2439=ORIENTED_EDGE('',*,*,#138,.F.);
#2440=ORIENTED_EDGE('',*,*,#2429,.F.);
#2441=DIRECTION('',(0.,-0.521331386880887,0.853354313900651));
#2442=VECTOR('',#2441,1.);
#2443=CARTESIAN_POINT('',(0.05,0.483616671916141,0.393768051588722));
#2444=LINE('',#2443,#2442);
#2445=CARTESIAN_POINT('',(0.05,0.403488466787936,0.524927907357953));
#2446=VERTEX_POINT('',#2445);
#2447=EDGE_CURVE('E597',#2422,#2446,#2444,.T.);
#2448=ORIENTED_EDGE('',*,*,#2447,.T.);
#2449=DIRECTION('',(-1.,0.,0.));
#2450=VECTOR('',#2449,1.);
#2451=CARTESIAN_POINT('',(0.05,0.403488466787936,0.524927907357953));
#2452=LINE('',#2451,#2450);
#2453=EDGE_CURVE('E637',#2446,#137,#2452,.T.);
#2454=ORIENTED_EDGE('',*,*,#2453,.T.);
#2455=EDGE_LOOP('',(#2439,#2440,#2448,#2454));
#2456=FACE_BOUND('',#2455,.T.);
#2457=ADVANCED_FACE('F1141',(#2456),#2438,.T.);
#2458=CARTESIAN_POINT('',(0.05,0.403488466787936,0.524927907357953));
#2459=DIRECTION('',(0.,-1.,0.));
#2460=DIRECTION('',(0.,0.,-1.));
#2461=AXIS2_PLACEMENT_3D('',#2458,#2459,#2460);
#2462=PLANE('',#2461);
#2463=ORIENTED_EDGE('',*,*,#146,.F.);
#2464=ORIENTED_EDGE('',*,*,#2453,.F.);
#2465=DIRECTION('',(0.,0.,1.));
#2466=VECTOR('',#2465,1.);
#2467=CARTESIAN_POINT('',(0.05,0.403488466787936,0.524927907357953));
#2468=LINE('',#2467,#2466);
#2469=CARTESIAN_POINT('',(0.05,0.403488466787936,0.643768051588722));
#2470=VERTEX_POINT('',#2469);
#2471=EDGE_CURVE('E599',#2446,#2470,#2468,.T.);
#2472=ORIENTED_EDGE('',*,*,#2471,.T.);
#2473=DIRECTION('',(-1.,0.,0.));
#2474=VECTOR('',#2473,1.);
#2475=CARTESIAN_POINT('',(0.05,0.403488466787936,0.643768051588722));
#2476=LINE('',#2475,#2474);
#2477=EDGE_CURVE('E635',#2470,#145,#2476,.T.);
#2478=ORIENTED_EDGE('',*,*,#2477,.T.);
#2479=EDGE_LOOP('',(#2463,#2464,#2472,#2478));
#2480=FACE_BOUND('',#2479,.T.);
#2481=ADVANCED_FACE('F1146',(#2480),#2462,.T.);
#2482=CARTESIAN_POINT('',(0.05,0.403488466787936,0.643768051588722));
#2483=DIRECTION('',(0.,0.,-1.));
#2484=DIRECTION('',(-1.,0.,0.));
#2485=AXIS2_PLACEMENT_3D('',#2482,#2483,#2484);
#2486=PLANE('',#2485);
#2487=ORIENTED_EDGE('',*,*,#154,.F.);
#2488=ORIENTED_EDGE('',*,*,#2477,.F.);
#2489=DIRECTION('',(0.,-1.,0.));
#2490=VECTOR('',#2489,1.);
#2491=CARTESIAN_POINT('',(0.05,0.403488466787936,0.643768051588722));
#2492=LINE('',#2491,#2490);
#2493=CARTESIAN_POINT('',(0.05,0.381052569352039,0.643768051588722));
#2494=VERTEX_POINT('',#2493);
#2495=EDGE_CURVE('E601',#2470,#2494,#2492,.T.);
#2496=ORIENTED_EDGE('',*,*,#2495,.T.);
#2497=DIRECTION('',(-1.,0.,0.));
#2498=VECTOR('',#2497,1.);
#2499=CARTESIAN_POINT('',(0.05,0.381052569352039,0.643768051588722));
#2500=LINE('',#2499,#2498);
#2501=EDGE_CURVE('E633',#2494,#153,#2500,.T.);
#2502=ORIENTED_EDGE('',*,*,#2501,.T.);
#2503=EDGE_LOOP('',(#2487,#2488,#2496,#2502));
#2504=FACE_BOUND('',#2503,.T.);
#2505=ADVANCED_FACE('F1149',(#2504),#2486,.T.);
#2506=CARTESIAN_POINT('',(0.05,0.381052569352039,0.643768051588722));
#2507=DIRECTION('',(0.,1.,0.));
#2508=DIRECTION('',(0.,0.,1.));
#2509=AXIS2_PLACEMENT_3D('',#2506,#2507,#2508);
#2510=PLANE('',#2509);
#2511=ORIENTED_EDGE('',*,*,#160,.F.);
#2512=ORIENTED_EDGE('',*,*,#2501,.F.);
#2513=DIRECTION('',(0.,0.,-1.));
#2514=VECTOR('',#2513,1.);
#2515=CARTESIAN_POINT('',(0.05,0.381052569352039,0.643768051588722));
#2516=LINE('',#2515,#2514);
#2517=EDGE_CURVE('E603',#2494,#2318,#2516,.T.);
#2518=ORIENTED_EDGE('',*,*,#2517,.T.);
#2519=ORIENTED_EDGE('',*,*,#2319,.T.);
#2520=EDGE_LOOP('',(#2511,#2512,#2518,#2519));
#2521=FACE_BOUND('',#2520,.T.);
#2522=ADVANCED_FACE('F1113',(#2521),#2510,.T.);
#2523=CARTESIAN_POINT('',(0.05,0.,0.));
#2524=DIRECTION('',(-1.,0.,0.));
#2525=DIRECTION('',(0.,0.,1.));
#2526=AXIS2_PLACEMENT_3D('',#2523,#2524,#2525);
#2527=PLANE('',#2526);
#2528=ORIENTED_EDGE('',*,*,#2327,.F.);
#2529=ORIENTED_EDGE('',*,*,#2517,.F.);
#2530=ORIENTED_EDGE('',*,*,#2495,.F.);
#2531=ORIENTED_EDGE('',*,*,#2471,.F.);
#2532=ORIENTED_EDGE('',*,*,#2447,.F.);
#2533=ORIENTED_EDGE('',*,*,#2423,.F.);
#2534=ORIENTED_EDGE('',*,*,#2399,.F.);
#2535=ORIENTED_EDGE('',*,*,#2375,.F.);
#2536=ORIENTED_EDGE('',*,*,#2351,.F.);
#2537=EDGE_LOOP('',(#2528,#2529,#2530,#2531,#2532,#2533,#2534,#2535,#2536));
#2538=FACE_BOUND('',#2537,.T.);
#2539=ADVANCED_FACE('F1118',(#2538),#2527,.T.);
#2540=CARTESIAN_POINT('',(0.05,0.462146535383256,0.605767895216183));
#2541=CARTESIAN_POINT('',(0.05,0.463557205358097,0.605843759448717));
#2542=CARTESIAN_POINT('',(0.05,0.466311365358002,0.605991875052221));
#2543=CARTESIAN_POINT('',(0.05,0.470254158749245,0.607190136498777));
#2544=CARTESIAN_POINT('',(0.05,0.473837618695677,0.609145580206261));
#2545=CARTESIAN_POINT('',(0.05,0.477008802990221,0.611788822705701));
#2546=CARTESIAN_POINT('',(0.05,0.479665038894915,0.614969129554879));
#2547=CARTESIAN_POINT('',(0.05,0.481598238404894,0.618561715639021));
#2548=CARTESIAN_POINT('',(0.05,0.48274398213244,0.622493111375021));
#2549=CARTESIAN_POINT('',(0.05,0.482899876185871,0.625208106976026));
#2550=CARTESIAN_POINT('',(0.05,0.482979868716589,0.626601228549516));
#2551=B_SPLINE_CURVE_WITH_KNOTS('',3,(#2540,#2541,#2542,#2543,#2544,#2545,#2546,#2547,#2548,
#2549,#2550),.UNSPECIFIED.,.F.,.F.,(4,1,1,1,1,1,1,1,4),(0.,0.129096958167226,0.25204596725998,
0.373904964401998,0.501037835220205,0.628170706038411,0.751376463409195,0.872426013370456,1.),.UNSPECIFIED.);
#2552=DIRECTION('',(-1.,0.,0.));
#2553=VECTOR('',#2552,1.);
#2554=SURFACE_OF_LINEAR_EXTRUSION('',#2551,#2553);
#2555=ORIENTED_EDGE('',*,*,#214,.F.);
#2556=DIRECTION('',(-1.,0.,0.));
#2557=VECTOR('',#2556,1.);
#2558=CARTESIAN_POINT('',(0.05,0.462146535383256,0.605767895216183));
#2559=LINE('',#2558,#2557);
#2560=CARTESIAN_POINT('',(0.05,0.462146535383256,0.605767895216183));
#2561=VERTEX_POINT('',#2560);
#2562=EDGE_CURVE('E532',#2561,#211,#2559,.T.);
#2563=ORIENTED_EDGE('',*,*,#2562,.F.);
#2564=CARTESIAN_POINT('',(0.05,0.482979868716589,0.626601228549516));
#2565=VERTEX_POINT('',#2564);
#2566=EDGE_CURVE('E571',#2561,#2565,#2551,.T.);
#2567=ORIENTED_EDGE('',*,*,#2566,.T.);
#2568=DIRECTION('',(-1.,0.,0.));
#2569=VECTOR('',#2568,1.);
#2570=CARTESIAN_POINT('',(0.05,0.482979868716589,0.626601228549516));
#2571=LINE('',#2570,#2569);
#2572=EDGE_CURVE('E581',#2565,#213,#2571,.T.);
#2573=ORIENTED_EDGE('',*,*,#2572,.T.);
#2574=EDGE_LOOP('',(#2555,#2563,#2567,#2573));
#2575=FACE_BOUND('',#2574,.T.);
#2576=ADVANCED_FACE('F1812',(#2575),#2554,.T.);
#2577=CARTESIAN_POINT('',(0.05,0.482979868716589,0.626601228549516));
#2578=CARTESIAN_POINT('',(0.05,0.4828971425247,0.627993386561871));
#2579=CARTESIAN_POINT('',(0.05,0.482734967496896,0.630722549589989));
#2580=CARTESIAN_POINT('',(0.05,0.481622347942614,0.634668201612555));
#2581=CARTESIAN_POINT('',(0.05,0.479646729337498,0.638239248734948));
#2582=CARTESIAN_POINT('',(0.05,0.477013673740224,0.64142012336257));
#2583=CARTESIAN_POINT('',(0.05,0.47382112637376,0.644042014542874));
#2584=CARTESIAN_POINT('',(0.05,0.470278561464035,0.64608803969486));
#2585=CARTESIAN_POINT('',(0.05,0.466299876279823,0.647190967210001));
#2586=CARTESIAN_POINT('',(0.05,0.46355489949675,0.647351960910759));
#2587=CARTESIAN_POINT('',(0.05,0.462146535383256,0.64743456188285));
#2588=B_SPLINE_CURVE_WITH_KNOTS('',3,(#2577,#2578,#2579,#2580,#2581,#2582,#2583,#2584,#2585,
#2586,#2587),.UNSPECIFIED.,.F.,.F.,(4,1,1,1,1,1,1,1,4),(0.,0.127518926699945,0.249985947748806,
0.371792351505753,0.498870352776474,0.625948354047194,0.748491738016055,0.870958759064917,1.),.UNSPECIFIED.);
#2589=DIRECTION('',(-1.,0.,0.));
#2590=VECTOR('',#2589,1.);
#2591=SURFACE_OF_LINEAR_EXTRUSION('',#2588,#2590);
#2592=ORIENTED_EDGE('',*,*,#230,.F.);
#2593=ORIENTED_EDGE('',*,*,#2572,.F.);
#2594=CARTESIAN_POINT('',(0.05,0.462146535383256,0.64743456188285));
#2595=VERTEX_POINT('',#2594);
#2596=EDGE_CURVE('E2049',#2565,#2595,#2588,.T.);
#2597=ORIENTED_EDGE('',*,*,#2596,.T.);
#2598=DIRECTION('',(-1.,0.,0.));
#2599=VECTOR('',#2598,1.);
#2600=CARTESIAN_POINT('',(0.05,0.462146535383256,0.64743456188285));
#2601=LINE('',#2600,#2599);
#2602=EDGE_CURVE('E579',#2595,#229,#2601,.T.);
#2603=ORIENTED_EDGE('',*,*,#2602,.T.);
#2604=EDGE_LOOP('',(#2592,#2593,#2597,#2603));
#2605=FACE_BOUND('',#2604,.T.);
#2606=ADVANCED_FACE('F1820',(#2605),#2591,.T.);
#2607=CARTESIAN_POINT('',(0.05,0.462146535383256,0.64743456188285));
#2608=CARTESIAN_POINT('',(0.05,0.460772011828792,0.647349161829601));
#2609=CARTESIAN_POINT('',(0.05,0.458061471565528,0.647180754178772));
#2610=CARTESIAN_POINT('',(0.05,0.45411279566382,0.646090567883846));
#2611=CARTESIAN_POINT('',(0.05,0.450568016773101,0.644026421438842));
#2612=CARTESIAN_POINT('',(0.05,0.447332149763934,0.641438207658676));
#2613=CARTESIAN_POINT('',(0.05,0.444693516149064,0.638238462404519));
#2614=CARTESIAN_POINT('',(0.05,0.442734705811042,0.63465975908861));
#2615=CARTESIAN_POINT('',(0.05,0.441542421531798,0.63073181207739));
#2616=CARTESIAN_POINT('',(0.05,0.441390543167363,0.627994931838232));
#2617=CARTESIAN_POINT('',(0.05,0.441313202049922,0.626601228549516));
#2618=B_SPLINE_CURVE_WITH_KNOTS('',3,(#2607,#2608,#2609,#2610,#2611,#2612,#2613,#2614,#2615,
#2616,#2617),.UNSPECIFIED.,.F.,.F.,(4,1,1,1,1,1,1,1,4),(0.,0.126177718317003,0.248820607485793,
0.371539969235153,0.499983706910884,0.627244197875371,0.749225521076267,0.87229795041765,1.),.UNSPECIFIED.);
#2619=DIRECTION('',(-1.,0.,0.));
#2620=VECTOR('',#2619,1.);
#2621=SURFACE_OF_LINEAR_EXTRUSION('',#2618,#2620);
#2622=ORIENTED_EDGE('',*,*,#246,.F.);
#2623=ORIENTED_EDGE('',*,*,#2602,.F.);
#2624=CARTESIAN_POINT('',(0.05,0.441313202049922,0.626601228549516));
#2625=VERTEX_POINT('',#2624);
#2626=EDGE_CURVE('E533',#2595,#2625,#2618,.T.);
#2627=ORIENTED_EDGE('',*,*,#2626,.T.);
#2628=DIRECTION('',(-1.,0.,0.));
#2629=VECTOR('',#2628,1.);
#2630=CARTESIAN_POINT('',(0.05,0.441313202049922,0.626601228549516));
#2631=LINE('',#2630,#2629);
#2632=EDGE_CURVE('E577',#2625,#245,#2631,.T.);
#2633=ORIENTED_EDGE('',*,*,#2632,.T.);
#2634=EDGE_LOOP('',(#2622,#2623,#2627,#2633));
#2635=FACE_BOUND('',#2634,.T.);
#2636=ADVANCED_FACE('F523',(#2635),#2621,.T.);
#2637=CARTESIAN_POINT('',(0.05,0.441313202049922,0.626601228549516));
#2638=CARTESIAN_POINT('',(0.05,0.441387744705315,0.625206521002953));
#2639=CARTESIAN_POINT('',(0.05,0.441533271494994,0.622483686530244));
#2640=CARTESIAN_POINT('',(0.05,0.442759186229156,0.618570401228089));
#2641=CARTESIAN_POINT('',(0.05,0.444675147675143,0.614969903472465));
#2642=CARTESIAN_POINT('',(0.05,0.44733706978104,0.611770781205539));
#2643=CARTESIAN_POINT('',(0.05,0.450551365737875,0.609160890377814));
#2644=CARTESIAN_POINT('',(0.05,0.454137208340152,0.607187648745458));
#2645=CARTESIAN_POINT('',(0.05,0.458050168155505,0.606002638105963));
#2646=CARTESIAN_POINT('',(0.05,0.460769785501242,0.605846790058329));
#2647=CARTESIAN_POINT('',(0.05,0.462146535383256,0.605767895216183));
#2648=B_SPLINE_CURVE_WITH_KNOTS('',3,(#2637,#2638,#2639,#2640,#2641,#2642,#2643,#2644,#2645,
#2646,#2647),.UNSPECIFIED.,.F.,.F.,(4,1,1,1,1,1,1,1,4),(0.,0.127756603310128,0.249414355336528,
0.372796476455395,0.500111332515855,0.628609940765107,0.750643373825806,0.873768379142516,1.),.UNSPECIFIED.);
#2649=DIRECTION('',(-1.,0.,0.));
#2650=VECTOR('',#2649,1.);
#2651=SURFACE_OF_LINEAR_EXTRUSION('',#2648,#2650);
#2652=ORIENTED_EDGE('',*,*,#260,.F.);
#2653=ORIENTED_EDGE('',*,*,#2632,.F.);
#2654=EDGE_CURVE('E527',#2625,#2561,#2648,.T.);
#2655=ORIENTED_EDGE('',*,*,#2654,.T.);
#2656=ORIENTED_EDGE('',*,*,#2562,.T.);
#2657=EDGE_LOOP('',(#2652,#2653,#2655,#2656));
#2658=FACE_BOUND('',#2657,.T.);
#2659=ADVANCED_FACE('F518',(#2658),#2651,.T.);
#2660=CARTESIAN_POINT('',(0.05,0.476896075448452,0.611853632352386));
#2661=DIRECTION('',(-1.,0.,0.));
#2662=DIRECTION('',(0.,0.,1.));
#2663=AXIS2_PLACEMENT_3D('',#2660,#2661,#2662);
#2664=PLANE('',#2663);
#2665=ORIENTED_EDGE('',*,*,#2566,.F.);
#2666=ORIENTED_EDGE('',*,*,#2654,.F.);
#2667=ORIENTED_EDGE('',*,*,#2626,.F.);
#2668=ORIENTED_EDGE('',*,*,#2596,.F.);
#2669=EDGE_LOOP('',(#2665,#2666,#2667,#2668));
#2670=FACE_BOUND('',#2669,.T.);
#2671=ADVANCED_FACE('F514',(#2670),#2664,.T.);
#2672=CARTESIAN_POINT('',(0.05,0.525952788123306,0.604405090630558));
#2673=CARTESIAN_POINT('',(0.05,0.527363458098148,0.604480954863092));
#2674=CARTESIAN_POINT('',(0.05,0.530117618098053,0.604629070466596));
#2675=CARTESIAN_POINT('',(0.05,0.534060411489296,0.605827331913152));
#2676=CARTESIAN_POINT('',(0.05,0.537643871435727,0.607782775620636));
#2677=CARTESIAN_POINT('',(0.05,0.540815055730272,0.610426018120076));
#2678=CARTESIAN_POINT('',(0.05,0.543471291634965,0.613606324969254));
#2679=CARTESIAN_POINT('',(0.05,0.545404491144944,0.617198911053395));
#2680=CARTESIAN_POINT('',(0.05,0.546550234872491,0.621130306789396));
#2681=CARTESIAN_POINT('',(0.05,0.546706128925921,0.623845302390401));
#2682=CARTESIAN_POINT('',(0.05,0.54678612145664,0.625238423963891));
#2683=B_SPLINE_CURVE_WITH_KNOTS('',3,(#2672,#2673,#2674,#2675,#2676,#2677,#2678,#2679,#2680,
#2681,#2682),.UNSPECIFIED.,.F.,.F.,(4,1,1,1,1,1,1,1,4),(0.,0.129096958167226,0.252045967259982,
0.373904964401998,0.501037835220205,0.628170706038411,0.751376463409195,0.872426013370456,1.),.UNSPECIFIED.);
#2684=DIRECTION('',(-1.,0.,0.));
#2685=VECTOR('',#2684,1.);
#2686=SURFACE_OF_LINEAR_EXTRUSION('',#2683,#2685);
#2687=ORIENTED_EDGE('',*,*,#40,.F.);
#2688=DIRECTION('',(-1.,0.,0.));
#2689=VECTOR('',#2688,1.);
#2690=CARTESIAN_POINT('',(0.05,0.525952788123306,0.604405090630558));
#2691=LINE('',#2690,#2689);
#2692=CARTESIAN_POINT('',(0.05,0.525952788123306,0.604405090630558));
#2693=VERTEX_POINT('',#2692);
#2694=EDGE_CURVE('E2005',#2693,#37,#2691,.T.);
#2695=ORIENTED_EDGE('',*,*,#2694,.F.);
#2696=CARTESIAN_POINT('',(0.05,0.54678612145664,0.625238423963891));
#2697=VERTEX_POINT('',#2696);
#2698=EDGE_CURVE('E493',#2693,#2697,#2683,.T.);
#2699=ORIENTED_EDGE('',*,*,#2698,.T.);
#2700=DIRECTION('',(-1.,0.,0.));
#2701=VECTOR('',#2700,1.);
#2702=CARTESIAN_POINT('',(0.05,0.54678612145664,0.625238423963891));
#2703=LINE('',#2702,#2701);
#2704=EDGE_CURVE('E547',#2697,#39,#2703,.T.);
#2705=ORIENTED_EDGE('',*,*,#2704,.T.);
#2706=EDGE_LOOP('',(#2687,#2695,#2699,#2705));
#2707=FACE_BOUND('',#2706,.T.);
#2708=ADVANCED_FACE('F509',(#2707),#2686,.T.);
#2709=CARTESIAN_POINT('',(0.05,0.54678612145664,0.625238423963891));
#2710=CARTESIAN_POINT('',(0.05,0.54670339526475,0.626630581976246));
#2711=CARTESIAN_POINT('',(0.05,0.546541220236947,0.629359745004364));
#2712=CARTESIAN_POINT('',(0.05,0.545428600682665,0.633305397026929));
#2713=CARTESIAN_POINT('',(0.05,0.543452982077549,0.636876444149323));
#2714=CARTESIAN_POINT('',(0.05,0.540819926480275,0.640057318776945));
#2715=CARTESIAN_POINT('',(0.05,0.537627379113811,0.642679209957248));
#2716=CARTESIAN_POINT('',(0.05,0.534084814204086,0.644725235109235));
#2717=CARTESIAN_POINT('',(0.05,0.530106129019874,0.645828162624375));
#2718=CARTESIAN_POINT('',(0.05,0.527361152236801,0.645989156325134));
#2719=CARTESIAN_POINT('',(0.05,0.525952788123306,0.646071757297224));
#2720=B_SPLINE_CURVE_WITH_KNOTS('',3,(#2709,#2710,#2711,#2712,#2713,#2714,#2715,#2716,#2717,
#2718,#2719),.UNSPECIFIED.,.F.,.F.,(4,1,1,1,1,1,1,1,4),(0.,0.127518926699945,0.249985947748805,
0.371792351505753,0.498870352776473,0.625948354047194,0.748491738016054,0.870958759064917,1.),.UNSPECIFIED.);
#2721=DIRECTION('',(-1.,0.,0.));
#2722=VECTOR('',#2721,1.);
#2723=SURFACE_OF_LINEAR_EXTRUSION('',#2720,#2722);
#2724=ORIENTED_EDGE('',*,*,#56,.F.);
#2725=ORIENTED_EDGE('',*,*,#2704,.F.);
#2726=CARTESIAN_POINT('',(0.05,0.525952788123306,0.646071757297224));
#2727=VERTEX_POINT('',#2726);
#2728=EDGE_CURVE('E499',#2697,#2727,#2720,.T.);
#2729=ORIENTED_EDGE('',*,*,#2728,.T.);
#2730=DIRECTION('',(-1.,0.,0.));
#2731=VECTOR('',#2730,1.);
#2732=CARTESIAN_POINT('',(0.05,0.525952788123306,0.646071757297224));
#2733=LINE('',#2732,#2731);
#2734=EDGE_CURVE('E2042',#2727,#55,#2733,.T.);
#2735=ORIENTED_EDGE('',*,*,#2734,.T.);
#2736=EDGE_LOOP('',(#2724,#2725,#2729,#2735));
#2737=FACE_BOUND('',#2736,.T.);
#2738=ADVANCED_FACE('F513',(#2737),#2723,.T.);
#2739=CARTESIAN_POINT('',(0.05,0.525952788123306,0.646071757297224));
#2740=CARTESIAN_POINT('',(0.05,0.524578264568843,0.645986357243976));
#2741=CARTESIAN_POINT('',(0.05,0.521867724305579,0.645817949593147));
#2742=CARTESIAN_POINT('',(0.05,0.517919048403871,0.644727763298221));
#2743=CARTESIAN_POINT('',(0.05,0.514374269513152,0.642663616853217));
#2744=CARTESIAN_POINT('',(0.05,0.511138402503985,0.640075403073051));
#2745=CARTESIAN_POINT('',(0.05,0.508499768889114,0.636875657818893));
#2746=CARTESIAN_POINT('',(0.05,0.506540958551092,0.633296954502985));
#2747=CARTESIAN_POINT('',(0.05,0.505348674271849,0.629369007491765));
#2748=CARTESIAN_POINT('',(0.05,0.505196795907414,0.626632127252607));
#2749=CARTESIAN_POINT('',(0.05,0.505119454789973,0.625238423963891));
#2750=B_SPLINE_CURVE_WITH_KNOTS('',3,(#2739,#2740,#2741,#2742,#2743,#2744,#2745,#2746,#2747,
#2748,#2749),.UNSPECIFIED.,.F.,.F.,(4,1,1,1,1,1,1,1,4),(0.,0.126177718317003,0.248820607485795,
0.371539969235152,0.499983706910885,0.627244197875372,0.749225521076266,0.87229795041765,1.),.UNSPECIFIED.);
#2751=DIRECTION('',(-1.,0.,0.));
#2752=VECTOR('',#2751,1.);
#2753=SURFACE_OF_LINEAR_EXTRUSION('',#2750,#2752);
#2754=ORIENTED_EDGE('',*,*,#72,.F.);
#2755=ORIENTED_EDGE('',*,*,#2734,.F.);
#2756=CARTESIAN_POINT('',(0.05,0.505119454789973,0.625238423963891));
#2757=VERTEX_POINT('',#2756);
#2758=EDGE_CURVE('E2006',#2727,#2757,#2750,.T.);
#2759=ORIENTED_EDGE('',*,*,#2758,.T.);
#2760=DIRECTION('',(-1.,0.,0.));
#2761=VECTOR('',#2760,1.);
#2762=CARTESIAN_POINT('',(0.05,0.505119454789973,0.625238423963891));
#2763=LINE('',#2762,#2761);
#2764=EDGE_CURVE('E2040',#2757,#71,#2763,.T.);
#2765=ORIENTED_EDGE('',*,*,#2764,.T.);
#2766=EDGE_LOOP('',(#2754,#2755,#2759,#2765));
#2767=FACE_BOUND('',#2766,.T.);
#2768=ADVANCED_FACE('F1864',(#2767),#2753,.T.);
#2769=CARTESIAN_POINT('',(0.05,0.505119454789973,0.625238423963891));
#2770=CARTESIAN_POINT('',(0.05,0.505193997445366,0.623843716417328));
#2771=CARTESIAN_POINT('',(0.05,0.505339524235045,0.621120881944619));
#2772=CARTESIAN_POINT('',(0.05,0.506565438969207,0.617207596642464));
#2773=CARTESIAN_POINT('',(0.05,0.508481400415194,0.61360709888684));
#2774=CARTESIAN_POINT('',(0.05,0.511143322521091,0.610407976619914));
#2775=CARTESIAN_POINT('',(0.05,0.514357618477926,0.607798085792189));
#2776=CARTESIAN_POINT('',(0.05,0.517943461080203,0.605824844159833));
#2777=CARTESIAN_POINT('',(0.05,0.521856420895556,0.604639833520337));
#2778=CARTESIAN_POINT('',(0.05,0.524576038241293,0.604483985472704));
#2779=CARTESIAN_POINT('',(0.05,0.525952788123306,0.604405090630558));
#2780=B_SPLINE_CURVE_WITH_KNOTS('',3,(#2769,#2770,#2771,#2772,#2773,#2774,#2775,#2776,#2777,
#2778,#2779),.UNSPECIFIED.,.F.,.F.,(4,1,1,1,1,1,1,1,4),(0.,0.127756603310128,0.249414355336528,
0.372796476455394,0.500111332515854,0.628609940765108,0.750643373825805,0.873768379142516,1.),.UNSPECIFIED.);
#2781=DIRECTION('',(-1.,0.,0.));
#2782=VECTOR('',#2781,1.);
#2783=SURFACE_OF_LINEAR_EXTRUSION('',#2780,#2782);
#2784=ORIENTED_EDGE('',*,*,#86,.F.);
#2785=ORIENTED_EDGE('',*,*,#2764,.F.);
#2786=EDGE_CURVE('E2001',#2757,#2693,#2780,.T.);
#2787=ORIENTED_EDGE('',*,*,#2786,.T.);
#2788=ORIENTED_EDGE('',*,*,#2694,.T.);
#2789=EDGE_LOOP('',(#2784,#2785,#2787,#2788));
#2790=FACE_BOUND('',#2789,.T.);
#2791=ADVANCED_FACE('F1873',(#2790),#2783,.T.);
#2792=CARTESIAN_POINT('',(0.05,0.540702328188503,0.610490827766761));
#2793=DIRECTION('',(-1.,0.,0.));
#2794=DIRECTION('',(0.,0.,1.));
#2795=AXIS2_PLACEMENT_3D('',#2792,#2793,#2794);
#2796=PLANE('',#2795);
#2797=ORIENTED_EDGE('',*,*,#2698,.F.);
#2798=ORIENTED_EDGE('',*,*,#2786,.F.);
#2799=ORIENTED_EDGE('',*,*,#2758,.F.);
#2800=ORIENTED_EDGE('',*,*,#2728,.F.);
#2801=EDGE_LOOP('',(#2797,#2798,#2799,#2800));
#2802=FACE_BOUND('',#2801,.T.);
#2803=ADVANCED_FACE('F1882',(#2802),#2796,.T.);
#2804=CARTESIAN_POINT('',(0.05,0.589940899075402,0.604056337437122));
#2805=CARTESIAN_POINT('',(0.05,0.591351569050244,0.604132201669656));
#2806=CARTESIAN_POINT('',(0.05,0.594105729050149,0.60428031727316));
#2807=CARTESIAN_POINT('',(0.05,0.598048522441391,0.605478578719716));
#2808=CARTESIAN_POINT('',(0.05,0.601631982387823,0.6074340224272));
#2809=CARTESIAN_POINT('',(0.05,0.604803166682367,0.610077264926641));
#2810=CARTESIAN_POINT('',(0.05,0.607459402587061,0.613257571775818));
#2811=CARTESIAN_POINT('',(0.05,0.60939260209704,0.61685015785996));
#2812=CARTESIAN_POINT('',(0.05,0.610538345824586,0.62078155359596));
#2813=CARTESIAN_POINT('',(0.05,0.610694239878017,0.623496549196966));
#2814=CARTESIAN_POINT('',(0.05,0.610774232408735,0.624889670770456));
#2815=B_SPLINE_CURVE_WITH_KNOTS('',3,(#2804,#2805,#2806,#2807,#2808,#2809,#2810,#2811,#2812,
#2813,#2814),.UNSPECIFIED.,.F.,.F.,(4,1,1,1,1,1,1,1,4),(0.,0.129096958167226,0.252045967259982,
0.373904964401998,0.501037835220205,0.628170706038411,0.751376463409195,0.872426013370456,1.),.UNSPECIFIED.);
#2816=DIRECTION('',(-1.,0.,0.));
#2817=VECTOR('',#2816,1.);
#2818=SURFACE_OF_LINEAR_EXTRUSION('',#2815,#2817);
#2819=ORIENTED_EDGE('',*,*,#280,.F.);
#2820=DIRECTION('',(-1.,0.,0.));
#2821=VECTOR('',#2820,1.);
#2822=CARTESIAN_POINT('',(0.05,0.589940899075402,0.604056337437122));
#2823=LINE('',#2822,#2821);
#2824=CARTESIAN_POINT('',(0.05,0.589940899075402,0.604056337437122));
#2825=VERTEX_POINT('',#2824);
#2826=EDGE_CURVE('E479',#2825,#277,#2823,.T.);
#2827=ORIENTED_EDGE('',*,*,#2826,.F.);
#2828=CARTESIAN_POINT('',(0.05,0.610774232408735,0.624889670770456));
#2829=VERTEX_POINT('',#2828);
#2830=EDGE_CURVE('E471',#2825,#2829,#2815,.T.);
#2831=ORIENTED_EDGE('',*,*,#2830,.T.);
#2832=DIRECTION('',(-1.,0.,0.));
#2833=VECTOR('',#2832,1.);
#2834=CARTESIAN_POINT('',(0.05,0.610774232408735,0.624889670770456));
#2835=LINE('',#2834,#2833);
#2836=EDGE_CURVE('E478',#2829,#279,#2835,.T.);
#2837=ORIENTED_EDGE('',*,*,#2836,.T.);
#2838=EDGE_LOOP('',(#2819,#2827,#2831,#2837));
#2839=FACE_BOUND('',#2838,.T.);
#2840=ADVANCED_FACE('F477',(#2839),#2818,.T.);
#2841=CARTESIAN_POINT('',(0.05,0.610774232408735,0.624889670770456));
#2842=CARTESIAN_POINT('',(0.05,0.610691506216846,0.626281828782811));
#2843=CARTESIAN_POINT('',(0.05,0.610529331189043,0.629010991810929));
#2844=CARTESIAN_POINT('',(0.05,0.60941671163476,0.632956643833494));
#2845=CARTESIAN_POINT('',(0.05,0.607441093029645,0.636527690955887));
#2846=CARTESIAN_POINT('',(0.05,0.60480803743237,0.63970856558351));
#2847=CARTESIAN_POINT('',(0.05,0.601615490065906,0.642330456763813));
#2848=CARTESIAN_POINT('',(0.05,0.598072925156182,0.644376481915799));
#2849=CARTESIAN_POINT('',(0.05,0.594094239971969,0.64547940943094));
#2850=CARTESIAN_POINT('',(0.05,0.591349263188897,0.645640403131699));
#2851=CARTESIAN_POINT('',(0.05,0.589940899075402,0.645723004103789));
#2852=B_SPLINE_CURVE_WITH_KNOTS('',3,(#2841,#2842,#2843,#2844,#2845,#2846,#2847,#2848,#2849,
#2850,#2851),.UNSPECIFIED.,.F.,.F.,(4,1,1,1,1,1,1,1,4),(0.,0.127518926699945,0.249985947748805,
0.371792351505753,0.498870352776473,0.625948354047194,0.748491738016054,0.870958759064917,1.),.UNSPECIFIED.);
#2853=DIRECTION('',(-1.,0.,0.));
#2854=VECTOR('',#2853,1.);
#2855=SURFACE_OF_LINEAR_EXTRUSION('',#2852,#2854);
#2856=ORIENTED_EDGE('',*,*,#296,.F.);
#2857=ORIENTED_EDGE('',*,*,#2836,.F.);
#2858=CARTESIAN_POINT('',(0.05,0.589940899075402,0.645723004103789));
#2859=VERTEX_POINT('',#2858);
#2860=EDGE_CURVE('E467',#2829,#2859,#2852,.T.);
#2861=ORIENTED_EDGE('',*,*,#2860,.T.);
#2862=DIRECTION('',(-1.,0.,0.));
#2863=VECTOR('',#2862,1.);
#2864=CARTESIAN_POINT('',(0.05,0.589940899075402,0.645723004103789));
#2865=LINE('',#2864,#2863);
#2866=EDGE_CURVE('E485',#2859,#295,#2865,.T.);
#2867=ORIENTED_EDGE('',*,*,#2866,.T.);
#2868=EDGE_LOOP('',(#2856,#2857,#2861,#2867));
#2869=FACE_BOUND('',#2868,.T.);
#2870=ADVANCED_FACE('F482',(#2869),#2855,.T.);
#2871=CARTESIAN_POINT('',(0.05,0.589940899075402,0.645723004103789));
#2872=CARTESIAN_POINT('',(0.05,0.588566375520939,0.64563760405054));
#2873=CARTESIAN_POINT('',(0.05,0.585855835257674,0.645469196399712));
#2874=CARTESIAN_POINT('',(0.05,0.581907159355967,0.644379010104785));
#2875=CARTESIAN_POINT('',(0.05,0.578362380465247,0.642314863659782));
#2876=CARTESIAN_POINT('',(0.05,0.57512651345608,0.639726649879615));
#2877=CARTESIAN_POINT('',(0.05,0.57248787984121,0.636526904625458));
#2878=CARTESIAN_POINT('',(0.05,0.570529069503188,0.63294820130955));
#2879=CARTESIAN_POINT('',(0.05,0.569336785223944,0.62902025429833));
#2880=CARTESIAN_POINT('',(0.05,0.569184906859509,0.626283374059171));
#2881=CARTESIAN_POINT('',(0.05,0.569107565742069,0.624889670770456));
#2882=B_SPLINE_CURVE_WITH_KNOTS('',3,(#2871,#2872,#2873,#2874,#2875,#2876,#2877,#2878,#2879,
#2880,#2881),.UNSPECIFIED.,.F.,.F.,(4,1,1,1,1,1,1,1,4),(0.,0.126177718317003,0.248820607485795,
0.371539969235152,0.499983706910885,0.627244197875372,0.749225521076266,0.87229795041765,1.),.UNSPECIFIED.);
#2883=DIRECTION('',(-1.,0.,0.));
#2884=VECTOR('',#2883,1.);
#2885=SURFACE_OF_LINEAR_EXTRUSION('',#2882,#2884);
#2886=ORIENTED_EDGE('',*,*,#312,.F.);
#2887=ORIENTED_EDGE('',*,*,#2866,.F.);
#2888=CARTESIAN_POINT('',(0.05,0.569107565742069,0.624889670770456));
#2889=VERTEX_POINT('',#2888);
#2890=EDGE_CURVE('E472',#2859,#2889,#2882,.T.);
#2891=ORIENTED_EDGE('',*,*,#2890,.T.);
#2892=DIRECTION('',(-1.,0.,0.));
#2893=VECTOR('',#2892,1.);
#2894=CARTESIAN_POINT('',(0.05,0.569107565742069,0.624889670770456));
#2895=LINE('',#2894,#2893);
#2896=EDGE_CURVE('E489',#2889,#311,#2895,.T.);
#2897=ORIENTED_EDGE('',*,*,#2896,.T.);
#2898=EDGE_LOOP('',(#2886,#2887,#2891,#2897));
#2899=FACE_BOUND('',#2898,.T.);
#2900=ADVANCED_FACE('F1913',(#2899),#2885,.T.);
#2901=CARTESIAN_POINT('',(0.05,0.569107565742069,0.624889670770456));
#2902=CARTESIAN_POINT('',(0.05,0.569182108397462,0.623494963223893));
#2903=CARTESIAN_POINT('',(0.05,0.56932763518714,0.620772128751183));
#2904=CARTESIAN_POINT('',(0.05,0.570553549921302,0.616858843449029));
#2905=CARTESIAN_POINT('',(0.05,0.572469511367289,0.613258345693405));
#2906=CARTESIAN_POINT('',(0.05,0.575131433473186,0.610059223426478));
#2907=CARTESIAN_POINT('',(0.05,0.578345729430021,0.607449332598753));
#2908=CARTESIAN_POINT('',(0.05,0.581931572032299,0.605476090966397));
#2909=CARTESIAN_POINT('',(0.05,0.585844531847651,0.604291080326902));
#2910=CARTESIAN_POINT('',(0.05,0.588564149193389,0.604135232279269));
#2911=CARTESIAN_POINT('',(0.05,0.589940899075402,0.604056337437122));
#2912=B_SPLINE_CURVE_WITH_KNOTS('',3,(#2901,#2902,#2903,#2904,#2905,#2906,#2907,#2908,#2909,
#2910,#2911),.UNSPECIFIED.,.F.,.F.,(4,1,1,1,1,1,1,1,4),(0.,0.127756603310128,0.249414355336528,
0.372796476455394,0.500111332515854,0.628609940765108,0.750643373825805,0.873768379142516,1.),.UNSPECIFIED.);
#2913=DIRECTION('',(-1.,0.,0.));
#2914=VECTOR('',#2913,1.);
#2915=SURFACE_OF_LINEAR_EXTRUSION('',#2912,#2914);
#2916=ORIENTED_EDGE('',*,*,#326,.F.);
#2917=ORIENTED_EDGE('',*,*,#2896,.F.);
#2918=EDGE_CURVE('E1946',#2889,#2825,#2912,.T.);
#2919=ORIENTED_EDGE('',*,*,#2918,.T.);
#2920=ORIENTED_EDGE('',*,*,#2826,.T.);
#2921=EDGE_LOOP('',(#2916,#2917,#2919,#2920));
#2922=FACE_BOUND('',#2921,.T.);
#2923=ADVANCED_FACE('F1922',(#2922),#2915,.T.);
#2924=CARTESIAN_POINT('',(0.05,0.604690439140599,0.610142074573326));
#2925=DIRECTION('',(-1.,0.,0.));
#2926=DIRECTION('',(0.,0.,1.));
#2927=AXIS2_PLACEMENT_3D('',#2924,#2925,#2926);
#2928=PLANE('',#2927);
#2929=ORIENTED_EDGE('',*,*,#2830,.F.);
#2930=ORIENTED_EDGE('',*,*,#2918,.F.);
#2931=ORIENTED_EDGE('',*,*,#2890,.F.);
#2932=ORIENTED_EDGE('',*,*,#2860,.F.);
#2933=EDGE_LOOP('',(#2929,#2930,#2931,#2932));
#2934=FACE_BOUND('',#2933,.T.);
#2935=ADVANCED_FACE('F469',(#2934),#2928,.T.);
#2936=CLOSED_SHELL('',(#330,#657,#952,#969,#986,#998,#1029,#1053,#1077,#1101,#1125,#1149,#1173,
#1190,#1206,#1243,#1273,#1303,#1326,#1338,#1375,#1405,#1435,#1458,#1470,#1507,#1537,#1567,#1590,
#1602,#1633,#1657,#1681,#1705,#1729,#1753,#1777,#1801,#1825,#1849,#1873,#1890,#1910,#1947,#1977,
#2007,#2030,#2042,#2079,#2109,#2139,#2162,#2174,#2211,#2241,#2271,#2294,#2306,#2337,#2361,#2385,
#2409,#2433,#2457,#2481,#2505,#2522,#2539,#2576,#2606,#2636,#2659,#2671,#2708,#2738,#2768,#2791,
#2803,#2840,#2870,#2900,#2923,#2935));
#2937=MANIFOLD_SOLID_BREP('B2',#2936);
#2938=ADVANCED_BREP_SHAPE_REPRESENTATION('',(#18,#2937),#14);
#2939=SHAPE_DEFINITION_REPRESENTATION(#9,#2938);
ENDSEC;
END-ISO-10303-21;
